VERSION 5.8 ;
BUSBITCHARS "[]" ;
DIVIDERCHAR "/" ;
UNITS
    DATABASE MICRONS 1000 ;
END UNITS

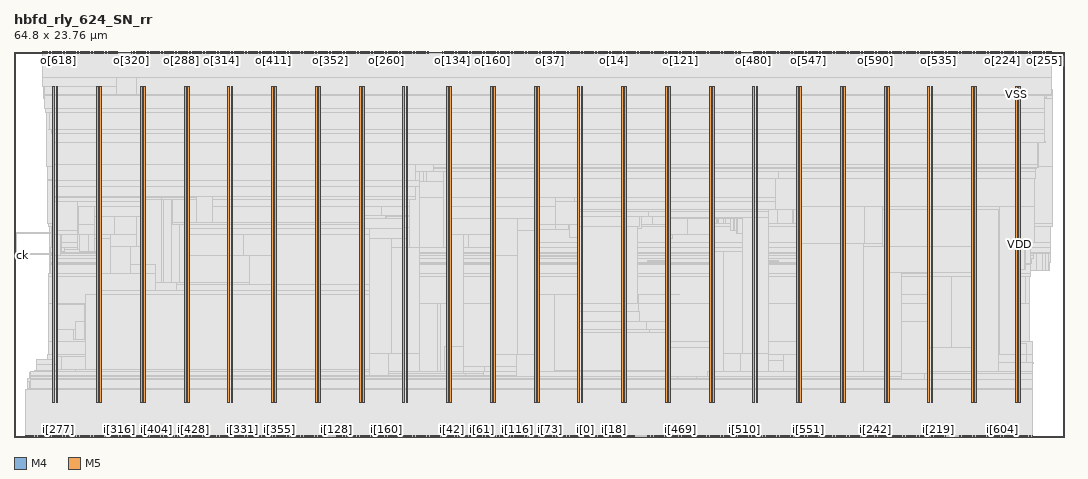
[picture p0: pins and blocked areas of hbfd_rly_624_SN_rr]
MACRO hbfd_rly_624_SN_rr
  FOREIGN hbfd_rly_624_SN_rr 0 0 ;
  CLASS BLOCK ;
  SIZE 64.8 BY 23.76 ;
  PIN ck
    DIRECTION INPUT ;
    USE SIGNAL ;
    PORT
      LAYER M4 ;
        RECT  0 11.184 0.084 11.208 ;
    END
  END ck
  PIN i[0]
    DIRECTION INPUT ;
    USE SIGNAL ;
    PORT
      LAYER M5 ;
        RECT  35.28 0 35.304 0.084 ;
    END
  END i[0]
  PIN i[100]
    DIRECTION INPUT ;
    USE SIGNAL ;
    PORT
      LAYER M5 ;
        RECT  29.52 0 29.544 0.084 ;
    END
  END i[100]
  PIN i[101]
    DIRECTION INPUT ;
    USE SIGNAL ;
    PORT
      LAYER M5 ;
        RECT  29.616 0 29.64 0.084 ;
    END
  END i[101]
  PIN i[102]
    DIRECTION INPUT ;
    USE SIGNAL ;
    PORT
      LAYER M5 ;
        RECT  29.712 0 29.736 0.084 ;
    END
  END i[102]
  PIN i[103]
    DIRECTION INPUT ;
    USE SIGNAL ;
    PORT
      LAYER M5 ;
        RECT  29.808 0 29.832 0.084 ;
    END
  END i[103]
  PIN i[104]
    DIRECTION INPUT ;
    USE SIGNAL ;
    PORT
      LAYER M5 ;
        RECT  29.904 0 29.928 0.084 ;
    END
  END i[104]
  PIN i[105]
    DIRECTION INPUT ;
    USE SIGNAL ;
    PORT
      LAYER M5 ;
        RECT  30 0 30.024 0.084 ;
    END
  END i[105]
  PIN i[106]
    DIRECTION INPUT ;
    USE SIGNAL ;
    PORT
      LAYER M5 ;
        RECT  30.096 0 30.12 0.084 ;
    END
  END i[106]
  PIN i[107]
    DIRECTION INPUT ;
    USE SIGNAL ;
    PORT
      LAYER M5 ;
        RECT  30.192 0 30.216 0.084 ;
    END
  END i[107]
  PIN i[108]
    DIRECTION INPUT ;
    USE SIGNAL ;
    PORT
      LAYER M5 ;
        RECT  30.288 0 30.312 0.084 ;
    END
  END i[108]
  PIN i[109]
    DIRECTION INPUT ;
    USE SIGNAL ;
    PORT
      LAYER M5 ;
        RECT  30.384 0 30.408 0.084 ;
    END
  END i[109]
  PIN i[10]
    DIRECTION INPUT ;
    USE SIGNAL ;
    PORT
      LAYER M5 ;
        RECT  36.24 0 36.264 0.084 ;
    END
  END i[10]
  PIN i[110]
    DIRECTION INPUT ;
    USE SIGNAL ;
    PORT
      LAYER M5 ;
        RECT  30.48 0 30.504 0.084 ;
    END
  END i[110]
  PIN i[111]
    DIRECTION INPUT ;
    USE SIGNAL ;
    PORT
      LAYER M5 ;
        RECT  30.576 0 30.6 0.084 ;
    END
  END i[111]
  PIN i[112]
    DIRECTION INPUT ;
    USE SIGNAL ;
    PORT
      LAYER M5 ;
        RECT  30.672 0 30.696 0.084 ;
    END
  END i[112]
  PIN i[113]
    DIRECTION INPUT ;
    USE SIGNAL ;
    PORT
      LAYER M5 ;
        RECT  30.768 0 30.792 0.084 ;
    END
  END i[113]
  PIN i[114]
    DIRECTION INPUT ;
    USE SIGNAL ;
    PORT
      LAYER M5 ;
        RECT  30.864 0 30.888 0.084 ;
    END
  END i[114]
  PIN i[115]
    DIRECTION INPUT ;
    USE SIGNAL ;
    PORT
      LAYER M5 ;
        RECT  30.96 0 30.984 0.084 ;
    END
  END i[115]
  PIN i[116]
    DIRECTION INPUT ;
    USE SIGNAL ;
    PORT
      LAYER M5 ;
        RECT  31.056 0 31.08 0.084 ;
    END
  END i[116]
  PIN i[117]
    DIRECTION INPUT ;
    USE SIGNAL ;
    PORT
      LAYER M5 ;
        RECT  31.152 0 31.176 0.084 ;
    END
  END i[117]
  PIN i[118]
    DIRECTION INPUT ;
    USE SIGNAL ;
    PORT
      LAYER M5 ;
        RECT  31.248 0 31.272 0.084 ;
    END
  END i[118]
  PIN i[119]
    DIRECTION INPUT ;
    USE SIGNAL ;
    PORT
      LAYER M5 ;
        RECT  31.344 0 31.368 0.084 ;
    END
  END i[119]
  PIN i[11]
    DIRECTION INPUT ;
    USE SIGNAL ;
    PORT
      LAYER M5 ;
        RECT  36.336 0 36.36 0.084 ;
    END
  END i[11]
  PIN i[120]
    DIRECTION INPUT ;
    USE SIGNAL ;
    PORT
      LAYER M5 ;
        RECT  31.44 0 31.464 0.084 ;
    END
  END i[120]
  PIN i[121]
    DIRECTION INPUT ;
    USE SIGNAL ;
    PORT
      LAYER M5 ;
        RECT  31.536 0 31.56 0.084 ;
    END
  END i[121]
  PIN i[122]
    DIRECTION INPUT ;
    USE SIGNAL ;
    PORT
      LAYER M5 ;
        RECT  31.632 0 31.656 0.084 ;
    END
  END i[122]
  PIN i[123]
    DIRECTION INPUT ;
    USE SIGNAL ;
    PORT
      LAYER M5 ;
        RECT  31.728 0 31.752 0.084 ;
    END
  END i[123]
  PIN i[124]
    DIRECTION INPUT ;
    USE SIGNAL ;
    PORT
      LAYER M5 ;
        RECT  31.824 0 31.848 0.084 ;
    END
  END i[124]
  PIN i[125]
    DIRECTION INPUT ;
    USE SIGNAL ;
    PORT
      LAYER M5 ;
        RECT  31.92 0 31.944 0.084 ;
    END
  END i[125]
  PIN i[126]
    DIRECTION INPUT ;
    USE SIGNAL ;
    PORT
      LAYER M5 ;
        RECT  32.016 0 32.04 0.084 ;
    END
  END i[126]
  PIN i[127]
    DIRECTION INPUT ;
    USE SIGNAL ;
    PORT
      LAYER M5 ;
        RECT  32.112 0 32.136 0.084 ;
    END
  END i[127]
  PIN i[128]
    DIRECTION INPUT ;
    USE SIGNAL ;
    PORT
      LAYER M5 ;
        RECT  19.92 0 19.944 0.084 ;
    END
  END i[128]
  PIN i[129]
    DIRECTION INPUT ;
    USE SIGNAL ;
    PORT
      LAYER M5 ;
        RECT  20.016 0 20.04 0.084 ;
    END
  END i[129]
  PIN i[12]
    DIRECTION INPUT ;
    USE SIGNAL ;
    PORT
      LAYER M5 ;
        RECT  36.432 0 36.456 0.084 ;
    END
  END i[12]
  PIN i[130]
    DIRECTION INPUT ;
    USE SIGNAL ;
    PORT
      LAYER M5 ;
        RECT  20.112 0 20.136 0.084 ;
    END
  END i[130]
  PIN i[131]
    DIRECTION INPUT ;
    USE SIGNAL ;
    PORT
      LAYER M5 ;
        RECT  20.208 0 20.232 0.084 ;
    END
  END i[131]
  PIN i[132]
    DIRECTION INPUT ;
    USE SIGNAL ;
    PORT
      LAYER M5 ;
        RECT  20.304 0 20.328 0.084 ;
    END
  END i[132]
  PIN i[133]
    DIRECTION INPUT ;
    USE SIGNAL ;
    PORT
      LAYER M5 ;
        RECT  20.4 0 20.424 0.084 ;
    END
  END i[133]
  PIN i[134]
    DIRECTION INPUT ;
    USE SIGNAL ;
    PORT
      LAYER M5 ;
        RECT  20.496 0 20.52 0.084 ;
    END
  END i[134]
  PIN i[135]
    DIRECTION INPUT ;
    USE SIGNAL ;
    PORT
      LAYER M5 ;
        RECT  20.592 0 20.616 0.084 ;
    END
  END i[135]
  PIN i[136]
    DIRECTION INPUT ;
    USE SIGNAL ;
    PORT
      LAYER M5 ;
        RECT  20.688 0 20.712 0.084 ;
    END
  END i[136]
  PIN i[137]
    DIRECTION INPUT ;
    USE SIGNAL ;
    PORT
      LAYER M5 ;
        RECT  20.784 0 20.808 0.084 ;
    END
  END i[137]
  PIN i[138]
    DIRECTION INPUT ;
    USE SIGNAL ;
    PORT
      LAYER M5 ;
        RECT  20.88 0 20.904 0.084 ;
    END
  END i[138]
  PIN i[139]
    DIRECTION INPUT ;
    USE SIGNAL ;
    PORT
      LAYER M5 ;
        RECT  20.976 0 21 0.084 ;
    END
  END i[139]
  PIN i[13]
    DIRECTION INPUT ;
    USE SIGNAL ;
    PORT
      LAYER M5 ;
        RECT  36.528 0 36.552 0.084 ;
    END
  END i[13]
  PIN i[140]
    DIRECTION INPUT ;
    USE SIGNAL ;
    PORT
      LAYER M5 ;
        RECT  21.072 0 21.096 0.084 ;
    END
  END i[140]
  PIN i[141]
    DIRECTION INPUT ;
    USE SIGNAL ;
    PORT
      LAYER M5 ;
        RECT  21.168 0 21.192 0.084 ;
    END
  END i[141]
  PIN i[142]
    DIRECTION INPUT ;
    USE SIGNAL ;
    PORT
      LAYER M5 ;
        RECT  21.264 0 21.288 0.084 ;
    END
  END i[142]
  PIN i[143]
    DIRECTION INPUT ;
    USE SIGNAL ;
    PORT
      LAYER M5 ;
        RECT  21.36 0 21.384 0.084 ;
    END
  END i[143]
  PIN i[144]
    DIRECTION INPUT ;
    USE SIGNAL ;
    PORT
      LAYER M5 ;
        RECT  21.456 0 21.48 0.084 ;
    END
  END i[144]
  PIN i[145]
    DIRECTION INPUT ;
    USE SIGNAL ;
    PORT
      LAYER M5 ;
        RECT  21.552 0 21.576 0.084 ;
    END
  END i[145]
  PIN i[146]
    DIRECTION INPUT ;
    USE SIGNAL ;
    PORT
      LAYER M5 ;
        RECT  21.648 0 21.672 0.084 ;
    END
  END i[146]
  PIN i[147]
    DIRECTION INPUT ;
    USE SIGNAL ;
    PORT
      LAYER M5 ;
        RECT  21.744 0 21.768 0.084 ;
    END
  END i[147]
  PIN i[148]
    DIRECTION INPUT ;
    USE SIGNAL ;
    PORT
      LAYER M5 ;
        RECT  21.84 0 21.864 0.084 ;
    END
  END i[148]
  PIN i[149]
    DIRECTION INPUT ;
    USE SIGNAL ;
    PORT
      LAYER M5 ;
        RECT  21.936 0 21.96 0.084 ;
    END
  END i[149]
  PIN i[14]
    DIRECTION INPUT ;
    USE SIGNAL ;
    PORT
      LAYER M5 ;
        RECT  36.624 0 36.648 0.084 ;
    END
  END i[14]
  PIN i[150]
    DIRECTION INPUT ;
    USE SIGNAL ;
    PORT
      LAYER M5 ;
        RECT  22.032 0 22.056 0.084 ;
    END
  END i[150]
  PIN i[151]
    DIRECTION INPUT ;
    USE SIGNAL ;
    PORT
      LAYER M5 ;
        RECT  22.128 0 22.152 0.084 ;
    END
  END i[151]
  PIN i[152]
    DIRECTION INPUT ;
    USE SIGNAL ;
    PORT
      LAYER M5 ;
        RECT  22.224 0 22.248 0.084 ;
    END
  END i[152]
  PIN i[153]
    DIRECTION INPUT ;
    USE SIGNAL ;
    PORT
      LAYER M5 ;
        RECT  22.32 0 22.344 0.084 ;
    END
  END i[153]
  PIN i[154]
    DIRECTION INPUT ;
    USE SIGNAL ;
    PORT
      LAYER M5 ;
        RECT  22.416 0 22.44 0.084 ;
    END
  END i[154]
  PIN i[155]
    DIRECTION INPUT ;
    USE SIGNAL ;
    PORT
      LAYER M5 ;
        RECT  22.512 0 22.536 0.084 ;
    END
  END i[155]
  PIN i[156]
    DIRECTION INPUT ;
    USE SIGNAL ;
    PORT
      LAYER M5 ;
        RECT  22.608 0 22.632 0.084 ;
    END
  END i[156]
  PIN i[157]
    DIRECTION INPUT ;
    USE SIGNAL ;
    PORT
      LAYER M5 ;
        RECT  22.704 0 22.728 0.084 ;
    END
  END i[157]
  PIN i[158]
    DIRECTION INPUT ;
    USE SIGNAL ;
    PORT
      LAYER M5 ;
        RECT  22.8 0 22.824 0.084 ;
    END
  END i[158]
  PIN i[159]
    DIRECTION INPUT ;
    USE SIGNAL ;
    PORT
      LAYER M5 ;
        RECT  22.896 0 22.92 0.084 ;
    END
  END i[159]
  PIN i[15]
    DIRECTION INPUT ;
    USE SIGNAL ;
    PORT
      LAYER M5 ;
        RECT  36.72 0 36.744 0.084 ;
    END
  END i[15]
  PIN i[160]
    DIRECTION INPUT ;
    USE SIGNAL ;
    PORT
      LAYER M5 ;
        RECT  22.992 0 23.016 0.084 ;
    END
  END i[160]
  PIN i[161]
    DIRECTION INPUT ;
    USE SIGNAL ;
    PORT
      LAYER M5 ;
        RECT  23.088 0 23.112 0.084 ;
    END
  END i[161]
  PIN i[162]
    DIRECTION INPUT ;
    USE SIGNAL ;
    PORT
      LAYER M5 ;
        RECT  23.184 0 23.208 0.084 ;
    END
  END i[162]
  PIN i[163]
    DIRECTION INPUT ;
    USE SIGNAL ;
    PORT
      LAYER M5 ;
        RECT  23.28 0 23.304 0.084 ;
    END
  END i[163]
  PIN i[164]
    DIRECTION INPUT ;
    USE SIGNAL ;
    PORT
      LAYER M5 ;
        RECT  23.376 0 23.4 0.084 ;
    END
  END i[164]
  PIN i[165]
    DIRECTION INPUT ;
    USE SIGNAL ;
    PORT
      LAYER M5 ;
        RECT  23.472 0 23.496 0.084 ;
    END
  END i[165]
  PIN i[166]
    DIRECTION INPUT ;
    USE SIGNAL ;
    PORT
      LAYER M5 ;
        RECT  23.568 0 23.592 0.084 ;
    END
  END i[166]
  PIN i[167]
    DIRECTION INPUT ;
    USE SIGNAL ;
    PORT
      LAYER M5 ;
        RECT  23.664 0 23.688 0.084 ;
    END
  END i[167]
  PIN i[168]
    DIRECTION INPUT ;
    USE SIGNAL ;
    PORT
      LAYER M5 ;
        RECT  23.76 0 23.784 0.084 ;
    END
  END i[168]
  PIN i[169]
    DIRECTION INPUT ;
    USE SIGNAL ;
    PORT
      LAYER M5 ;
        RECT  23.856 0 23.88 0.084 ;
    END
  END i[169]
  PIN i[16]
    DIRECTION INPUT ;
    USE SIGNAL ;
    PORT
      LAYER M5 ;
        RECT  36.816 0 36.84 0.084 ;
    END
  END i[16]
  PIN i[170]
    DIRECTION INPUT ;
    USE SIGNAL ;
    PORT
      LAYER M5 ;
        RECT  23.952 0 23.976 0.084 ;
    END
  END i[170]
  PIN i[171]
    DIRECTION INPUT ;
    USE SIGNAL ;
    PORT
      LAYER M5 ;
        RECT  24.048 0 24.072 0.084 ;
    END
  END i[171]
  PIN i[172]
    DIRECTION INPUT ;
    USE SIGNAL ;
    PORT
      LAYER M5 ;
        RECT  24.144 0 24.168 0.084 ;
    END
  END i[172]
  PIN i[173]
    DIRECTION INPUT ;
    USE SIGNAL ;
    PORT
      LAYER M5 ;
        RECT  24.24 0 24.264 0.084 ;
    END
  END i[173]
  PIN i[174]
    DIRECTION INPUT ;
    USE SIGNAL ;
    PORT
      LAYER M5 ;
        RECT  24.336 0 24.36 0.084 ;
    END
  END i[174]
  PIN i[175]
    DIRECTION INPUT ;
    USE SIGNAL ;
    PORT
      LAYER M5 ;
        RECT  24.432 0 24.456 0.084 ;
    END
  END i[175]
  PIN i[176]
    DIRECTION INPUT ;
    USE SIGNAL ;
    PORT
      LAYER M5 ;
        RECT  24.528 0 24.552 0.084 ;
    END
  END i[176]
  PIN i[177]
    DIRECTION INPUT ;
    USE SIGNAL ;
    PORT
      LAYER M5 ;
        RECT  24.624 0 24.648 0.084 ;
    END
  END i[177]
  PIN i[178]
    DIRECTION INPUT ;
    USE SIGNAL ;
    PORT
      LAYER M5 ;
        RECT  24.72 0 24.744 0.084 ;
    END
  END i[178]
  PIN i[179]
    DIRECTION INPUT ;
    USE SIGNAL ;
    PORT
      LAYER M5 ;
        RECT  24.816 0 24.84 0.084 ;
    END
  END i[179]
  PIN i[17]
    DIRECTION INPUT ;
    USE SIGNAL ;
    PORT
      LAYER M5 ;
        RECT  36.912 0 36.936 0.084 ;
    END
  END i[17]
  PIN i[180]
    DIRECTION INPUT ;
    USE SIGNAL ;
    PORT
      LAYER M5 ;
        RECT  24.912 0 24.936 0.084 ;
    END
  END i[180]
  PIN i[181]
    DIRECTION INPUT ;
    USE SIGNAL ;
    PORT
      LAYER M5 ;
        RECT  25.008 0 25.032 0.084 ;
    END
  END i[181]
  PIN i[182]
    DIRECTION INPUT ;
    USE SIGNAL ;
    PORT
      LAYER M5 ;
        RECT  25.104 0 25.128 0.084 ;
    END
  END i[182]
  PIN i[183]
    DIRECTION INPUT ;
    USE SIGNAL ;
    PORT
      LAYER M5 ;
        RECT  25.2 0 25.224 0.084 ;
    END
  END i[183]
  PIN i[184]
    DIRECTION INPUT ;
    USE SIGNAL ;
    PORT
      LAYER M5 ;
        RECT  25.296 0 25.32 0.084 ;
    END
  END i[184]
  PIN i[185]
    DIRECTION INPUT ;
    USE SIGNAL ;
    PORT
      LAYER M5 ;
        RECT  25.392 0 25.416 0.084 ;
    END
  END i[185]
  PIN i[186]
    DIRECTION INPUT ;
    USE SIGNAL ;
    PORT
      LAYER M5 ;
        RECT  25.488 0 25.512 0.084 ;
    END
  END i[186]
  PIN i[187]
    DIRECTION INPUT ;
    USE SIGNAL ;
    PORT
      LAYER M5 ;
        RECT  25.584 0 25.608 0.084 ;
    END
  END i[187]
  PIN i[188]
    DIRECTION INPUT ;
    USE SIGNAL ;
    PORT
      LAYER M5 ;
        RECT  25.68 0 25.704 0.084 ;
    END
  END i[188]
  PIN i[189]
    DIRECTION INPUT ;
    USE SIGNAL ;
    PORT
      LAYER M5 ;
        RECT  25.776 0 25.8 0.084 ;
    END
  END i[189]
  PIN i[18]
    DIRECTION INPUT ;
    USE SIGNAL ;
    PORT
      LAYER M5 ;
        RECT  37.008 0 37.032 0.084 ;
    END
  END i[18]
  PIN i[190]
    DIRECTION INPUT ;
    USE SIGNAL ;
    PORT
      LAYER M5 ;
        RECT  25.872 0 25.896 0.084 ;
    END
  END i[190]
  PIN i[191]
    DIRECTION INPUT ;
    USE SIGNAL ;
    PORT
      LAYER M5 ;
        RECT  25.968 0 25.992 0.084 ;
    END
  END i[191]
  PIN i[192]
    DIRECTION INPUT ;
    USE SIGNAL ;
    PORT
      LAYER M5 ;
        RECT  54.48 0 54.504 0.084 ;
    END
  END i[192]
  PIN i[193]
    DIRECTION INPUT ;
    USE SIGNAL ;
    PORT
      LAYER M5 ;
        RECT  54.576 0 54.6 0.084 ;
    END
  END i[193]
  PIN i[194]
    DIRECTION INPUT ;
    USE SIGNAL ;
    PORT
      LAYER M5 ;
        RECT  54.672 0 54.696 0.084 ;
    END
  END i[194]
  PIN i[195]
    DIRECTION INPUT ;
    USE SIGNAL ;
    PORT
      LAYER M5 ;
        RECT  54.768 0 54.792 0.084 ;
    END
  END i[195]
  PIN i[196]
    DIRECTION INPUT ;
    USE SIGNAL ;
    PORT
      LAYER M5 ;
        RECT  54.864 0 54.888 0.084 ;
    END
  END i[196]
  PIN i[197]
    DIRECTION INPUT ;
    USE SIGNAL ;
    PORT
      LAYER M5 ;
        RECT  54.96 0 54.984 0.084 ;
    END
  END i[197]
  PIN i[198]
    DIRECTION INPUT ;
    USE SIGNAL ;
    PORT
      LAYER M5 ;
        RECT  55.056 0 55.08 0.084 ;
    END
  END i[198]
  PIN i[199]
    DIRECTION INPUT ;
    USE SIGNAL ;
    PORT
      LAYER M5 ;
        RECT  55.152 0 55.176 0.084 ;
    END
  END i[199]
  PIN i[19]
    DIRECTION INPUT ;
    USE SIGNAL ;
    PORT
      LAYER M5 ;
        RECT  37.104 0 37.128 0.084 ;
    END
  END i[19]
  PIN i[1]
    DIRECTION INPUT ;
    USE SIGNAL ;
    PORT
      LAYER M5 ;
        RECT  35.376 0 35.4 0.084 ;
    END
  END i[1]
  PIN i[200]
    DIRECTION INPUT ;
    USE SIGNAL ;
    PORT
      LAYER M5 ;
        RECT  55.248 0 55.272 0.084 ;
    END
  END i[200]
  PIN i[201]
    DIRECTION INPUT ;
    USE SIGNAL ;
    PORT
      LAYER M5 ;
        RECT  55.344 0 55.368 0.084 ;
    END
  END i[201]
  PIN i[202]
    DIRECTION INPUT ;
    USE SIGNAL ;
    PORT
      LAYER M5 ;
        RECT  55.44 0 55.464 0.084 ;
    END
  END i[202]
  PIN i[203]
    DIRECTION INPUT ;
    USE SIGNAL ;
    PORT
      LAYER M5 ;
        RECT  55.536 0 55.56 0.084 ;
    END
  END i[203]
  PIN i[204]
    DIRECTION INPUT ;
    USE SIGNAL ;
    PORT
      LAYER M5 ;
        RECT  55.632 0 55.656 0.084 ;
    END
  END i[204]
  PIN i[205]
    DIRECTION INPUT ;
    USE SIGNAL ;
    PORT
      LAYER M5 ;
        RECT  55.728 0 55.752 0.084 ;
    END
  END i[205]
  PIN i[206]
    DIRECTION INPUT ;
    USE SIGNAL ;
    PORT
      LAYER M5 ;
        RECT  55.824 0 55.848 0.084 ;
    END
  END i[206]
  PIN i[207]
    DIRECTION INPUT ;
    USE SIGNAL ;
    PORT
      LAYER M5 ;
        RECT  55.92 0 55.944 0.084 ;
    END
  END i[207]
  PIN i[208]
    DIRECTION INPUT ;
    USE SIGNAL ;
    PORT
      LAYER M5 ;
        RECT  56.016 0 56.04 0.084 ;
    END
  END i[208]
  PIN i[209]
    DIRECTION INPUT ;
    USE SIGNAL ;
    PORT
      LAYER M5 ;
        RECT  56.112 0 56.136 0.084 ;
    END
  END i[209]
  PIN i[20]
    DIRECTION INPUT ;
    USE SIGNAL ;
    PORT
      LAYER M5 ;
        RECT  37.2 0 37.224 0.084 ;
    END
  END i[20]
  PIN i[210]
    DIRECTION INPUT ;
    USE SIGNAL ;
    PORT
      LAYER M5 ;
        RECT  56.208 0 56.232 0.084 ;
    END
  END i[210]
  PIN i[211]
    DIRECTION INPUT ;
    USE SIGNAL ;
    PORT
      LAYER M5 ;
        RECT  56.304 0 56.328 0.084 ;
    END
  END i[211]
  PIN i[212]
    DIRECTION INPUT ;
    USE SIGNAL ;
    PORT
      LAYER M5 ;
        RECT  56.4 0 56.424 0.084 ;
    END
  END i[212]
  PIN i[213]
    DIRECTION INPUT ;
    USE SIGNAL ;
    PORT
      LAYER M5 ;
        RECT  56.496 0 56.52 0.084 ;
    END
  END i[213]
  PIN i[214]
    DIRECTION INPUT ;
    USE SIGNAL ;
    PORT
      LAYER M5 ;
        RECT  56.592 0 56.616 0.084 ;
    END
  END i[214]
  PIN i[215]
    DIRECTION INPUT ;
    USE SIGNAL ;
    PORT
      LAYER M5 ;
        RECT  56.688 0 56.712 0.084 ;
    END
  END i[215]
  PIN i[216]
    DIRECTION INPUT ;
    USE SIGNAL ;
    PORT
      LAYER M5 ;
        RECT  56.784 0 56.808 0.084 ;
    END
  END i[216]
  PIN i[217]
    DIRECTION INPUT ;
    USE SIGNAL ;
    PORT
      LAYER M5 ;
        RECT  56.88 0 56.904 0.084 ;
    END
  END i[217]
  PIN i[218]
    DIRECTION INPUT ;
    USE SIGNAL ;
    PORT
      LAYER M5 ;
        RECT  56.976 0 57 0.084 ;
    END
  END i[218]
  PIN i[219]
    DIRECTION INPUT ;
    USE SIGNAL ;
    PORT
      LAYER M5 ;
        RECT  57.072 0 57.096 0.084 ;
    END
  END i[219]
  PIN i[21]
    DIRECTION INPUT ;
    USE SIGNAL ;
    PORT
      LAYER M5 ;
        RECT  37.296 0 37.32 0.084 ;
    END
  END i[21]
  PIN i[220]
    DIRECTION INPUT ;
    USE SIGNAL ;
    PORT
      LAYER M5 ;
        RECT  57.168 0 57.192 0.084 ;
    END
  END i[220]
  PIN i[221]
    DIRECTION INPUT ;
    USE SIGNAL ;
    PORT
      LAYER M5 ;
        RECT  57.264 0 57.288 0.084 ;
    END
  END i[221]
  PIN i[222]
    DIRECTION INPUT ;
    USE SIGNAL ;
    PORT
      LAYER M5 ;
        RECT  57.36 0 57.384 0.084 ;
    END
  END i[222]
  PIN i[223]
    DIRECTION INPUT ;
    USE SIGNAL ;
    PORT
      LAYER M5 ;
        RECT  57.456 0 57.48 0.084 ;
    END
  END i[223]
  PIN i[224]
    DIRECTION INPUT ;
    USE SIGNAL ;
    PORT
      LAYER M5 ;
        RECT  51.408 0 51.432 0.084 ;
    END
  END i[224]
  PIN i[225]
    DIRECTION INPUT ;
    USE SIGNAL ;
    PORT
      LAYER M5 ;
        RECT  51.504 0 51.528 0.084 ;
    END
  END i[225]
  PIN i[226]
    DIRECTION INPUT ;
    USE SIGNAL ;
    PORT
      LAYER M5 ;
        RECT  51.6 0 51.624 0.084 ;
    END
  END i[226]
  PIN i[227]
    DIRECTION INPUT ;
    USE SIGNAL ;
    PORT
      LAYER M5 ;
        RECT  51.696 0 51.72 0.084 ;
    END
  END i[227]
  PIN i[228]
    DIRECTION INPUT ;
    USE SIGNAL ;
    PORT
      LAYER M5 ;
        RECT  51.792 0 51.816 0.084 ;
    END
  END i[228]
  PIN i[229]
    DIRECTION INPUT ;
    USE SIGNAL ;
    PORT
      LAYER M5 ;
        RECT  51.888 0 51.912 0.084 ;
    END
  END i[229]
  PIN i[22]
    DIRECTION INPUT ;
    USE SIGNAL ;
    PORT
      LAYER M5 ;
        RECT  37.392 0 37.416 0.084 ;
    END
  END i[22]
  PIN i[230]
    DIRECTION INPUT ;
    USE SIGNAL ;
    PORT
      LAYER M5 ;
        RECT  51.984 0 52.008 0.084 ;
    END
  END i[230]
  PIN i[231]
    DIRECTION INPUT ;
    USE SIGNAL ;
    PORT
      LAYER M5 ;
        RECT  52.08 0 52.104 0.084 ;
    END
  END i[231]
  PIN i[232]
    DIRECTION INPUT ;
    USE SIGNAL ;
    PORT
      LAYER M5 ;
        RECT  52.176 0 52.2 0.084 ;
    END
  END i[232]
  PIN i[233]
    DIRECTION INPUT ;
    USE SIGNAL ;
    PORT
      LAYER M5 ;
        RECT  52.272 0 52.296 0.084 ;
    END
  END i[233]
  PIN i[234]
    DIRECTION INPUT ;
    USE SIGNAL ;
    PORT
      LAYER M5 ;
        RECT  52.368 0 52.392 0.084 ;
    END
  END i[234]
  PIN i[235]
    DIRECTION INPUT ;
    USE SIGNAL ;
    PORT
      LAYER M5 ;
        RECT  52.464 0 52.488 0.084 ;
    END
  END i[235]
  PIN i[236]
    DIRECTION INPUT ;
    USE SIGNAL ;
    PORT
      LAYER M5 ;
        RECT  52.56 0 52.584 0.084 ;
    END
  END i[236]
  PIN i[237]
    DIRECTION INPUT ;
    USE SIGNAL ;
    PORT
      LAYER M5 ;
        RECT  52.656 0 52.68 0.084 ;
    END
  END i[237]
  PIN i[238]
    DIRECTION INPUT ;
    USE SIGNAL ;
    PORT
      LAYER M5 ;
        RECT  52.752 0 52.776 0.084 ;
    END
  END i[238]
  PIN i[239]
    DIRECTION INPUT ;
    USE SIGNAL ;
    PORT
      LAYER M5 ;
        RECT  52.848 0 52.872 0.084 ;
    END
  END i[239]
  PIN i[23]
    DIRECTION INPUT ;
    USE SIGNAL ;
    PORT
      LAYER M5 ;
        RECT  37.488 0 37.512 0.084 ;
    END
  END i[23]
  PIN i[240]
    DIRECTION INPUT ;
    USE SIGNAL ;
    PORT
      LAYER M5 ;
        RECT  52.944 0 52.968 0.084 ;
    END
  END i[240]
  PIN i[241]
    DIRECTION INPUT ;
    USE SIGNAL ;
    PORT
      LAYER M5 ;
        RECT  53.04 0 53.064 0.084 ;
    END
  END i[241]
  PIN i[242]
    DIRECTION INPUT ;
    USE SIGNAL ;
    PORT
      LAYER M5 ;
        RECT  53.136 0 53.16 0.084 ;
    END
  END i[242]
  PIN i[243]
    DIRECTION INPUT ;
    USE SIGNAL ;
    PORT
      LAYER M5 ;
        RECT  53.232 0 53.256 0.084 ;
    END
  END i[243]
  PIN i[244]
    DIRECTION INPUT ;
    USE SIGNAL ;
    PORT
      LAYER M5 ;
        RECT  53.328 0 53.352 0.084 ;
    END
  END i[244]
  PIN i[245]
    DIRECTION INPUT ;
    USE SIGNAL ;
    PORT
      LAYER M5 ;
        RECT  53.424 0 53.448 0.084 ;
    END
  END i[245]
  PIN i[246]
    DIRECTION INPUT ;
    USE SIGNAL ;
    PORT
      LAYER M5 ;
        RECT  53.52 0 53.544 0.084 ;
    END
  END i[246]
  PIN i[247]
    DIRECTION INPUT ;
    USE SIGNAL ;
    PORT
      LAYER M5 ;
        RECT  53.616 0 53.64 0.084 ;
    END
  END i[247]
  PIN i[248]
    DIRECTION INPUT ;
    USE SIGNAL ;
    PORT
      LAYER M5 ;
        RECT  53.712 0 53.736 0.084 ;
    END
  END i[248]
  PIN i[249]
    DIRECTION INPUT ;
    USE SIGNAL ;
    PORT
      LAYER M5 ;
        RECT  53.808 0 53.832 0.084 ;
    END
  END i[249]
  PIN i[24]
    DIRECTION INPUT ;
    USE SIGNAL ;
    PORT
      LAYER M5 ;
        RECT  37.584 0 37.608 0.084 ;
    END
  END i[24]
  PIN i[250]
    DIRECTION INPUT ;
    USE SIGNAL ;
    PORT
      LAYER M5 ;
        RECT  53.904 0 53.928 0.084 ;
    END
  END i[250]
  PIN i[251]
    DIRECTION INPUT ;
    USE SIGNAL ;
    PORT
      LAYER M5 ;
        RECT  54 0 54.024 0.084 ;
    END
  END i[251]
  PIN i[252]
    DIRECTION INPUT ;
    USE SIGNAL ;
    PORT
      LAYER M5 ;
        RECT  54.096 0 54.12 0.084 ;
    END
  END i[252]
  PIN i[253]
    DIRECTION INPUT ;
    USE SIGNAL ;
    PORT
      LAYER M5 ;
        RECT  54.192 0 54.216 0.084 ;
    END
  END i[253]
  PIN i[254]
    DIRECTION INPUT ;
    USE SIGNAL ;
    PORT
      LAYER M5 ;
        RECT  54.288 0 54.312 0.084 ;
    END
  END i[254]
  PIN i[255]
    DIRECTION INPUT ;
    USE SIGNAL ;
    PORT
      LAYER M5 ;
        RECT  54.384 0 54.408 0.084 ;
    END
  END i[255]
  PIN i[256]
    DIRECTION INPUT ;
    USE SIGNAL ;
    PORT
      LAYER M5 ;
        RECT  0.72 0 0.744 0.084 ;
    END
  END i[256]
  PIN i[257]
    DIRECTION INPUT ;
    USE SIGNAL ;
    PORT
      LAYER M5 ;
        RECT  0.816 0 0.84 0.084 ;
    END
  END i[257]
  PIN i[258]
    DIRECTION INPUT ;
    USE SIGNAL ;
    PORT
      LAYER M5 ;
        RECT  0.912 0 0.936 0.084 ;
    END
  END i[258]
  PIN i[259]
    DIRECTION INPUT ;
    USE SIGNAL ;
    PORT
      LAYER M5 ;
        RECT  1.008 0 1.032 0.084 ;
    END
  END i[259]
  PIN i[25]
    DIRECTION INPUT ;
    USE SIGNAL ;
    PORT
      LAYER M5 ;
        RECT  37.68 0 37.704 0.084 ;
    END
  END i[25]
  PIN i[260]
    DIRECTION INPUT ;
    USE SIGNAL ;
    PORT
      LAYER M5 ;
        RECT  1.104 0 1.128 0.084 ;
    END
  END i[260]
  PIN i[261]
    DIRECTION INPUT ;
    USE SIGNAL ;
    PORT
      LAYER M5 ;
        RECT  1.2 0 1.224 0.084 ;
    END
  END i[261]
  PIN i[262]
    DIRECTION INPUT ;
    USE SIGNAL ;
    PORT
      LAYER M5 ;
        RECT  1.296 0 1.32 0.084 ;
    END
  END i[262]
  PIN i[263]
    DIRECTION INPUT ;
    USE SIGNAL ;
    PORT
      LAYER M5 ;
        RECT  1.392 0 1.416 0.084 ;
    END
  END i[263]
  PIN i[264]
    DIRECTION INPUT ;
    USE SIGNAL ;
    PORT
      LAYER M5 ;
        RECT  1.488 0 1.512 0.084 ;
    END
  END i[264]
  PIN i[265]
    DIRECTION INPUT ;
    USE SIGNAL ;
    PORT
      LAYER M5 ;
        RECT  1.584 0 1.608 0.084 ;
    END
  END i[265]
  PIN i[266]
    DIRECTION INPUT ;
    USE SIGNAL ;
    PORT
      LAYER M5 ;
        RECT  1.68 0 1.704 0.084 ;
    END
  END i[266]
  PIN i[267]
    DIRECTION INPUT ;
    USE SIGNAL ;
    PORT
      LAYER M5 ;
        RECT  1.776 0 1.8 0.084 ;
    END
  END i[267]
  PIN i[268]
    DIRECTION INPUT ;
    USE SIGNAL ;
    PORT
      LAYER M5 ;
        RECT  1.872 0 1.896 0.084 ;
    END
  END i[268]
  PIN i[269]
    DIRECTION INPUT ;
    USE SIGNAL ;
    PORT
      LAYER M5 ;
        RECT  1.968 0 1.992 0.084 ;
    END
  END i[269]
  PIN i[26]
    DIRECTION INPUT ;
    USE SIGNAL ;
    PORT
      LAYER M5 ;
        RECT  37.776 0 37.8 0.084 ;
    END
  END i[26]
  PIN i[270]
    DIRECTION INPUT ;
    USE SIGNAL ;
    PORT
      LAYER M5 ;
        RECT  2.064 0 2.088 0.084 ;
    END
  END i[270]
  PIN i[271]
    DIRECTION INPUT ;
    USE SIGNAL ;
    PORT
      LAYER M5 ;
        RECT  2.16 0 2.184 0.084 ;
    END
  END i[271]
  PIN i[272]
    DIRECTION INPUT ;
    USE SIGNAL ;
    PORT
      LAYER M5 ;
        RECT  2.256 0 2.28 0.084 ;
    END
  END i[272]
  PIN i[273]
    DIRECTION INPUT ;
    USE SIGNAL ;
    PORT
      LAYER M5 ;
        RECT  2.352 0 2.376 0.084 ;
    END
  END i[273]
  PIN i[274]
    DIRECTION INPUT ;
    USE SIGNAL ;
    PORT
      LAYER M5 ;
        RECT  2.448 0 2.472 0.084 ;
    END
  END i[274]
  PIN i[275]
    DIRECTION INPUT ;
    USE SIGNAL ;
    PORT
      LAYER M5 ;
        RECT  2.544 0 2.568 0.084 ;
    END
  END i[275]
  PIN i[276]
    DIRECTION INPUT ;
    USE SIGNAL ;
    PORT
      LAYER M5 ;
        RECT  2.64 0 2.664 0.084 ;
    END
  END i[276]
  PIN i[277]
    DIRECTION INPUT ;
    USE SIGNAL ;
    PORT
      LAYER M5 ;
        RECT  2.736 0 2.76 0.084 ;
    END
  END i[277]
  PIN i[278]
    DIRECTION INPUT ;
    USE SIGNAL ;
    PORT
      LAYER M5 ;
        RECT  2.832 0 2.856 0.084 ;
    END
  END i[278]
  PIN i[279]
    DIRECTION INPUT ;
    USE SIGNAL ;
    PORT
      LAYER M5 ;
        RECT  2.928 0 2.952 0.084 ;
    END
  END i[279]
  PIN i[27]
    DIRECTION INPUT ;
    USE SIGNAL ;
    PORT
      LAYER M5 ;
        RECT  37.872 0 37.896 0.084 ;
    END
  END i[27]
  PIN i[280]
    DIRECTION INPUT ;
    USE SIGNAL ;
    PORT
      LAYER M5 ;
        RECT  3.024 0 3.048 0.084 ;
    END
  END i[280]
  PIN i[281]
    DIRECTION INPUT ;
    USE SIGNAL ;
    PORT
      LAYER M5 ;
        RECT  3.12 0 3.144 0.084 ;
    END
  END i[281]
  PIN i[282]
    DIRECTION INPUT ;
    USE SIGNAL ;
    PORT
      LAYER M5 ;
        RECT  3.216 0 3.24 0.084 ;
    END
  END i[282]
  PIN i[283]
    DIRECTION INPUT ;
    USE SIGNAL ;
    PORT
      LAYER M5 ;
        RECT  3.312 0 3.336 0.084 ;
    END
  END i[283]
  PIN i[284]
    DIRECTION INPUT ;
    USE SIGNAL ;
    PORT
      LAYER M5 ;
        RECT  3.408 0 3.432 0.084 ;
    END
  END i[284]
  PIN i[285]
    DIRECTION INPUT ;
    USE SIGNAL ;
    PORT
      LAYER M5 ;
        RECT  3.504 0 3.528 0.084 ;
    END
  END i[285]
  PIN i[286]
    DIRECTION INPUT ;
    USE SIGNAL ;
    PORT
      LAYER M5 ;
        RECT  3.6 0 3.624 0.084 ;
    END
  END i[286]
  PIN i[287]
    DIRECTION INPUT ;
    USE SIGNAL ;
    PORT
      LAYER M5 ;
        RECT  3.696 0 3.72 0.084 ;
    END
  END i[287]
  PIN i[288]
    DIRECTION INPUT ;
    USE SIGNAL ;
    PORT
      LAYER M5 ;
        RECT  3.792 0 3.816 0.084 ;
    END
  END i[288]
  PIN i[289]
    DIRECTION INPUT ;
    USE SIGNAL ;
    PORT
      LAYER M5 ;
        RECT  3.888 0 3.912 0.084 ;
    END
  END i[289]
  PIN i[28]
    DIRECTION INPUT ;
    USE SIGNAL ;
    PORT
      LAYER M5 ;
        RECT  37.968 0 37.992 0.084 ;
    END
  END i[28]
  PIN i[290]
    DIRECTION INPUT ;
    USE SIGNAL ;
    PORT
      LAYER M5 ;
        RECT  3.984 0 4.008 0.084 ;
    END
  END i[290]
  PIN i[291]
    DIRECTION INPUT ;
    USE SIGNAL ;
    PORT
      LAYER M5 ;
        RECT  4.08 0 4.104 0.084 ;
    END
  END i[291]
  PIN i[292]
    DIRECTION INPUT ;
    USE SIGNAL ;
    PORT
      LAYER M5 ;
        RECT  4.176 0 4.2 0.084 ;
    END
  END i[292]
  PIN i[293]
    DIRECTION INPUT ;
    USE SIGNAL ;
    PORT
      LAYER M5 ;
        RECT  4.272 0 4.296 0.084 ;
    END
  END i[293]
  PIN i[294]
    DIRECTION INPUT ;
    USE SIGNAL ;
    PORT
      LAYER M5 ;
        RECT  4.368 0 4.392 0.084 ;
    END
  END i[294]
  PIN i[295]
    DIRECTION INPUT ;
    USE SIGNAL ;
    PORT
      LAYER M5 ;
        RECT  4.464 0 4.488 0.084 ;
    END
  END i[295]
  PIN i[296]
    DIRECTION INPUT ;
    USE SIGNAL ;
    PORT
      LAYER M5 ;
        RECT  4.56 0 4.584 0.084 ;
    END
  END i[296]
  PIN i[297]
    DIRECTION INPUT ;
    USE SIGNAL ;
    PORT
      LAYER M5 ;
        RECT  4.656 0 4.68 0.084 ;
    END
  END i[297]
  PIN i[298]
    DIRECTION INPUT ;
    USE SIGNAL ;
    PORT
      LAYER M5 ;
        RECT  4.752 0 4.776 0.084 ;
    END
  END i[298]
  PIN i[299]
    DIRECTION INPUT ;
    USE SIGNAL ;
    PORT
      LAYER M5 ;
        RECT  4.848 0 4.872 0.084 ;
    END
  END i[299]
  PIN i[29]
    DIRECTION INPUT ;
    USE SIGNAL ;
    PORT
      LAYER M5 ;
        RECT  38.064 0 38.088 0.084 ;
    END
  END i[29]
  PIN i[2]
    DIRECTION INPUT ;
    USE SIGNAL ;
    PORT
      LAYER M5 ;
        RECT  35.472 0 35.496 0.084 ;
    END
  END i[2]
  PIN i[300]
    DIRECTION INPUT ;
    USE SIGNAL ;
    PORT
      LAYER M5 ;
        RECT  4.944 0 4.968 0.084 ;
    END
  END i[300]
  PIN i[301]
    DIRECTION INPUT ;
    USE SIGNAL ;
    PORT
      LAYER M5 ;
        RECT  5.04 0 5.064 0.084 ;
    END
  END i[301]
  PIN i[302]
    DIRECTION INPUT ;
    USE SIGNAL ;
    PORT
      LAYER M5 ;
        RECT  5.136 0 5.16 0.084 ;
    END
  END i[302]
  PIN i[303]
    DIRECTION INPUT ;
    USE SIGNAL ;
    PORT
      LAYER M5 ;
        RECT  5.232 0 5.256 0.084 ;
    END
  END i[303]
  PIN i[304]
    DIRECTION INPUT ;
    USE SIGNAL ;
    PORT
      LAYER M5 ;
        RECT  5.328 0 5.352 0.084 ;
    END
  END i[304]
  PIN i[305]
    DIRECTION INPUT ;
    USE SIGNAL ;
    PORT
      LAYER M5 ;
        RECT  5.424 0 5.448 0.084 ;
    END
  END i[305]
  PIN i[306]
    DIRECTION INPUT ;
    USE SIGNAL ;
    PORT
      LAYER M5 ;
        RECT  5.52 0 5.544 0.084 ;
    END
  END i[306]
  PIN i[307]
    DIRECTION INPUT ;
    USE SIGNAL ;
    PORT
      LAYER M5 ;
        RECT  5.616 0 5.64 0.084 ;
    END
  END i[307]
  PIN i[308]
    DIRECTION INPUT ;
    USE SIGNAL ;
    PORT
      LAYER M5 ;
        RECT  5.712 0 5.736 0.084 ;
    END
  END i[308]
  PIN i[309]
    DIRECTION INPUT ;
    USE SIGNAL ;
    PORT
      LAYER M5 ;
        RECT  5.808 0 5.832 0.084 ;
    END
  END i[309]
  PIN i[30]
    DIRECTION INPUT ;
    USE SIGNAL ;
    PORT
      LAYER M5 ;
        RECT  38.16 0 38.184 0.084 ;
    END
  END i[30]
  PIN i[310]
    DIRECTION INPUT ;
    USE SIGNAL ;
    PORT
      LAYER M5 ;
        RECT  5.904 0 5.928 0.084 ;
    END
  END i[310]
  PIN i[311]
    DIRECTION INPUT ;
    USE SIGNAL ;
    PORT
      LAYER M5 ;
        RECT  6 0 6.024 0.084 ;
    END
  END i[311]
  PIN i[312]
    DIRECTION INPUT ;
    USE SIGNAL ;
    PORT
      LAYER M5 ;
        RECT  6.096 0 6.12 0.084 ;
    END
  END i[312]
  PIN i[313]
    DIRECTION INPUT ;
    USE SIGNAL ;
    PORT
      LAYER M5 ;
        RECT  6.192 0 6.216 0.084 ;
    END
  END i[313]
  PIN i[314]
    DIRECTION INPUT ;
    USE SIGNAL ;
    PORT
      LAYER M5 ;
        RECT  6.288 0 6.312 0.084 ;
    END
  END i[314]
  PIN i[315]
    DIRECTION INPUT ;
    USE SIGNAL ;
    PORT
      LAYER M5 ;
        RECT  6.384 0 6.408 0.084 ;
    END
  END i[315]
  PIN i[316]
    DIRECTION INPUT ;
    USE SIGNAL ;
    PORT
      LAYER M5 ;
        RECT  6.48 0 6.504 0.084 ;
    END
  END i[316]
  PIN i[317]
    DIRECTION INPUT ;
    USE SIGNAL ;
    PORT
      LAYER M5 ;
        RECT  6.576 0 6.6 0.084 ;
    END
  END i[317]
  PIN i[318]
    DIRECTION INPUT ;
    USE SIGNAL ;
    PORT
      LAYER M5 ;
        RECT  6.672 0 6.696 0.084 ;
    END
  END i[318]
  PIN i[319]
    DIRECTION INPUT ;
    USE SIGNAL ;
    PORT
      LAYER M5 ;
        RECT  6.768 0 6.792 0.084 ;
    END
  END i[319]
  PIN i[31]
    DIRECTION INPUT ;
    USE SIGNAL ;
    PORT
      LAYER M5 ;
        RECT  38.256 0 38.28 0.084 ;
    END
  END i[31]
  PIN i[320]
    DIRECTION INPUT ;
    USE SIGNAL ;
    PORT
      LAYER M5 ;
        RECT  13.008 0 13.032 0.084 ;
    END
  END i[320]
  PIN i[321]
    DIRECTION INPUT ;
    USE SIGNAL ;
    PORT
      LAYER M5 ;
        RECT  13.104 0 13.128 0.084 ;
    END
  END i[321]
  PIN i[322]
    DIRECTION INPUT ;
    USE SIGNAL ;
    PORT
      LAYER M5 ;
        RECT  13.2 0 13.224 0.084 ;
    END
  END i[322]
  PIN i[323]
    DIRECTION INPUT ;
    USE SIGNAL ;
    PORT
      LAYER M5 ;
        RECT  13.296 0 13.32 0.084 ;
    END
  END i[323]
  PIN i[324]
    DIRECTION INPUT ;
    USE SIGNAL ;
    PORT
      LAYER M5 ;
        RECT  13.392 0 13.416 0.084 ;
    END
  END i[324]
  PIN i[325]
    DIRECTION INPUT ;
    USE SIGNAL ;
    PORT
      LAYER M5 ;
        RECT  13.488 0 13.512 0.084 ;
    END
  END i[325]
  PIN i[326]
    DIRECTION INPUT ;
    USE SIGNAL ;
    PORT
      LAYER M5 ;
        RECT  13.584 0 13.608 0.084 ;
    END
  END i[326]
  PIN i[327]
    DIRECTION INPUT ;
    USE SIGNAL ;
    PORT
      LAYER M5 ;
        RECT  13.68 0 13.704 0.084 ;
    END
  END i[327]
  PIN i[328]
    DIRECTION INPUT ;
    USE SIGNAL ;
    PORT
      LAYER M5 ;
        RECT  13.776 0 13.8 0.084 ;
    END
  END i[328]
  PIN i[329]
    DIRECTION INPUT ;
    USE SIGNAL ;
    PORT
      LAYER M5 ;
        RECT  13.872 0 13.896 0.084 ;
    END
  END i[329]
  PIN i[32]
    DIRECTION INPUT ;
    USE SIGNAL ;
    PORT
      LAYER M5 ;
        RECT  26.064 0 26.088 0.084 ;
    END
  END i[32]
  PIN i[330]
    DIRECTION INPUT ;
    USE SIGNAL ;
    PORT
      LAYER M5 ;
        RECT  13.968 0 13.992 0.084 ;
    END
  END i[330]
  PIN i[331]
    DIRECTION INPUT ;
    USE SIGNAL ;
    PORT
      LAYER M5 ;
        RECT  14.064 0 14.088 0.084 ;
    END
  END i[331]
  PIN i[332]
    DIRECTION INPUT ;
    USE SIGNAL ;
    PORT
      LAYER M5 ;
        RECT  14.16 0 14.184 0.084 ;
    END
  END i[332]
  PIN i[333]
    DIRECTION INPUT ;
    USE SIGNAL ;
    PORT
      LAYER M5 ;
        RECT  14.256 0 14.28 0.084 ;
    END
  END i[333]
  PIN i[334]
    DIRECTION INPUT ;
    USE SIGNAL ;
    PORT
      LAYER M5 ;
        RECT  14.352 0 14.376 0.084 ;
    END
  END i[334]
  PIN i[335]
    DIRECTION INPUT ;
    USE SIGNAL ;
    PORT
      LAYER M5 ;
        RECT  14.448 0 14.472 0.084 ;
    END
  END i[335]
  PIN i[336]
    DIRECTION INPUT ;
    USE SIGNAL ;
    PORT
      LAYER M5 ;
        RECT  14.544 0 14.568 0.084 ;
    END
  END i[336]
  PIN i[337]
    DIRECTION INPUT ;
    USE SIGNAL ;
    PORT
      LAYER M5 ;
        RECT  14.64 0 14.664 0.084 ;
    END
  END i[337]
  PIN i[338]
    DIRECTION INPUT ;
    USE SIGNAL ;
    PORT
      LAYER M5 ;
        RECT  14.736 0 14.76 0.084 ;
    END
  END i[338]
  PIN i[339]
    DIRECTION INPUT ;
    USE SIGNAL ;
    PORT
      LAYER M5 ;
        RECT  14.832 0 14.856 0.084 ;
    END
  END i[339]
  PIN i[33]
    DIRECTION INPUT ;
    USE SIGNAL ;
    PORT
      LAYER M5 ;
        RECT  26.16 0 26.184 0.084 ;
    END
  END i[33]
  PIN i[340]
    DIRECTION INPUT ;
    USE SIGNAL ;
    PORT
      LAYER M5 ;
        RECT  14.928 0 14.952 0.084 ;
    END
  END i[340]
  PIN i[341]
    DIRECTION INPUT ;
    USE SIGNAL ;
    PORT
      LAYER M5 ;
        RECT  15.024 0 15.048 0.084 ;
    END
  END i[341]
  PIN i[342]
    DIRECTION INPUT ;
    USE SIGNAL ;
    PORT
      LAYER M5 ;
        RECT  15.12 0 15.144 0.084 ;
    END
  END i[342]
  PIN i[343]
    DIRECTION INPUT ;
    USE SIGNAL ;
    PORT
      LAYER M5 ;
        RECT  15.216 0 15.24 0.084 ;
    END
  END i[343]
  PIN i[344]
    DIRECTION INPUT ;
    USE SIGNAL ;
    PORT
      LAYER M5 ;
        RECT  15.312 0 15.336 0.084 ;
    END
  END i[344]
  PIN i[345]
    DIRECTION INPUT ;
    USE SIGNAL ;
    PORT
      LAYER M5 ;
        RECT  15.408 0 15.432 0.084 ;
    END
  END i[345]
  PIN i[346]
    DIRECTION INPUT ;
    USE SIGNAL ;
    PORT
      LAYER M5 ;
        RECT  15.504 0 15.528 0.084 ;
    END
  END i[346]
  PIN i[347]
    DIRECTION INPUT ;
    USE SIGNAL ;
    PORT
      LAYER M5 ;
        RECT  15.6 0 15.624 0.084 ;
    END
  END i[347]
  PIN i[348]
    DIRECTION INPUT ;
    USE SIGNAL ;
    PORT
      LAYER M5 ;
        RECT  15.696 0 15.72 0.084 ;
    END
  END i[348]
  PIN i[349]
    DIRECTION INPUT ;
    USE SIGNAL ;
    PORT
      LAYER M5 ;
        RECT  15.792 0 15.816 0.084 ;
    END
  END i[349]
  PIN i[34]
    DIRECTION INPUT ;
    USE SIGNAL ;
    PORT
      LAYER M5 ;
        RECT  26.256 0 26.28 0.084 ;
    END
  END i[34]
  PIN i[350]
    DIRECTION INPUT ;
    USE SIGNAL ;
    PORT
      LAYER M5 ;
        RECT  15.888 0 15.912 0.084 ;
    END
  END i[350]
  PIN i[351]
    DIRECTION INPUT ;
    USE SIGNAL ;
    PORT
      LAYER M5 ;
        RECT  15.984 0 16.008 0.084 ;
    END
  END i[351]
  PIN i[352]
    DIRECTION INPUT ;
    USE SIGNAL ;
    PORT
      LAYER M5 ;
        RECT  16.08 0 16.104 0.084 ;
    END
  END i[352]
  PIN i[353]
    DIRECTION INPUT ;
    USE SIGNAL ;
    PORT
      LAYER M5 ;
        RECT  16.176 0 16.2 0.084 ;
    END
  END i[353]
  PIN i[354]
    DIRECTION INPUT ;
    USE SIGNAL ;
    PORT
      LAYER M5 ;
        RECT  16.272 0 16.296 0.084 ;
    END
  END i[354]
  PIN i[355]
    DIRECTION INPUT ;
    USE SIGNAL ;
    PORT
      LAYER M5 ;
        RECT  16.368 0 16.392 0.084 ;
    END
  END i[355]
  PIN i[356]
    DIRECTION INPUT ;
    USE SIGNAL ;
    PORT
      LAYER M5 ;
        RECT  16.464 0 16.488 0.084 ;
    END
  END i[356]
  PIN i[357]
    DIRECTION INPUT ;
    USE SIGNAL ;
    PORT
      LAYER M5 ;
        RECT  16.56 0 16.584 0.084 ;
    END
  END i[357]
  PIN i[358]
    DIRECTION INPUT ;
    USE SIGNAL ;
    PORT
      LAYER M5 ;
        RECT  16.656 0 16.68 0.084 ;
    END
  END i[358]
  PIN i[359]
    DIRECTION INPUT ;
    USE SIGNAL ;
    PORT
      LAYER M5 ;
        RECT  16.752 0 16.776 0.084 ;
    END
  END i[359]
  PIN i[35]
    DIRECTION INPUT ;
    USE SIGNAL ;
    PORT
      LAYER M5 ;
        RECT  26.352 0 26.376 0.084 ;
    END
  END i[35]
  PIN i[360]
    DIRECTION INPUT ;
    USE SIGNAL ;
    PORT
      LAYER M5 ;
        RECT  16.848 0 16.872 0.084 ;
    END
  END i[360]
  PIN i[361]
    DIRECTION INPUT ;
    USE SIGNAL ;
    PORT
      LAYER M5 ;
        RECT  16.944 0 16.968 0.084 ;
    END
  END i[361]
  PIN i[362]
    DIRECTION INPUT ;
    USE SIGNAL ;
    PORT
      LAYER M5 ;
        RECT  17.04 0 17.064 0.084 ;
    END
  END i[362]
  PIN i[363]
    DIRECTION INPUT ;
    USE SIGNAL ;
    PORT
      LAYER M5 ;
        RECT  17.136 0 17.16 0.084 ;
    END
  END i[363]
  PIN i[364]
    DIRECTION INPUT ;
    USE SIGNAL ;
    PORT
      LAYER M5 ;
        RECT  17.232 0 17.256 0.084 ;
    END
  END i[364]
  PIN i[365]
    DIRECTION INPUT ;
    USE SIGNAL ;
    PORT
      LAYER M5 ;
        RECT  17.328 0 17.352 0.084 ;
    END
  END i[365]
  PIN i[366]
    DIRECTION INPUT ;
    USE SIGNAL ;
    PORT
      LAYER M5 ;
        RECT  17.424 0 17.448 0.084 ;
    END
  END i[366]
  PIN i[367]
    DIRECTION INPUT ;
    USE SIGNAL ;
    PORT
      LAYER M5 ;
        RECT  17.52 0 17.544 0.084 ;
    END
  END i[367]
  PIN i[368]
    DIRECTION INPUT ;
    USE SIGNAL ;
    PORT
      LAYER M5 ;
        RECT  17.616 0 17.64 0.084 ;
    END
  END i[368]
  PIN i[369]
    DIRECTION INPUT ;
    USE SIGNAL ;
    PORT
      LAYER M5 ;
        RECT  17.712 0 17.736 0.084 ;
    END
  END i[369]
  PIN i[36]
    DIRECTION INPUT ;
    USE SIGNAL ;
    PORT
      LAYER M5 ;
        RECT  26.448 0 26.472 0.084 ;
    END
  END i[36]
  PIN i[370]
    DIRECTION INPUT ;
    USE SIGNAL ;
    PORT
      LAYER M5 ;
        RECT  17.808 0 17.832 0.084 ;
    END
  END i[370]
  PIN i[371]
    DIRECTION INPUT ;
    USE SIGNAL ;
    PORT
      LAYER M5 ;
        RECT  17.904 0 17.928 0.084 ;
    END
  END i[371]
  PIN i[372]
    DIRECTION INPUT ;
    USE SIGNAL ;
    PORT
      LAYER M5 ;
        RECT  18 0 18.024 0.084 ;
    END
  END i[372]
  PIN i[373]
    DIRECTION INPUT ;
    USE SIGNAL ;
    PORT
      LAYER M5 ;
        RECT  18.096 0 18.12 0.084 ;
    END
  END i[373]
  PIN i[374]
    DIRECTION INPUT ;
    USE SIGNAL ;
    PORT
      LAYER M5 ;
        RECT  18.192 0 18.216 0.084 ;
    END
  END i[374]
  PIN i[375]
    DIRECTION INPUT ;
    USE SIGNAL ;
    PORT
      LAYER M5 ;
        RECT  18.288 0 18.312 0.084 ;
    END
  END i[375]
  PIN i[376]
    DIRECTION INPUT ;
    USE SIGNAL ;
    PORT
      LAYER M5 ;
        RECT  18.384 0 18.408 0.084 ;
    END
  END i[376]
  PIN i[377]
    DIRECTION INPUT ;
    USE SIGNAL ;
    PORT
      LAYER M5 ;
        RECT  18.48 0 18.504 0.084 ;
    END
  END i[377]
  PIN i[378]
    DIRECTION INPUT ;
    USE SIGNAL ;
    PORT
      LAYER M5 ;
        RECT  18.576 0 18.6 0.084 ;
    END
  END i[378]
  PIN i[379]
    DIRECTION INPUT ;
    USE SIGNAL ;
    PORT
      LAYER M5 ;
        RECT  18.672 0 18.696 0.084 ;
    END
  END i[379]
  PIN i[37]
    DIRECTION INPUT ;
    USE SIGNAL ;
    PORT
      LAYER M5 ;
        RECT  26.544 0 26.568 0.084 ;
    END
  END i[37]
  PIN i[380]
    DIRECTION INPUT ;
    USE SIGNAL ;
    PORT
      LAYER M5 ;
        RECT  18.768 0 18.792 0.084 ;
    END
  END i[380]
  PIN i[381]
    DIRECTION INPUT ;
    USE SIGNAL ;
    PORT
      LAYER M5 ;
        RECT  18.864 0 18.888 0.084 ;
    END
  END i[381]
  PIN i[382]
    DIRECTION INPUT ;
    USE SIGNAL ;
    PORT
      LAYER M5 ;
        RECT  18.96 0 18.984 0.084 ;
    END
  END i[382]
  PIN i[383]
    DIRECTION INPUT ;
    USE SIGNAL ;
    PORT
      LAYER M5 ;
        RECT  19.056 0 19.08 0.084 ;
    END
  END i[383]
  PIN i[384]
    DIRECTION INPUT ;
    USE SIGNAL ;
    PORT
      LAYER M5 ;
        RECT  6.864 0 6.888 0.084 ;
    END
  END i[384]
  PIN i[385]
    DIRECTION INPUT ;
    USE SIGNAL ;
    PORT
      LAYER M5 ;
        RECT  6.96 0 6.984 0.084 ;
    END
  END i[385]
  PIN i[386]
    DIRECTION INPUT ;
    USE SIGNAL ;
    PORT
      LAYER M5 ;
        RECT  7.056 0 7.08 0.084 ;
    END
  END i[386]
  PIN i[387]
    DIRECTION INPUT ;
    USE SIGNAL ;
    PORT
      LAYER M5 ;
        RECT  7.152 0 7.176 0.084 ;
    END
  END i[387]
  PIN i[388]
    DIRECTION INPUT ;
    USE SIGNAL ;
    PORT
      LAYER M5 ;
        RECT  7.248 0 7.272 0.084 ;
    END
  END i[388]
  PIN i[389]
    DIRECTION INPUT ;
    USE SIGNAL ;
    PORT
      LAYER M5 ;
        RECT  7.344 0 7.368 0.084 ;
    END
  END i[389]
  PIN i[38]
    DIRECTION INPUT ;
    USE SIGNAL ;
    PORT
      LAYER M5 ;
        RECT  26.64 0 26.664 0.084 ;
    END
  END i[38]
  PIN i[390]
    DIRECTION INPUT ;
    USE SIGNAL ;
    PORT
      LAYER M5 ;
        RECT  7.44 0 7.464 0.084 ;
    END
  END i[390]
  PIN i[391]
    DIRECTION INPUT ;
    USE SIGNAL ;
    PORT
      LAYER M5 ;
        RECT  7.536 0 7.56 0.084 ;
    END
  END i[391]
  PIN i[392]
    DIRECTION INPUT ;
    USE SIGNAL ;
    PORT
      LAYER M5 ;
        RECT  7.632 0 7.656 0.084 ;
    END
  END i[392]
  PIN i[393]
    DIRECTION INPUT ;
    USE SIGNAL ;
    PORT
      LAYER M5 ;
        RECT  7.728 0 7.752 0.084 ;
    END
  END i[393]
  PIN i[394]
    DIRECTION INPUT ;
    USE SIGNAL ;
    PORT
      LAYER M5 ;
        RECT  7.824 0 7.848 0.084 ;
    END
  END i[394]
  PIN i[395]
    DIRECTION INPUT ;
    USE SIGNAL ;
    PORT
      LAYER M5 ;
        RECT  7.92 0 7.944 0.084 ;
    END
  END i[395]
  PIN i[396]
    DIRECTION INPUT ;
    USE SIGNAL ;
    PORT
      LAYER M5 ;
        RECT  8.016 0 8.04 0.084 ;
    END
  END i[396]
  PIN i[397]
    DIRECTION INPUT ;
    USE SIGNAL ;
    PORT
      LAYER M5 ;
        RECT  8.112 0 8.136 0.084 ;
    END
  END i[397]
  PIN i[398]
    DIRECTION INPUT ;
    USE SIGNAL ;
    PORT
      LAYER M5 ;
        RECT  8.208 0 8.232 0.084 ;
    END
  END i[398]
  PIN i[399]
    DIRECTION INPUT ;
    USE SIGNAL ;
    PORT
      LAYER M5 ;
        RECT  8.304 0 8.328 0.084 ;
    END
  END i[399]
  PIN i[39]
    DIRECTION INPUT ;
    USE SIGNAL ;
    PORT
      LAYER M5 ;
        RECT  26.736 0 26.76 0.084 ;
    END
  END i[39]
  PIN i[3]
    DIRECTION INPUT ;
    USE SIGNAL ;
    PORT
      LAYER M5 ;
        RECT  35.568 0 35.592 0.084 ;
    END
  END i[3]
  PIN i[400]
    DIRECTION INPUT ;
    USE SIGNAL ;
    PORT
      LAYER M5 ;
        RECT  8.4 0 8.424 0.084 ;
    END
  END i[400]
  PIN i[401]
    DIRECTION INPUT ;
    USE SIGNAL ;
    PORT
      LAYER M5 ;
        RECT  8.496 0 8.52 0.084 ;
    END
  END i[401]
  PIN i[402]
    DIRECTION INPUT ;
    USE SIGNAL ;
    PORT
      LAYER M5 ;
        RECT  8.592 0 8.616 0.084 ;
    END
  END i[402]
  PIN i[403]
    DIRECTION INPUT ;
    USE SIGNAL ;
    PORT
      LAYER M5 ;
        RECT  8.688 0 8.712 0.084 ;
    END
  END i[403]
  PIN i[404]
    DIRECTION INPUT ;
    USE SIGNAL ;
    PORT
      LAYER M5 ;
        RECT  8.784 0 8.808 0.084 ;
    END
  END i[404]
  PIN i[405]
    DIRECTION INPUT ;
    USE SIGNAL ;
    PORT
      LAYER M5 ;
        RECT  8.88 0 8.904 0.084 ;
    END
  END i[405]
  PIN i[406]
    DIRECTION INPUT ;
    USE SIGNAL ;
    PORT
      LAYER M5 ;
        RECT  8.976 0 9 0.084 ;
    END
  END i[406]
  PIN i[407]
    DIRECTION INPUT ;
    USE SIGNAL ;
    PORT
      LAYER M5 ;
        RECT  9.072 0 9.096 0.084 ;
    END
  END i[407]
  PIN i[408]
    DIRECTION INPUT ;
    USE SIGNAL ;
    PORT
      LAYER M5 ;
        RECT  9.168 0 9.192 0.084 ;
    END
  END i[408]
  PIN i[409]
    DIRECTION INPUT ;
    USE SIGNAL ;
    PORT
      LAYER M5 ;
        RECT  9.264 0 9.288 0.084 ;
    END
  END i[409]
  PIN i[40]
    DIRECTION INPUT ;
    USE SIGNAL ;
    PORT
      LAYER M5 ;
        RECT  26.832 0 26.856 0.084 ;
    END
  END i[40]
  PIN i[410]
    DIRECTION INPUT ;
    USE SIGNAL ;
    PORT
      LAYER M5 ;
        RECT  9.36 0 9.384 0.084 ;
    END
  END i[410]
  PIN i[411]
    DIRECTION INPUT ;
    USE SIGNAL ;
    PORT
      LAYER M5 ;
        RECT  9.456 0 9.48 0.084 ;
    END
  END i[411]
  PIN i[412]
    DIRECTION INPUT ;
    USE SIGNAL ;
    PORT
      LAYER M5 ;
        RECT  9.552 0 9.576 0.084 ;
    END
  END i[412]
  PIN i[413]
    DIRECTION INPUT ;
    USE SIGNAL ;
    PORT
      LAYER M5 ;
        RECT  9.648 0 9.672 0.084 ;
    END
  END i[413]
  PIN i[414]
    DIRECTION INPUT ;
    USE SIGNAL ;
    PORT
      LAYER M5 ;
        RECT  9.744 0 9.768 0.084 ;
    END
  END i[414]
  PIN i[415]
    DIRECTION INPUT ;
    USE SIGNAL ;
    PORT
      LAYER M5 ;
        RECT  9.84 0 9.864 0.084 ;
    END
  END i[415]
  PIN i[416]
    DIRECTION INPUT ;
    USE SIGNAL ;
    PORT
      LAYER M5 ;
        RECT  9.936 0 9.96 0.084 ;
    END
  END i[416]
  PIN i[417]
    DIRECTION INPUT ;
    USE SIGNAL ;
    PORT
      LAYER M5 ;
        RECT  10.032 0 10.056 0.084 ;
    END
  END i[417]
  PIN i[418]
    DIRECTION INPUT ;
    USE SIGNAL ;
    PORT
      LAYER M5 ;
        RECT  10.128 0 10.152 0.084 ;
    END
  END i[418]
  PIN i[419]
    DIRECTION INPUT ;
    USE SIGNAL ;
    PORT
      LAYER M5 ;
        RECT  10.224 0 10.248 0.084 ;
    END
  END i[419]
  PIN i[41]
    DIRECTION INPUT ;
    USE SIGNAL ;
    PORT
      LAYER M5 ;
        RECT  26.928 0 26.952 0.084 ;
    END
  END i[41]
  PIN i[420]
    DIRECTION INPUT ;
    USE SIGNAL ;
    PORT
      LAYER M5 ;
        RECT  10.32 0 10.344 0.084 ;
    END
  END i[420]
  PIN i[421]
    DIRECTION INPUT ;
    USE SIGNAL ;
    PORT
      LAYER M5 ;
        RECT  10.416 0 10.44 0.084 ;
    END
  END i[421]
  PIN i[422]
    DIRECTION INPUT ;
    USE SIGNAL ;
    PORT
      LAYER M5 ;
        RECT  10.512 0 10.536 0.084 ;
    END
  END i[422]
  PIN i[423]
    DIRECTION INPUT ;
    USE SIGNAL ;
    PORT
      LAYER M5 ;
        RECT  10.608 0 10.632 0.084 ;
    END
  END i[423]
  PIN i[424]
    DIRECTION INPUT ;
    USE SIGNAL ;
    PORT
      LAYER M5 ;
        RECT  10.704 0 10.728 0.084 ;
    END
  END i[424]
  PIN i[425]
    DIRECTION INPUT ;
    USE SIGNAL ;
    PORT
      LAYER M5 ;
        RECT  10.8 0 10.824 0.084 ;
    END
  END i[425]
  PIN i[426]
    DIRECTION INPUT ;
    USE SIGNAL ;
    PORT
      LAYER M5 ;
        RECT  10.896 0 10.92 0.084 ;
    END
  END i[426]
  PIN i[427]
    DIRECTION INPUT ;
    USE SIGNAL ;
    PORT
      LAYER M5 ;
        RECT  10.992 0 11.016 0.084 ;
    END
  END i[427]
  PIN i[428]
    DIRECTION INPUT ;
    USE SIGNAL ;
    PORT
      LAYER M5 ;
        RECT  11.088 0 11.112 0.084 ;
    END
  END i[428]
  PIN i[429]
    DIRECTION INPUT ;
    USE SIGNAL ;
    PORT
      LAYER M5 ;
        RECT  11.184 0 11.208 0.084 ;
    END
  END i[429]
  PIN i[42]
    DIRECTION INPUT ;
    USE SIGNAL ;
    PORT
      LAYER M5 ;
        RECT  27.024 0 27.048 0.084 ;
    END
  END i[42]
  PIN i[430]
    DIRECTION INPUT ;
    USE SIGNAL ;
    PORT
      LAYER M5 ;
        RECT  11.28 0 11.304 0.084 ;
    END
  END i[430]
  PIN i[431]
    DIRECTION INPUT ;
    USE SIGNAL ;
    PORT
      LAYER M5 ;
        RECT  11.376 0 11.4 0.084 ;
    END
  END i[431]
  PIN i[432]
    DIRECTION INPUT ;
    USE SIGNAL ;
    PORT
      LAYER M5 ;
        RECT  11.472 0 11.496 0.084 ;
    END
  END i[432]
  PIN i[433]
    DIRECTION INPUT ;
    USE SIGNAL ;
    PORT
      LAYER M5 ;
        RECT  11.568 0 11.592 0.084 ;
    END
  END i[433]
  PIN i[434]
    DIRECTION INPUT ;
    USE SIGNAL ;
    PORT
      LAYER M5 ;
        RECT  11.664 0 11.688 0.084 ;
    END
  END i[434]
  PIN i[435]
    DIRECTION INPUT ;
    USE SIGNAL ;
    PORT
      LAYER M5 ;
        RECT  11.76 0 11.784 0.084 ;
    END
  END i[435]
  PIN i[436]
    DIRECTION INPUT ;
    USE SIGNAL ;
    PORT
      LAYER M5 ;
        RECT  11.856 0 11.88 0.084 ;
    END
  END i[436]
  PIN i[437]
    DIRECTION INPUT ;
    USE SIGNAL ;
    PORT
      LAYER M5 ;
        RECT  11.952 0 11.976 0.084 ;
    END
  END i[437]
  PIN i[438]
    DIRECTION INPUT ;
    USE SIGNAL ;
    PORT
      LAYER M5 ;
        RECT  12.048 0 12.072 0.084 ;
    END
  END i[438]
  PIN i[439]
    DIRECTION INPUT ;
    USE SIGNAL ;
    PORT
      LAYER M5 ;
        RECT  12.144 0 12.168 0.084 ;
    END
  END i[439]
  PIN i[43]
    DIRECTION INPUT ;
    USE SIGNAL ;
    PORT
      LAYER M5 ;
        RECT  27.12 0 27.144 0.084 ;
    END
  END i[43]
  PIN i[440]
    DIRECTION INPUT ;
    USE SIGNAL ;
    PORT
      LAYER M5 ;
        RECT  12.24 0 12.264 0.084 ;
    END
  END i[440]
  PIN i[441]
    DIRECTION INPUT ;
    USE SIGNAL ;
    PORT
      LAYER M5 ;
        RECT  12.336 0 12.36 0.084 ;
    END
  END i[441]
  PIN i[442]
    DIRECTION INPUT ;
    USE SIGNAL ;
    PORT
      LAYER M5 ;
        RECT  12.432 0 12.456 0.084 ;
    END
  END i[442]
  PIN i[443]
    DIRECTION INPUT ;
    USE SIGNAL ;
    PORT
      LAYER M5 ;
        RECT  12.528 0 12.552 0.084 ;
    END
  END i[443]
  PIN i[444]
    DIRECTION INPUT ;
    USE SIGNAL ;
    PORT
      LAYER M5 ;
        RECT  12.624 0 12.648 0.084 ;
    END
  END i[444]
  PIN i[445]
    DIRECTION INPUT ;
    USE SIGNAL ;
    PORT
      LAYER M5 ;
        RECT  12.72 0 12.744 0.084 ;
    END
  END i[445]
  PIN i[446]
    DIRECTION INPUT ;
    USE SIGNAL ;
    PORT
      LAYER M5 ;
        RECT  12.816 0 12.84 0.084 ;
    END
  END i[446]
  PIN i[447]
    DIRECTION INPUT ;
    USE SIGNAL ;
    PORT
      LAYER M5 ;
        RECT  12.912 0 12.936 0.084 ;
    END
  END i[447]
  PIN i[448]
    DIRECTION INPUT ;
    USE SIGNAL ;
    PORT
      LAYER M5 ;
        RECT  39.12 0 39.144 0.084 ;
    END
  END i[448]
  PIN i[449]
    DIRECTION INPUT ;
    USE SIGNAL ;
    PORT
      LAYER M5 ;
        RECT  39.216 0 39.24 0.084 ;
    END
  END i[449]
  PIN i[44]
    DIRECTION INPUT ;
    USE SIGNAL ;
    PORT
      LAYER M5 ;
        RECT  27.216 0 27.24 0.084 ;
    END
  END i[44]
  PIN i[450]
    DIRECTION INPUT ;
    USE SIGNAL ;
    PORT
      LAYER M5 ;
        RECT  39.312 0 39.336 0.084 ;
    END
  END i[450]
  PIN i[451]
    DIRECTION INPUT ;
    USE SIGNAL ;
    PORT
      LAYER M5 ;
        RECT  39.408 0 39.432 0.084 ;
    END
  END i[451]
  PIN i[452]
    DIRECTION INPUT ;
    USE SIGNAL ;
    PORT
      LAYER M5 ;
        RECT  39.504 0 39.528 0.084 ;
    END
  END i[452]
  PIN i[453]
    DIRECTION INPUT ;
    USE SIGNAL ;
    PORT
      LAYER M5 ;
        RECT  39.6 0 39.624 0.084 ;
    END
  END i[453]
  PIN i[454]
    DIRECTION INPUT ;
    USE SIGNAL ;
    PORT
      LAYER M5 ;
        RECT  39.696 0 39.72 0.084 ;
    END
  END i[454]
  PIN i[455]
    DIRECTION INPUT ;
    USE SIGNAL ;
    PORT
      LAYER M5 ;
        RECT  39.792 0 39.816 0.084 ;
    END
  END i[455]
  PIN i[456]
    DIRECTION INPUT ;
    USE SIGNAL ;
    PORT
      LAYER M5 ;
        RECT  39.888 0 39.912 0.084 ;
    END
  END i[456]
  PIN i[457]
    DIRECTION INPUT ;
    USE SIGNAL ;
    PORT
      LAYER M5 ;
        RECT  39.984 0 40.008 0.084 ;
    END
  END i[457]
  PIN i[458]
    DIRECTION INPUT ;
    USE SIGNAL ;
    PORT
      LAYER M5 ;
        RECT  40.08 0 40.104 0.084 ;
    END
  END i[458]
  PIN i[459]
    DIRECTION INPUT ;
    USE SIGNAL ;
    PORT
      LAYER M5 ;
        RECT  40.176 0 40.2 0.084 ;
    END
  END i[459]
  PIN i[45]
    DIRECTION INPUT ;
    USE SIGNAL ;
    PORT
      LAYER M5 ;
        RECT  27.312 0 27.336 0.084 ;
    END
  END i[45]
  PIN i[460]
    DIRECTION INPUT ;
    USE SIGNAL ;
    PORT
      LAYER M5 ;
        RECT  40.272 0 40.296 0.084 ;
    END
  END i[460]
  PIN i[461]
    DIRECTION INPUT ;
    USE SIGNAL ;
    PORT
      LAYER M5 ;
        RECT  40.368 0 40.392 0.084 ;
    END
  END i[461]
  PIN i[462]
    DIRECTION INPUT ;
    USE SIGNAL ;
    PORT
      LAYER M5 ;
        RECT  40.464 0 40.488 0.084 ;
    END
  END i[462]
  PIN i[463]
    DIRECTION INPUT ;
    USE SIGNAL ;
    PORT
      LAYER M5 ;
        RECT  40.56 0 40.584 0.084 ;
    END
  END i[463]
  PIN i[464]
    DIRECTION INPUT ;
    USE SIGNAL ;
    PORT
      LAYER M5 ;
        RECT  40.656 0 40.68 0.084 ;
    END
  END i[464]
  PIN i[465]
    DIRECTION INPUT ;
    USE SIGNAL ;
    PORT
      LAYER M5 ;
        RECT  40.752 0 40.776 0.084 ;
    END
  END i[465]
  PIN i[466]
    DIRECTION INPUT ;
    USE SIGNAL ;
    PORT
      LAYER M5 ;
        RECT  40.848 0 40.872 0.084 ;
    END
  END i[466]
  PIN i[467]
    DIRECTION INPUT ;
    USE SIGNAL ;
    PORT
      LAYER M5 ;
        RECT  40.944 0 40.968 0.084 ;
    END
  END i[467]
  PIN i[468]
    DIRECTION INPUT ;
    USE SIGNAL ;
    PORT
      LAYER M5 ;
        RECT  41.04 0 41.064 0.084 ;
    END
  END i[468]
  PIN i[469]
    DIRECTION INPUT ;
    USE SIGNAL ;
    PORT
      LAYER M5 ;
        RECT  41.136 0 41.16 0.084 ;
    END
  END i[469]
  PIN i[46]
    DIRECTION INPUT ;
    USE SIGNAL ;
    PORT
      LAYER M5 ;
        RECT  27.408 0 27.432 0.084 ;
    END
  END i[46]
  PIN i[470]
    DIRECTION INPUT ;
    USE SIGNAL ;
    PORT
      LAYER M5 ;
        RECT  41.232 0 41.256 0.084 ;
    END
  END i[470]
  PIN i[471]
    DIRECTION INPUT ;
    USE SIGNAL ;
    PORT
      LAYER M5 ;
        RECT  41.328 0 41.352 0.084 ;
    END
  END i[471]
  PIN i[472]
    DIRECTION INPUT ;
    USE SIGNAL ;
    PORT
      LAYER M5 ;
        RECT  41.424 0 41.448 0.084 ;
    END
  END i[472]
  PIN i[473]
    DIRECTION INPUT ;
    USE SIGNAL ;
    PORT
      LAYER M5 ;
        RECT  41.52 0 41.544 0.084 ;
    END
  END i[473]
  PIN i[474]
    DIRECTION INPUT ;
    USE SIGNAL ;
    PORT
      LAYER M5 ;
        RECT  41.616 0 41.64 0.084 ;
    END
  END i[474]
  PIN i[475]
    DIRECTION INPUT ;
    USE SIGNAL ;
    PORT
      LAYER M5 ;
        RECT  41.712 0 41.736 0.084 ;
    END
  END i[475]
  PIN i[476]
    DIRECTION INPUT ;
    USE SIGNAL ;
    PORT
      LAYER M5 ;
        RECT  41.808 0 41.832 0.084 ;
    END
  END i[476]
  PIN i[477]
    DIRECTION INPUT ;
    USE SIGNAL ;
    PORT
      LAYER M5 ;
        RECT  41.904 0 41.928 0.084 ;
    END
  END i[477]
  PIN i[478]
    DIRECTION INPUT ;
    USE SIGNAL ;
    PORT
      LAYER M5 ;
        RECT  42 0 42.024 0.084 ;
    END
  END i[478]
  PIN i[479]
    DIRECTION INPUT ;
    USE SIGNAL ;
    PORT
      LAYER M5 ;
        RECT  42.096 0 42.12 0.084 ;
    END
  END i[479]
  PIN i[47]
    DIRECTION INPUT ;
    USE SIGNAL ;
    PORT
      LAYER M5 ;
        RECT  27.504 0 27.528 0.084 ;
    END
  END i[47]
  PIN i[480]
    DIRECTION INPUT ;
    USE SIGNAL ;
    PORT
      LAYER M5 ;
        RECT  42.192 0 42.216 0.084 ;
    END
  END i[480]
  PIN i[481]
    DIRECTION INPUT ;
    USE SIGNAL ;
    PORT
      LAYER M5 ;
        RECT  42.288 0 42.312 0.084 ;
    END
  END i[481]
  PIN i[482]
    DIRECTION INPUT ;
    USE SIGNAL ;
    PORT
      LAYER M5 ;
        RECT  42.384 0 42.408 0.084 ;
    END
  END i[482]
  PIN i[483]
    DIRECTION INPUT ;
    USE SIGNAL ;
    PORT
      LAYER M5 ;
        RECT  42.48 0 42.504 0.084 ;
    END
  END i[483]
  PIN i[484]
    DIRECTION INPUT ;
    USE SIGNAL ;
    PORT
      LAYER M5 ;
        RECT  42.576 0 42.6 0.084 ;
    END
  END i[484]
  PIN i[485]
    DIRECTION INPUT ;
    USE SIGNAL ;
    PORT
      LAYER M5 ;
        RECT  42.672 0 42.696 0.084 ;
    END
  END i[485]
  PIN i[486]
    DIRECTION INPUT ;
    USE SIGNAL ;
    PORT
      LAYER M5 ;
        RECT  42.768 0 42.792 0.084 ;
    END
  END i[486]
  PIN i[487]
    DIRECTION INPUT ;
    USE SIGNAL ;
    PORT
      LAYER M5 ;
        RECT  42.864 0 42.888 0.084 ;
    END
  END i[487]
  PIN i[488]
    DIRECTION INPUT ;
    USE SIGNAL ;
    PORT
      LAYER M5 ;
        RECT  42.96 0 42.984 0.084 ;
    END
  END i[488]
  PIN i[489]
    DIRECTION INPUT ;
    USE SIGNAL ;
    PORT
      LAYER M5 ;
        RECT  43.056 0 43.08 0.084 ;
    END
  END i[489]
  PIN i[48]
    DIRECTION INPUT ;
    USE SIGNAL ;
    PORT
      LAYER M5 ;
        RECT  27.6 0 27.624 0.084 ;
    END
  END i[48]
  PIN i[490]
    DIRECTION INPUT ;
    USE SIGNAL ;
    PORT
      LAYER M5 ;
        RECT  43.152 0 43.176 0.084 ;
    END
  END i[490]
  PIN i[491]
    DIRECTION INPUT ;
    USE SIGNAL ;
    PORT
      LAYER M5 ;
        RECT  43.248 0 43.272 0.084 ;
    END
  END i[491]
  PIN i[492]
    DIRECTION INPUT ;
    USE SIGNAL ;
    PORT
      LAYER M5 ;
        RECT  43.344 0 43.368 0.084 ;
    END
  END i[492]
  PIN i[493]
    DIRECTION INPUT ;
    USE SIGNAL ;
    PORT
      LAYER M5 ;
        RECT  43.44 0 43.464 0.084 ;
    END
  END i[493]
  PIN i[494]
    DIRECTION INPUT ;
    USE SIGNAL ;
    PORT
      LAYER M5 ;
        RECT  43.536 0 43.56 0.084 ;
    END
  END i[494]
  PIN i[495]
    DIRECTION INPUT ;
    USE SIGNAL ;
    PORT
      LAYER M5 ;
        RECT  43.632 0 43.656 0.084 ;
    END
  END i[495]
  PIN i[496]
    DIRECTION INPUT ;
    USE SIGNAL ;
    PORT
      LAYER M5 ;
        RECT  43.728 0 43.752 0.084 ;
    END
  END i[496]
  PIN i[497]
    DIRECTION INPUT ;
    USE SIGNAL ;
    PORT
      LAYER M5 ;
        RECT  43.824 0 43.848 0.084 ;
    END
  END i[497]
  PIN i[498]
    DIRECTION INPUT ;
    USE SIGNAL ;
    PORT
      LAYER M5 ;
        RECT  43.92 0 43.944 0.084 ;
    END
  END i[498]
  PIN i[499]
    DIRECTION INPUT ;
    USE SIGNAL ;
    PORT
      LAYER M5 ;
        RECT  44.016 0 44.04 0.084 ;
    END
  END i[499]
  PIN i[49]
    DIRECTION INPUT ;
    USE SIGNAL ;
    PORT
      LAYER M5 ;
        RECT  27.696 0 27.72 0.084 ;
    END
  END i[49]
  PIN i[4]
    DIRECTION INPUT ;
    USE SIGNAL ;
    PORT
      LAYER M5 ;
        RECT  35.664 0 35.688 0.084 ;
    END
  END i[4]
  PIN i[500]
    DIRECTION INPUT ;
    USE SIGNAL ;
    PORT
      LAYER M5 ;
        RECT  44.112 0 44.136 0.084 ;
    END
  END i[500]
  PIN i[501]
    DIRECTION INPUT ;
    USE SIGNAL ;
    PORT
      LAYER M5 ;
        RECT  44.208 0 44.232 0.084 ;
    END
  END i[501]
  PIN i[502]
    DIRECTION INPUT ;
    USE SIGNAL ;
    PORT
      LAYER M5 ;
        RECT  44.304 0 44.328 0.084 ;
    END
  END i[502]
  PIN i[503]
    DIRECTION INPUT ;
    USE SIGNAL ;
    PORT
      LAYER M5 ;
        RECT  44.4 0 44.424 0.084 ;
    END
  END i[503]
  PIN i[504]
    DIRECTION INPUT ;
    USE SIGNAL ;
    PORT
      LAYER M5 ;
        RECT  44.496 0 44.52 0.084 ;
    END
  END i[504]
  PIN i[505]
    DIRECTION INPUT ;
    USE SIGNAL ;
    PORT
      LAYER M5 ;
        RECT  44.592 0 44.616 0.084 ;
    END
  END i[505]
  PIN i[506]
    DIRECTION INPUT ;
    USE SIGNAL ;
    PORT
      LAYER M5 ;
        RECT  44.688 0 44.712 0.084 ;
    END
  END i[506]
  PIN i[507]
    DIRECTION INPUT ;
    USE SIGNAL ;
    PORT
      LAYER M5 ;
        RECT  44.784 0 44.808 0.084 ;
    END
  END i[507]
  PIN i[508]
    DIRECTION INPUT ;
    USE SIGNAL ;
    PORT
      LAYER M5 ;
        RECT  44.88 0 44.904 0.084 ;
    END
  END i[508]
  PIN i[509]
    DIRECTION INPUT ;
    USE SIGNAL ;
    PORT
      LAYER M5 ;
        RECT  44.976 0 45 0.084 ;
    END
  END i[509]
  PIN i[50]
    DIRECTION INPUT ;
    USE SIGNAL ;
    PORT
      LAYER M5 ;
        RECT  27.792 0 27.816 0.084 ;
    END
  END i[50]
  PIN i[510]
    DIRECTION INPUT ;
    USE SIGNAL ;
    PORT
      LAYER M5 ;
        RECT  45.072 0 45.096 0.084 ;
    END
  END i[510]
  PIN i[511]
    DIRECTION INPUT ;
    USE SIGNAL ;
    PORT
      LAYER M5 ;
        RECT  45.168 0 45.192 0.084 ;
    END
  END i[511]
  PIN i[512]
    DIRECTION INPUT ;
    USE SIGNAL ;
    PORT
      LAYER M5 ;
        RECT  45.264 0 45.288 0.084 ;
    END
  END i[512]
  PIN i[513]
    DIRECTION INPUT ;
    USE SIGNAL ;
    PORT
      LAYER M5 ;
        RECT  45.36 0 45.384 0.084 ;
    END
  END i[513]
  PIN i[514]
    DIRECTION INPUT ;
    USE SIGNAL ;
    PORT
      LAYER M5 ;
        RECT  45.456 0 45.48 0.084 ;
    END
  END i[514]
  PIN i[515]
    DIRECTION INPUT ;
    USE SIGNAL ;
    PORT
      LAYER M5 ;
        RECT  45.552 0 45.576 0.084 ;
    END
  END i[515]
  PIN i[516]
    DIRECTION INPUT ;
    USE SIGNAL ;
    PORT
      LAYER M5 ;
        RECT  45.648 0 45.672 0.084 ;
    END
  END i[516]
  PIN i[517]
    DIRECTION INPUT ;
    USE SIGNAL ;
    PORT
      LAYER M5 ;
        RECT  45.744 0 45.768 0.084 ;
    END
  END i[517]
  PIN i[518]
    DIRECTION INPUT ;
    USE SIGNAL ;
    PORT
      LAYER M5 ;
        RECT  45.84 0 45.864 0.084 ;
    END
  END i[518]
  PIN i[519]
    DIRECTION INPUT ;
    USE SIGNAL ;
    PORT
      LAYER M5 ;
        RECT  45.936 0 45.96 0.084 ;
    END
  END i[519]
  PIN i[51]
    DIRECTION INPUT ;
    USE SIGNAL ;
    PORT
      LAYER M5 ;
        RECT  27.888 0 27.912 0.084 ;
    END
  END i[51]
  PIN i[520]
    DIRECTION INPUT ;
    USE SIGNAL ;
    PORT
      LAYER M5 ;
        RECT  46.032 0 46.056 0.084 ;
    END
  END i[520]
  PIN i[521]
    DIRECTION INPUT ;
    USE SIGNAL ;
    PORT
      LAYER M5 ;
        RECT  46.128 0 46.152 0.084 ;
    END
  END i[521]
  PIN i[522]
    DIRECTION INPUT ;
    USE SIGNAL ;
    PORT
      LAYER M5 ;
        RECT  46.224 0 46.248 0.084 ;
    END
  END i[522]
  PIN i[523]
    DIRECTION INPUT ;
    USE SIGNAL ;
    PORT
      LAYER M5 ;
        RECT  46.32 0 46.344 0.084 ;
    END
  END i[523]
  PIN i[524]
    DIRECTION INPUT ;
    USE SIGNAL ;
    PORT
      LAYER M5 ;
        RECT  46.416 0 46.44 0.084 ;
    END
  END i[524]
  PIN i[525]
    DIRECTION INPUT ;
    USE SIGNAL ;
    PORT
      LAYER M5 ;
        RECT  46.512 0 46.536 0.084 ;
    END
  END i[525]
  PIN i[526]
    DIRECTION INPUT ;
    USE SIGNAL ;
    PORT
      LAYER M5 ;
        RECT  46.608 0 46.632 0.084 ;
    END
  END i[526]
  PIN i[527]
    DIRECTION INPUT ;
    USE SIGNAL ;
    PORT
      LAYER M5 ;
        RECT  46.704 0 46.728 0.084 ;
    END
  END i[527]
  PIN i[528]
    DIRECTION INPUT ;
    USE SIGNAL ;
    PORT
      LAYER M5 ;
        RECT  46.8 0 46.824 0.084 ;
    END
  END i[528]
  PIN i[529]
    DIRECTION INPUT ;
    USE SIGNAL ;
    PORT
      LAYER M5 ;
        RECT  46.896 0 46.92 0.084 ;
    END
  END i[529]
  PIN i[52]
    DIRECTION INPUT ;
    USE SIGNAL ;
    PORT
      LAYER M5 ;
        RECT  27.984 0 28.008 0.084 ;
    END
  END i[52]
  PIN i[530]
    DIRECTION INPUT ;
    USE SIGNAL ;
    PORT
      LAYER M5 ;
        RECT  46.992 0 47.016 0.084 ;
    END
  END i[530]
  PIN i[531]
    DIRECTION INPUT ;
    USE SIGNAL ;
    PORT
      LAYER M5 ;
        RECT  47.088 0 47.112 0.084 ;
    END
  END i[531]
  PIN i[532]
    DIRECTION INPUT ;
    USE SIGNAL ;
    PORT
      LAYER M5 ;
        RECT  47.184 0 47.208 0.084 ;
    END
  END i[532]
  PIN i[533]
    DIRECTION INPUT ;
    USE SIGNAL ;
    PORT
      LAYER M5 ;
        RECT  47.28 0 47.304 0.084 ;
    END
  END i[533]
  PIN i[534]
    DIRECTION INPUT ;
    USE SIGNAL ;
    PORT
      LAYER M5 ;
        RECT  47.376 0 47.4 0.084 ;
    END
  END i[534]
  PIN i[535]
    DIRECTION INPUT ;
    USE SIGNAL ;
    PORT
      LAYER M5 ;
        RECT  47.472 0 47.496 0.084 ;
    END
  END i[535]
  PIN i[536]
    DIRECTION INPUT ;
    USE SIGNAL ;
    PORT
      LAYER M5 ;
        RECT  47.568 0 47.592 0.084 ;
    END
  END i[536]
  PIN i[537]
    DIRECTION INPUT ;
    USE SIGNAL ;
    PORT
      LAYER M5 ;
        RECT  47.664 0 47.688 0.084 ;
    END
  END i[537]
  PIN i[538]
    DIRECTION INPUT ;
    USE SIGNAL ;
    PORT
      LAYER M5 ;
        RECT  47.76 0 47.784 0.084 ;
    END
  END i[538]
  PIN i[539]
    DIRECTION INPUT ;
    USE SIGNAL ;
    PORT
      LAYER M5 ;
        RECT  47.856 0 47.88 0.084 ;
    END
  END i[539]
  PIN i[53]
    DIRECTION INPUT ;
    USE SIGNAL ;
    PORT
      LAYER M5 ;
        RECT  28.08 0 28.104 0.084 ;
    END
  END i[53]
  PIN i[540]
    DIRECTION INPUT ;
    USE SIGNAL ;
    PORT
      LAYER M5 ;
        RECT  47.952 0 47.976 0.084 ;
    END
  END i[540]
  PIN i[541]
    DIRECTION INPUT ;
    USE SIGNAL ;
    PORT
      LAYER M5 ;
        RECT  48.048 0 48.072 0.084 ;
    END
  END i[541]
  PIN i[542]
    DIRECTION INPUT ;
    USE SIGNAL ;
    PORT
      LAYER M5 ;
        RECT  48.144 0 48.168 0.084 ;
    END
  END i[542]
  PIN i[543]
    DIRECTION INPUT ;
    USE SIGNAL ;
    PORT
      LAYER M5 ;
        RECT  48.24 0 48.264 0.084 ;
    END
  END i[543]
  PIN i[544]
    DIRECTION INPUT ;
    USE SIGNAL ;
    PORT
      LAYER M5 ;
        RECT  48.336 0 48.36 0.084 ;
    END
  END i[544]
  PIN i[545]
    DIRECTION INPUT ;
    USE SIGNAL ;
    PORT
      LAYER M5 ;
        RECT  48.432 0 48.456 0.084 ;
    END
  END i[545]
  PIN i[546]
    DIRECTION INPUT ;
    USE SIGNAL ;
    PORT
      LAYER M5 ;
        RECT  48.528 0 48.552 0.084 ;
    END
  END i[546]
  PIN i[547]
    DIRECTION INPUT ;
    USE SIGNAL ;
    PORT
      LAYER M5 ;
        RECT  48.624 0 48.648 0.084 ;
    END
  END i[547]
  PIN i[548]
    DIRECTION INPUT ;
    USE SIGNAL ;
    PORT
      LAYER M5 ;
        RECT  48.72 0 48.744 0.084 ;
    END
  END i[548]
  PIN i[549]
    DIRECTION INPUT ;
    USE SIGNAL ;
    PORT
      LAYER M5 ;
        RECT  48.816 0 48.84 0.084 ;
    END
  END i[549]
  PIN i[54]
    DIRECTION INPUT ;
    USE SIGNAL ;
    PORT
      LAYER M5 ;
        RECT  28.176 0 28.2 0.084 ;
    END
  END i[54]
  PIN i[550]
    DIRECTION INPUT ;
    USE SIGNAL ;
    PORT
      LAYER M5 ;
        RECT  48.912 0 48.936 0.084 ;
    END
  END i[550]
  PIN i[551]
    DIRECTION INPUT ;
    USE SIGNAL ;
    PORT
      LAYER M5 ;
        RECT  49.008 0 49.032 0.084 ;
    END
  END i[551]
  PIN i[552]
    DIRECTION INPUT ;
    USE SIGNAL ;
    PORT
      LAYER M5 ;
        RECT  49.104 0 49.128 0.084 ;
    END
  END i[552]
  PIN i[553]
    DIRECTION INPUT ;
    USE SIGNAL ;
    PORT
      LAYER M5 ;
        RECT  49.2 0 49.224 0.084 ;
    END
  END i[553]
  PIN i[554]
    DIRECTION INPUT ;
    USE SIGNAL ;
    PORT
      LAYER M5 ;
        RECT  49.296 0 49.32 0.084 ;
    END
  END i[554]
  PIN i[555]
    DIRECTION INPUT ;
    USE SIGNAL ;
    PORT
      LAYER M5 ;
        RECT  49.392 0 49.416 0.084 ;
    END
  END i[555]
  PIN i[556]
    DIRECTION INPUT ;
    USE SIGNAL ;
    PORT
      LAYER M5 ;
        RECT  49.488 0 49.512 0.084 ;
    END
  END i[556]
  PIN i[557]
    DIRECTION INPUT ;
    USE SIGNAL ;
    PORT
      LAYER M5 ;
        RECT  49.584 0 49.608 0.084 ;
    END
  END i[557]
  PIN i[558]
    DIRECTION INPUT ;
    USE SIGNAL ;
    PORT
      LAYER M5 ;
        RECT  49.68 0 49.704 0.084 ;
    END
  END i[558]
  PIN i[559]
    DIRECTION INPUT ;
    USE SIGNAL ;
    PORT
      LAYER M5 ;
        RECT  49.776 0 49.8 0.084 ;
    END
  END i[559]
  PIN i[55]
    DIRECTION INPUT ;
    USE SIGNAL ;
    PORT
      LAYER M5 ;
        RECT  28.272 0 28.296 0.084 ;
    END
  END i[55]
  PIN i[560]
    DIRECTION INPUT ;
    USE SIGNAL ;
    PORT
      LAYER M5 ;
        RECT  49.872 0 49.896 0.084 ;
    END
  END i[560]
  PIN i[561]
    DIRECTION INPUT ;
    USE SIGNAL ;
    PORT
      LAYER M5 ;
        RECT  49.968 0 49.992 0.084 ;
    END
  END i[561]
  PIN i[562]
    DIRECTION INPUT ;
    USE SIGNAL ;
    PORT
      LAYER M5 ;
        RECT  50.064 0 50.088 0.084 ;
    END
  END i[562]
  PIN i[563]
    DIRECTION INPUT ;
    USE SIGNAL ;
    PORT
      LAYER M5 ;
        RECT  50.16 0 50.184 0.084 ;
    END
  END i[563]
  PIN i[564]
    DIRECTION INPUT ;
    USE SIGNAL ;
    PORT
      LAYER M5 ;
        RECT  50.256 0 50.28 0.084 ;
    END
  END i[564]
  PIN i[565]
    DIRECTION INPUT ;
    USE SIGNAL ;
    PORT
      LAYER M5 ;
        RECT  50.352 0 50.376 0.084 ;
    END
  END i[565]
  PIN i[566]
    DIRECTION INPUT ;
    USE SIGNAL ;
    PORT
      LAYER M5 ;
        RECT  50.448 0 50.472 0.084 ;
    END
  END i[566]
  PIN i[567]
    DIRECTION INPUT ;
    USE SIGNAL ;
    PORT
      LAYER M5 ;
        RECT  50.544 0 50.568 0.084 ;
    END
  END i[567]
  PIN i[568]
    DIRECTION INPUT ;
    USE SIGNAL ;
    PORT
      LAYER M5 ;
        RECT  50.64 0 50.664 0.084 ;
    END
  END i[568]
  PIN i[569]
    DIRECTION INPUT ;
    USE SIGNAL ;
    PORT
      LAYER M5 ;
        RECT  50.736 0 50.76 0.084 ;
    END
  END i[569]
  PIN i[56]
    DIRECTION INPUT ;
    USE SIGNAL ;
    PORT
      LAYER M5 ;
        RECT  28.368 0 28.392 0.084 ;
    END
  END i[56]
  PIN i[570]
    DIRECTION INPUT ;
    USE SIGNAL ;
    PORT
      LAYER M5 ;
        RECT  50.832 0 50.856 0.084 ;
    END
  END i[570]
  PIN i[571]
    DIRECTION INPUT ;
    USE SIGNAL ;
    PORT
      LAYER M5 ;
        RECT  50.928 0 50.952 0.084 ;
    END
  END i[571]
  PIN i[572]
    DIRECTION INPUT ;
    USE SIGNAL ;
    PORT
      LAYER M5 ;
        RECT  51.024 0 51.048 0.084 ;
    END
  END i[572]
  PIN i[573]
    DIRECTION INPUT ;
    USE SIGNAL ;
    PORT
      LAYER M5 ;
        RECT  51.12 0 51.144 0.084 ;
    END
  END i[573]
  PIN i[574]
    DIRECTION INPUT ;
    USE SIGNAL ;
    PORT
      LAYER M5 ;
        RECT  51.216 0 51.24 0.084 ;
    END
  END i[574]
  PIN i[575]
    DIRECTION INPUT ;
    USE SIGNAL ;
    PORT
      LAYER M5 ;
        RECT  51.312 0 51.336 0.084 ;
    END
  END i[575]
  PIN i[576]
    DIRECTION INPUT ;
    USE SIGNAL ;
    PORT
      LAYER M5 ;
        RECT  58.32 0 58.344 0.084 ;
    END
  END i[576]
  PIN i[577]
    DIRECTION INPUT ;
    USE SIGNAL ;
    PORT
      LAYER M5 ;
        RECT  58.416 0 58.44 0.084 ;
    END
  END i[577]
  PIN i[578]
    DIRECTION INPUT ;
    USE SIGNAL ;
    PORT
      LAYER M5 ;
        RECT  58.512 0 58.536 0.084 ;
    END
  END i[578]
  PIN i[579]
    DIRECTION INPUT ;
    USE SIGNAL ;
    PORT
      LAYER M5 ;
        RECT  58.608 0 58.632 0.084 ;
    END
  END i[579]
  PIN i[57]
    DIRECTION INPUT ;
    USE SIGNAL ;
    PORT
      LAYER M5 ;
        RECT  28.464 0 28.488 0.084 ;
    END
  END i[57]
  PIN i[580]
    DIRECTION INPUT ;
    USE SIGNAL ;
    PORT
      LAYER M5 ;
        RECT  58.704 0 58.728 0.084 ;
    END
  END i[580]
  PIN i[581]
    DIRECTION INPUT ;
    USE SIGNAL ;
    PORT
      LAYER M5 ;
        RECT  58.8 0 58.824 0.084 ;
    END
  END i[581]
  PIN i[582]
    DIRECTION INPUT ;
    USE SIGNAL ;
    PORT
      LAYER M5 ;
        RECT  58.896 0 58.92 0.084 ;
    END
  END i[582]
  PIN i[583]
    DIRECTION INPUT ;
    USE SIGNAL ;
    PORT
      LAYER M5 ;
        RECT  58.992 0 59.016 0.084 ;
    END
  END i[583]
  PIN i[584]
    DIRECTION INPUT ;
    USE SIGNAL ;
    PORT
      LAYER M5 ;
        RECT  59.088 0 59.112 0.084 ;
    END
  END i[584]
  PIN i[585]
    DIRECTION INPUT ;
    USE SIGNAL ;
    PORT
      LAYER M5 ;
        RECT  59.184 0 59.208 0.084 ;
    END
  END i[585]
  PIN i[586]
    DIRECTION INPUT ;
    USE SIGNAL ;
    PORT
      LAYER M5 ;
        RECT  59.28 0 59.304 0.084 ;
    END
  END i[586]
  PIN i[587]
    DIRECTION INPUT ;
    USE SIGNAL ;
    PORT
      LAYER M5 ;
        RECT  59.376 0 59.4 0.084 ;
    END
  END i[587]
  PIN i[588]
    DIRECTION INPUT ;
    USE SIGNAL ;
    PORT
      LAYER M5 ;
        RECT  59.472 0 59.496 0.084 ;
    END
  END i[588]
  PIN i[589]
    DIRECTION INPUT ;
    USE SIGNAL ;
    PORT
      LAYER M5 ;
        RECT  59.568 0 59.592 0.084 ;
    END
  END i[589]
  PIN i[58]
    DIRECTION INPUT ;
    USE SIGNAL ;
    PORT
      LAYER M5 ;
        RECT  28.56 0 28.584 0.084 ;
    END
  END i[58]
  PIN i[590]
    DIRECTION INPUT ;
    USE SIGNAL ;
    PORT
      LAYER M5 ;
        RECT  59.664 0 59.688 0.084 ;
    END
  END i[590]
  PIN i[591]
    DIRECTION INPUT ;
    USE SIGNAL ;
    PORT
      LAYER M5 ;
        RECT  59.76 0 59.784 0.084 ;
    END
  END i[591]
  PIN i[592]
    DIRECTION INPUT ;
    USE SIGNAL ;
    PORT
      LAYER M5 ;
        RECT  59.856 0 59.88 0.084 ;
    END
  END i[592]
  PIN i[593]
    DIRECTION INPUT ;
    USE SIGNAL ;
    PORT
      LAYER M5 ;
        RECT  59.952 0 59.976 0.084 ;
    END
  END i[593]
  PIN i[594]
    DIRECTION INPUT ;
    USE SIGNAL ;
    PORT
      LAYER M5 ;
        RECT  60.048 0 60.072 0.084 ;
    END
  END i[594]
  PIN i[595]
    DIRECTION INPUT ;
    USE SIGNAL ;
    PORT
      LAYER M5 ;
        RECT  60.144 0 60.168 0.084 ;
    END
  END i[595]
  PIN i[596]
    DIRECTION INPUT ;
    USE SIGNAL ;
    PORT
      LAYER M5 ;
        RECT  60.24 0 60.264 0.084 ;
    END
  END i[596]
  PIN i[597]
    DIRECTION INPUT ;
    USE SIGNAL ;
    PORT
      LAYER M5 ;
        RECT  60.336 0 60.36 0.084 ;
    END
  END i[597]
  PIN i[598]
    DIRECTION INPUT ;
    USE SIGNAL ;
    PORT
      LAYER M5 ;
        RECT  60.432 0 60.456 0.084 ;
    END
  END i[598]
  PIN i[599]
    DIRECTION INPUT ;
    USE SIGNAL ;
    PORT
      LAYER M5 ;
        RECT  60.528 0 60.552 0.084 ;
    END
  END i[599]
  PIN i[59]
    DIRECTION INPUT ;
    USE SIGNAL ;
    PORT
      LAYER M5 ;
        RECT  28.656 0 28.68 0.084 ;
    END
  END i[59]
  PIN i[5]
    DIRECTION INPUT ;
    USE SIGNAL ;
    PORT
      LAYER M5 ;
        RECT  35.76 0 35.784 0.084 ;
    END
  END i[5]
  PIN i[600]
    DIRECTION INPUT ;
    USE SIGNAL ;
    PORT
      LAYER M5 ;
        RECT  60.624 0 60.648 0.084 ;
    END
  END i[600]
  PIN i[601]
    DIRECTION INPUT ;
    USE SIGNAL ;
    PORT
      LAYER M5 ;
        RECT  60.72 0 60.744 0.084 ;
    END
  END i[601]
  PIN i[602]
    DIRECTION INPUT ;
    USE SIGNAL ;
    PORT
      LAYER M5 ;
        RECT  60.816 0 60.84 0.084 ;
    END
  END i[602]
  PIN i[603]
    DIRECTION INPUT ;
    USE SIGNAL ;
    PORT
      LAYER M5 ;
        RECT  60.912 0 60.936 0.084 ;
    END
  END i[603]
  PIN i[604]
    DIRECTION INPUT ;
    USE SIGNAL ;
    PORT
      LAYER M5 ;
        RECT  61.008 0 61.032 0.084 ;
    END
  END i[604]
  PIN i[605]
    DIRECTION INPUT ;
    USE SIGNAL ;
    PORT
      LAYER M5 ;
        RECT  61.104 0 61.128 0.084 ;
    END
  END i[605]
  PIN i[606]
    DIRECTION INPUT ;
    USE SIGNAL ;
    PORT
      LAYER M5 ;
        RECT  61.2 0 61.224 0.084 ;
    END
  END i[606]
  PIN i[607]
    DIRECTION INPUT ;
    USE SIGNAL ;
    PORT
      LAYER M5 ;
        RECT  61.296 0 61.32 0.084 ;
    END
  END i[607]
  PIN i[608]
    DIRECTION INPUT ;
    USE SIGNAL ;
    PORT
      LAYER M5 ;
        RECT  61.392 0 61.416 0.084 ;
    END
  END i[608]
  PIN i[609]
    DIRECTION INPUT ;
    USE SIGNAL ;
    PORT
      LAYER M5 ;
        RECT  61.488 0 61.512 0.084 ;
    END
  END i[609]
  PIN i[60]
    DIRECTION INPUT ;
    USE SIGNAL ;
    PORT
      LAYER M5 ;
        RECT  28.752 0 28.776 0.084 ;
    END
  END i[60]
  PIN i[610]
    DIRECTION INPUT ;
    USE SIGNAL ;
    PORT
      LAYER M5 ;
        RECT  61.584 0 61.608 0.084 ;
    END
  END i[610]
  PIN i[611]
    DIRECTION INPUT ;
    USE SIGNAL ;
    PORT
      LAYER M5 ;
        RECT  61.68 0 61.704 0.084 ;
    END
  END i[611]
  PIN i[612]
    DIRECTION INPUT ;
    USE SIGNAL ;
    PORT
      LAYER M5 ;
        RECT  61.776 0 61.8 0.084 ;
    END
  END i[612]
  PIN i[613]
    DIRECTION INPUT ;
    USE SIGNAL ;
    PORT
      LAYER M5 ;
        RECT  61.872 0 61.896 0.084 ;
    END
  END i[613]
  PIN i[614]
    DIRECTION INPUT ;
    USE SIGNAL ;
    PORT
      LAYER M5 ;
        RECT  61.968 0 61.992 0.084 ;
    END
  END i[614]
  PIN i[615]
    DIRECTION INPUT ;
    USE SIGNAL ;
    PORT
      LAYER M5 ;
        RECT  62.064 0 62.088 0.084 ;
    END
  END i[615]
  PIN i[616]
    DIRECTION INPUT ;
    USE SIGNAL ;
    PORT
      LAYER M5 ;
        RECT  62.16 0 62.184 0.084 ;
    END
  END i[616]
  PIN i[617]
    DIRECTION INPUT ;
    USE SIGNAL ;
    PORT
      LAYER M5 ;
        RECT  62.256 0 62.28 0.084 ;
    END
  END i[617]
  PIN i[618]
    DIRECTION INPUT ;
    USE SIGNAL ;
    PORT
      LAYER M5 ;
        RECT  62.352 0 62.376 0.084 ;
    END
  END i[618]
  PIN i[619]
    DIRECTION INPUT ;
    USE SIGNAL ;
    PORT
      LAYER M5 ;
        RECT  62.448 0 62.472 0.084 ;
    END
  END i[619]
  PIN i[61]
    DIRECTION INPUT ;
    USE SIGNAL ;
    PORT
      LAYER M5 ;
        RECT  28.848 0 28.872 0.084 ;
    END
  END i[61]
  PIN i[620]
    DIRECTION INPUT ;
    USE SIGNAL ;
    PORT
      LAYER M5 ;
        RECT  62.544 0 62.568 0.084 ;
    END
  END i[620]
  PIN i[621]
    DIRECTION INPUT ;
    USE SIGNAL ;
    PORT
      LAYER M5 ;
        RECT  62.64 0 62.664 0.084 ;
    END
  END i[621]
  PIN i[622]
    DIRECTION INPUT ;
    USE SIGNAL ;
    PORT
      LAYER M5 ;
        RECT  62.736 0 62.76 0.084 ;
    END
  END i[622]
  PIN i[623]
    DIRECTION INPUT ;
    USE SIGNAL ;
    PORT
      LAYER M5 ;
        RECT  62.832 0 62.856 0.084 ;
    END
  END i[623]
  PIN i[62]
    DIRECTION INPUT ;
    USE SIGNAL ;
    PORT
      LAYER M5 ;
        RECT  28.944 0 28.968 0.084 ;
    END
  END i[62]
  PIN i[63]
    DIRECTION INPUT ;
    USE SIGNAL ;
    PORT
      LAYER M5 ;
        RECT  29.04 0 29.064 0.084 ;
    END
  END i[63]
  PIN i[64]
    DIRECTION INPUT ;
    USE SIGNAL ;
    PORT
      LAYER M5 ;
        RECT  32.208 0 32.232 0.084 ;
    END
  END i[64]
  PIN i[65]
    DIRECTION INPUT ;
    USE SIGNAL ;
    PORT
      LAYER M5 ;
        RECT  32.304 0 32.328 0.084 ;
    END
  END i[65]
  PIN i[66]
    DIRECTION INPUT ;
    USE SIGNAL ;
    PORT
      LAYER M5 ;
        RECT  32.4 0 32.424 0.084 ;
    END
  END i[66]
  PIN i[67]
    DIRECTION INPUT ;
    USE SIGNAL ;
    PORT
      LAYER M5 ;
        RECT  32.496 0 32.52 0.084 ;
    END
  END i[67]
  PIN i[68]
    DIRECTION INPUT ;
    USE SIGNAL ;
    PORT
      LAYER M5 ;
        RECT  32.592 0 32.616 0.084 ;
    END
  END i[68]
  PIN i[69]
    DIRECTION INPUT ;
    USE SIGNAL ;
    PORT
      LAYER M5 ;
        RECT  32.688 0 32.712 0.084 ;
    END
  END i[69]
  PIN i[6]
    DIRECTION INPUT ;
    USE SIGNAL ;
    PORT
      LAYER M5 ;
        RECT  35.856 0 35.88 0.084 ;
    END
  END i[6]
  PIN i[70]
    DIRECTION INPUT ;
    USE SIGNAL ;
    PORT
      LAYER M5 ;
        RECT  32.784 0 32.808 0.084 ;
    END
  END i[70]
  PIN i[71]
    DIRECTION INPUT ;
    USE SIGNAL ;
    PORT
      LAYER M5 ;
        RECT  32.88 0 32.904 0.084 ;
    END
  END i[71]
  PIN i[72]
    DIRECTION INPUT ;
    USE SIGNAL ;
    PORT
      LAYER M5 ;
        RECT  32.976 0 33 0.084 ;
    END
  END i[72]
  PIN i[73]
    DIRECTION INPUT ;
    USE SIGNAL ;
    PORT
      LAYER M5 ;
        RECT  33.072 0 33.096 0.084 ;
    END
  END i[73]
  PIN i[74]
    DIRECTION INPUT ;
    USE SIGNAL ;
    PORT
      LAYER M5 ;
        RECT  33.168 0 33.192 0.084 ;
    END
  END i[74]
  PIN i[75]
    DIRECTION INPUT ;
    USE SIGNAL ;
    PORT
      LAYER M5 ;
        RECT  33.264 0 33.288 0.084 ;
    END
  END i[75]
  PIN i[76]
    DIRECTION INPUT ;
    USE SIGNAL ;
    PORT
      LAYER M5 ;
        RECT  33.36 0 33.384 0.084 ;
    END
  END i[76]
  PIN i[77]
    DIRECTION INPUT ;
    USE SIGNAL ;
    PORT
      LAYER M5 ;
        RECT  33.456 0 33.48 0.084 ;
    END
  END i[77]
  PIN i[78]
    DIRECTION INPUT ;
    USE SIGNAL ;
    PORT
      LAYER M5 ;
        RECT  33.552 0 33.576 0.084 ;
    END
  END i[78]
  PIN i[79]
    DIRECTION INPUT ;
    USE SIGNAL ;
    PORT
      LAYER M5 ;
        RECT  33.648 0 33.672 0.084 ;
    END
  END i[79]
  PIN i[7]
    DIRECTION INPUT ;
    USE SIGNAL ;
    PORT
      LAYER M5 ;
        RECT  35.952 0 35.976 0.084 ;
    END
  END i[7]
  PIN i[80]
    DIRECTION INPUT ;
    USE SIGNAL ;
    PORT
      LAYER M5 ;
        RECT  33.744 0 33.768 0.084 ;
    END
  END i[80]
  PIN i[81]
    DIRECTION INPUT ;
    USE SIGNAL ;
    PORT
      LAYER M5 ;
        RECT  33.84 0 33.864 0.084 ;
    END
  END i[81]
  PIN i[82]
    DIRECTION INPUT ;
    USE SIGNAL ;
    PORT
      LAYER M5 ;
        RECT  33.936 0 33.96 0.084 ;
    END
  END i[82]
  PIN i[83]
    DIRECTION INPUT ;
    USE SIGNAL ;
    PORT
      LAYER M5 ;
        RECT  34.032 0 34.056 0.084 ;
    END
  END i[83]
  PIN i[84]
    DIRECTION INPUT ;
    USE SIGNAL ;
    PORT
      LAYER M5 ;
        RECT  34.128 0 34.152 0.084 ;
    END
  END i[84]
  PIN i[85]
    DIRECTION INPUT ;
    USE SIGNAL ;
    PORT
      LAYER M5 ;
        RECT  34.224 0 34.248 0.084 ;
    END
  END i[85]
  PIN i[86]
    DIRECTION INPUT ;
    USE SIGNAL ;
    PORT
      LAYER M5 ;
        RECT  34.32 0 34.344 0.084 ;
    END
  END i[86]
  PIN i[87]
    DIRECTION INPUT ;
    USE SIGNAL ;
    PORT
      LAYER M5 ;
        RECT  34.416 0 34.44 0.084 ;
    END
  END i[87]
  PIN i[88]
    DIRECTION INPUT ;
    USE SIGNAL ;
    PORT
      LAYER M5 ;
        RECT  34.512 0 34.536 0.084 ;
    END
  END i[88]
  PIN i[89]
    DIRECTION INPUT ;
    USE SIGNAL ;
    PORT
      LAYER M5 ;
        RECT  34.608 0 34.632 0.084 ;
    END
  END i[89]
  PIN i[8]
    DIRECTION INPUT ;
    USE SIGNAL ;
    PORT
      LAYER M5 ;
        RECT  36.048 0 36.072 0.084 ;
    END
  END i[8]
  PIN i[90]
    DIRECTION INPUT ;
    USE SIGNAL ;
    PORT
      LAYER M5 ;
        RECT  34.704 0 34.728 0.084 ;
    END
  END i[90]
  PIN i[91]
    DIRECTION INPUT ;
    USE SIGNAL ;
    PORT
      LAYER M5 ;
        RECT  34.8 0 34.824 0.084 ;
    END
  END i[91]
  PIN i[92]
    DIRECTION INPUT ;
    USE SIGNAL ;
    PORT
      LAYER M5 ;
        RECT  34.896 0 34.92 0.084 ;
    END
  END i[92]
  PIN i[93]
    DIRECTION INPUT ;
    USE SIGNAL ;
    PORT
      LAYER M5 ;
        RECT  34.992 0 35.016 0.084 ;
    END
  END i[93]
  PIN i[94]
    DIRECTION INPUT ;
    USE SIGNAL ;
    PORT
      LAYER M5 ;
        RECT  35.088 0 35.112 0.084 ;
    END
  END i[94]
  PIN i[95]
    DIRECTION INPUT ;
    USE SIGNAL ;
    PORT
      LAYER M5 ;
        RECT  35.184 0 35.208 0.084 ;
    END
  END i[95]
  PIN i[96]
    DIRECTION INPUT ;
    USE SIGNAL ;
    PORT
      LAYER M5 ;
        RECT  29.136 0 29.16 0.084 ;
    END
  END i[96]
  PIN i[97]
    DIRECTION INPUT ;
    USE SIGNAL ;
    PORT
      LAYER M5 ;
        RECT  29.232 0 29.256 0.084 ;
    END
  END i[97]
  PIN i[98]
    DIRECTION INPUT ;
    USE SIGNAL ;
    PORT
      LAYER M5 ;
        RECT  29.328 0 29.352 0.084 ;
    END
  END i[98]
  PIN i[99]
    DIRECTION INPUT ;
    USE SIGNAL ;
    PORT
      LAYER M5 ;
        RECT  29.424 0 29.448 0.084 ;
    END
  END i[99]
  PIN i[9]
    DIRECTION INPUT ;
    USE SIGNAL ;
    PORT
      LAYER M5 ;
        RECT  36.144 0 36.168 0.084 ;
    END
  END i[9]
  PIN o[0]
    DIRECTION OUTPUT ;
    USE SIGNAL ;
    PORT
      LAYER M5 ;
        RECT  35.664 23.676 35.688 23.76 ;
    END
  END o[0]
  PIN o[100]
    DIRECTION OUTPUT ;
    USE SIGNAL ;
    PORT
      LAYER M5 ;
        RECT  39.12 23.676 39.144 23.76 ;
    END
  END o[100]
  PIN o[101]
    DIRECTION OUTPUT ;
    USE SIGNAL ;
    PORT
      LAYER M5 ;
        RECT  39.216 23.676 39.24 23.76 ;
    END
  END o[101]
  PIN o[102]
    DIRECTION OUTPUT ;
    USE SIGNAL ;
    PORT
      LAYER M5 ;
        RECT  39.312 23.676 39.336 23.76 ;
    END
  END o[102]
  PIN o[103]
    DIRECTION OUTPUT ;
    USE SIGNAL ;
    PORT
      LAYER M5 ;
        RECT  39.408 23.676 39.432 23.76 ;
    END
  END o[103]
  PIN o[104]
    DIRECTION OUTPUT ;
    USE SIGNAL ;
    PORT
      LAYER M5 ;
        RECT  39.504 23.676 39.528 23.76 ;
    END
  END o[104]
  PIN o[105]
    DIRECTION OUTPUT ;
    USE SIGNAL ;
    PORT
      LAYER M5 ;
        RECT  39.6 23.676 39.624 23.76 ;
    END
  END o[105]
  PIN o[106]
    DIRECTION OUTPUT ;
    USE SIGNAL ;
    PORT
      LAYER M5 ;
        RECT  39.696 23.676 39.72 23.76 ;
    END
  END o[106]
  PIN o[107]
    DIRECTION OUTPUT ;
    USE SIGNAL ;
    PORT
      LAYER M5 ;
        RECT  39.792 23.676 39.816 23.76 ;
    END
  END o[107]
  PIN o[108]
    DIRECTION OUTPUT ;
    USE SIGNAL ;
    PORT
      LAYER M5 ;
        RECT  39.888 23.676 39.912 23.76 ;
    END
  END o[108]
  PIN o[109]
    DIRECTION OUTPUT ;
    USE SIGNAL ;
    PORT
      LAYER M5 ;
        RECT  39.984 23.676 40.008 23.76 ;
    END
  END o[109]
  PIN o[10]
    DIRECTION OUTPUT ;
    USE SIGNAL ;
    PORT
      LAYER M5 ;
        RECT  36.624 23.676 36.648 23.76 ;
    END
  END o[10]
  PIN o[110]
    DIRECTION OUTPUT ;
    USE SIGNAL ;
    PORT
      LAYER M5 ;
        RECT  40.08 23.676 40.104 23.76 ;
    END
  END o[110]
  PIN o[111]
    DIRECTION OUTPUT ;
    USE SIGNAL ;
    PORT
      LAYER M5 ;
        RECT  40.176 23.676 40.2 23.76 ;
    END
  END o[111]
  PIN o[112]
    DIRECTION OUTPUT ;
    USE SIGNAL ;
    PORT
      LAYER M5 ;
        RECT  40.272 23.676 40.296 23.76 ;
    END
  END o[112]
  PIN o[113]
    DIRECTION OUTPUT ;
    USE SIGNAL ;
    PORT
      LAYER M5 ;
        RECT  40.368 23.676 40.392 23.76 ;
    END
  END o[113]
  PIN o[114]
    DIRECTION OUTPUT ;
    USE SIGNAL ;
    PORT
      LAYER M5 ;
        RECT  40.464 23.676 40.488 23.76 ;
    END
  END o[114]
  PIN o[115]
    DIRECTION OUTPUT ;
    USE SIGNAL ;
    PORT
      LAYER M5 ;
        RECT  40.56 23.676 40.584 23.76 ;
    END
  END o[115]
  PIN o[116]
    DIRECTION OUTPUT ;
    USE SIGNAL ;
    PORT
      LAYER M5 ;
        RECT  40.656 23.676 40.68 23.76 ;
    END
  END o[116]
  PIN o[117]
    DIRECTION OUTPUT ;
    USE SIGNAL ;
    PORT
      LAYER M5 ;
        RECT  40.752 23.676 40.776 23.76 ;
    END
  END o[117]
  PIN o[118]
    DIRECTION OUTPUT ;
    USE SIGNAL ;
    PORT
      LAYER M5 ;
        RECT  40.848 23.676 40.872 23.76 ;
    END
  END o[118]
  PIN o[119]
    DIRECTION OUTPUT ;
    USE SIGNAL ;
    PORT
      LAYER M5 ;
        RECT  40.944 23.676 40.968 23.76 ;
    END
  END o[119]
  PIN o[11]
    DIRECTION OUTPUT ;
    USE SIGNAL ;
    PORT
      LAYER M5 ;
        RECT  36.72 23.676 36.744 23.76 ;
    END
  END o[11]
  PIN o[120]
    DIRECTION OUTPUT ;
    USE SIGNAL ;
    PORT
      LAYER M5 ;
        RECT  41.04 23.676 41.064 23.76 ;
    END
  END o[120]
  PIN o[121]
    DIRECTION OUTPUT ;
    USE SIGNAL ;
    PORT
      LAYER M5 ;
        RECT  41.136 23.676 41.16 23.76 ;
    END
  END o[121]
  PIN o[122]
    DIRECTION OUTPUT ;
    USE SIGNAL ;
    PORT
      LAYER M5 ;
        RECT  41.232 23.676 41.256 23.76 ;
    END
  END o[122]
  PIN o[123]
    DIRECTION OUTPUT ;
    USE SIGNAL ;
    PORT
      LAYER M5 ;
        RECT  41.328 23.676 41.352 23.76 ;
    END
  END o[123]
  PIN o[124]
    DIRECTION OUTPUT ;
    USE SIGNAL ;
    PORT
      LAYER M5 ;
        RECT  41.424 23.676 41.448 23.76 ;
    END
  END o[124]
  PIN o[125]
    DIRECTION OUTPUT ;
    USE SIGNAL ;
    PORT
      LAYER M5 ;
        RECT  41.52 23.676 41.544 23.76 ;
    END
  END o[125]
  PIN o[126]
    DIRECTION OUTPUT ;
    USE SIGNAL ;
    PORT
      LAYER M5 ;
        RECT  41.616 23.676 41.64 23.76 ;
    END
  END o[126]
  PIN o[127]
    DIRECTION OUTPUT ;
    USE SIGNAL ;
    PORT
      LAYER M5 ;
        RECT  41.712 23.676 41.736 23.76 ;
    END
  END o[127]
  PIN o[128]
    DIRECTION OUTPUT ;
    USE SIGNAL ;
    PORT
      LAYER M5 ;
        RECT  26.448 23.676 26.472 23.76 ;
    END
  END o[128]
  PIN o[129]
    DIRECTION OUTPUT ;
    USE SIGNAL ;
    PORT
      LAYER M5 ;
        RECT  26.544 23.676 26.568 23.76 ;
    END
  END o[129]
  PIN o[12]
    DIRECTION OUTPUT ;
    USE SIGNAL ;
    PORT
      LAYER M5 ;
        RECT  36.816 23.676 36.84 23.76 ;
    END
  END o[12]
  PIN o[130]
    DIRECTION OUTPUT ;
    USE SIGNAL ;
    PORT
      LAYER M5 ;
        RECT  26.64 23.676 26.664 23.76 ;
    END
  END o[130]
  PIN o[131]
    DIRECTION OUTPUT ;
    USE SIGNAL ;
    PORT
      LAYER M5 ;
        RECT  26.736 23.676 26.76 23.76 ;
    END
  END o[131]
  PIN o[132]
    DIRECTION OUTPUT ;
    USE SIGNAL ;
    PORT
      LAYER M5 ;
        RECT  26.832 23.676 26.856 23.76 ;
    END
  END o[132]
  PIN o[133]
    DIRECTION OUTPUT ;
    USE SIGNAL ;
    PORT
      LAYER M5 ;
        RECT  26.928 23.676 26.952 23.76 ;
    END
  END o[133]
  PIN o[134]
    DIRECTION OUTPUT ;
    USE SIGNAL ;
    PORT
      LAYER M5 ;
        RECT  27.024 23.676 27.048 23.76 ;
    END
  END o[134]
  PIN o[135]
    DIRECTION OUTPUT ;
    USE SIGNAL ;
    PORT
      LAYER M5 ;
        RECT  27.12 23.676 27.144 23.76 ;
    END
  END o[135]
  PIN o[136]
    DIRECTION OUTPUT ;
    USE SIGNAL ;
    PORT
      LAYER M5 ;
        RECT  27.216 23.676 27.24 23.76 ;
    END
  END o[136]
  PIN o[137]
    DIRECTION OUTPUT ;
    USE SIGNAL ;
    PORT
      LAYER M5 ;
        RECT  27.312 23.676 27.336 23.76 ;
    END
  END o[137]
  PIN o[138]
    DIRECTION OUTPUT ;
    USE SIGNAL ;
    PORT
      LAYER M5 ;
        RECT  27.408 23.676 27.432 23.76 ;
    END
  END o[138]
  PIN o[139]
    DIRECTION OUTPUT ;
    USE SIGNAL ;
    PORT
      LAYER M5 ;
        RECT  27.504 23.676 27.528 23.76 ;
    END
  END o[139]
  PIN o[13]
    DIRECTION OUTPUT ;
    USE SIGNAL ;
    PORT
      LAYER M5 ;
        RECT  36.912 23.676 36.936 23.76 ;
    END
  END o[13]
  PIN o[140]
    DIRECTION OUTPUT ;
    USE SIGNAL ;
    PORT
      LAYER M5 ;
        RECT  27.6 23.676 27.624 23.76 ;
    END
  END o[140]
  PIN o[141]
    DIRECTION OUTPUT ;
    USE SIGNAL ;
    PORT
      LAYER M5 ;
        RECT  27.696 23.676 27.72 23.76 ;
    END
  END o[141]
  PIN o[142]
    DIRECTION OUTPUT ;
    USE SIGNAL ;
    PORT
      LAYER M5 ;
        RECT  27.792 23.676 27.816 23.76 ;
    END
  END o[142]
  PIN o[143]
    DIRECTION OUTPUT ;
    USE SIGNAL ;
    PORT
      LAYER M5 ;
        RECT  27.888 23.676 27.912 23.76 ;
    END
  END o[143]
  PIN o[144]
    DIRECTION OUTPUT ;
    USE SIGNAL ;
    PORT
      LAYER M5 ;
        RECT  27.984 23.676 28.008 23.76 ;
    END
  END o[144]
  PIN o[145]
    DIRECTION OUTPUT ;
    USE SIGNAL ;
    PORT
      LAYER M5 ;
        RECT  28.08 23.676 28.104 23.76 ;
    END
  END o[145]
  PIN o[146]
    DIRECTION OUTPUT ;
    USE SIGNAL ;
    PORT
      LAYER M5 ;
        RECT  28.176 23.676 28.2 23.76 ;
    END
  END o[146]
  PIN o[147]
    DIRECTION OUTPUT ;
    USE SIGNAL ;
    PORT
      LAYER M5 ;
        RECT  28.272 23.676 28.296 23.76 ;
    END
  END o[147]
  PIN o[148]
    DIRECTION OUTPUT ;
    USE SIGNAL ;
    PORT
      LAYER M5 ;
        RECT  28.368 23.676 28.392 23.76 ;
    END
  END o[148]
  PIN o[149]
    DIRECTION OUTPUT ;
    USE SIGNAL ;
    PORT
      LAYER M5 ;
        RECT  28.464 23.676 28.488 23.76 ;
    END
  END o[149]
  PIN o[14]
    DIRECTION OUTPUT ;
    USE SIGNAL ;
    PORT
      LAYER M5 ;
        RECT  37.008 23.676 37.032 23.76 ;
    END
  END o[14]
  PIN o[150]
    DIRECTION OUTPUT ;
    USE SIGNAL ;
    PORT
      LAYER M5 ;
        RECT  28.56 23.676 28.584 23.76 ;
    END
  END o[150]
  PIN o[151]
    DIRECTION OUTPUT ;
    USE SIGNAL ;
    PORT
      LAYER M5 ;
        RECT  28.656 23.676 28.68 23.76 ;
    END
  END o[151]
  PIN o[152]
    DIRECTION OUTPUT ;
    USE SIGNAL ;
    PORT
      LAYER M5 ;
        RECT  28.752 23.676 28.776 23.76 ;
    END
  END o[152]
  PIN o[153]
    DIRECTION OUTPUT ;
    USE SIGNAL ;
    PORT
      LAYER M5 ;
        RECT  28.848 23.676 28.872 23.76 ;
    END
  END o[153]
  PIN o[154]
    DIRECTION OUTPUT ;
    USE SIGNAL ;
    PORT
      LAYER M5 ;
        RECT  28.944 23.676 28.968 23.76 ;
    END
  END o[154]
  PIN o[155]
    DIRECTION OUTPUT ;
    USE SIGNAL ;
    PORT
      LAYER M5 ;
        RECT  29.04 23.676 29.064 23.76 ;
    END
  END o[155]
  PIN o[156]
    DIRECTION OUTPUT ;
    USE SIGNAL ;
    PORT
      LAYER M5 ;
        RECT  29.136 23.676 29.16 23.76 ;
    END
  END o[156]
  PIN o[157]
    DIRECTION OUTPUT ;
    USE SIGNAL ;
    PORT
      LAYER M5 ;
        RECT  29.232 23.676 29.256 23.76 ;
    END
  END o[157]
  PIN o[158]
    DIRECTION OUTPUT ;
    USE SIGNAL ;
    PORT
      LAYER M5 ;
        RECT  29.328 23.676 29.352 23.76 ;
    END
  END o[158]
  PIN o[159]
    DIRECTION OUTPUT ;
    USE SIGNAL ;
    PORT
      LAYER M5 ;
        RECT  29.424 23.676 29.448 23.76 ;
    END
  END o[159]
  PIN o[15]
    DIRECTION OUTPUT ;
    USE SIGNAL ;
    PORT
      LAYER M5 ;
        RECT  37.104 23.676 37.128 23.76 ;
    END
  END o[15]
  PIN o[160]
    DIRECTION OUTPUT ;
    USE SIGNAL ;
    PORT
      LAYER M5 ;
        RECT  29.52 23.676 29.544 23.76 ;
    END
  END o[160]
  PIN o[161]
    DIRECTION OUTPUT ;
    USE SIGNAL ;
    PORT
      LAYER M5 ;
        RECT  29.616 23.676 29.64 23.76 ;
    END
  END o[161]
  PIN o[162]
    DIRECTION OUTPUT ;
    USE SIGNAL ;
    PORT
      LAYER M5 ;
        RECT  29.712 23.676 29.736 23.76 ;
    END
  END o[162]
  PIN o[163]
    DIRECTION OUTPUT ;
    USE SIGNAL ;
    PORT
      LAYER M5 ;
        RECT  29.808 23.676 29.832 23.76 ;
    END
  END o[163]
  PIN o[164]
    DIRECTION OUTPUT ;
    USE SIGNAL ;
    PORT
      LAYER M5 ;
        RECT  29.904 23.676 29.928 23.76 ;
    END
  END o[164]
  PIN o[165]
    DIRECTION OUTPUT ;
    USE SIGNAL ;
    PORT
      LAYER M5 ;
        RECT  30 23.676 30.024 23.76 ;
    END
  END o[165]
  PIN o[166]
    DIRECTION OUTPUT ;
    USE SIGNAL ;
    PORT
      LAYER M5 ;
        RECT  30.096 23.676 30.12 23.76 ;
    END
  END o[166]
  PIN o[167]
    DIRECTION OUTPUT ;
    USE SIGNAL ;
    PORT
      LAYER M5 ;
        RECT  30.192 23.676 30.216 23.76 ;
    END
  END o[167]
  PIN o[168]
    DIRECTION OUTPUT ;
    USE SIGNAL ;
    PORT
      LAYER M5 ;
        RECT  30.288 23.676 30.312 23.76 ;
    END
  END o[168]
  PIN o[169]
    DIRECTION OUTPUT ;
    USE SIGNAL ;
    PORT
      LAYER M5 ;
        RECT  30.384 23.676 30.408 23.76 ;
    END
  END o[169]
  PIN o[16]
    DIRECTION OUTPUT ;
    USE SIGNAL ;
    PORT
      LAYER M5 ;
        RECT  37.2 23.676 37.224 23.76 ;
    END
  END o[16]
  PIN o[170]
    DIRECTION OUTPUT ;
    USE SIGNAL ;
    PORT
      LAYER M5 ;
        RECT  30.48 23.676 30.504 23.76 ;
    END
  END o[170]
  PIN o[171]
    DIRECTION OUTPUT ;
    USE SIGNAL ;
    PORT
      LAYER M5 ;
        RECT  30.576 23.676 30.6 23.76 ;
    END
  END o[171]
  PIN o[172]
    DIRECTION OUTPUT ;
    USE SIGNAL ;
    PORT
      LAYER M5 ;
        RECT  30.672 23.676 30.696 23.76 ;
    END
  END o[172]
  PIN o[173]
    DIRECTION OUTPUT ;
    USE SIGNAL ;
    PORT
      LAYER M5 ;
        RECT  30.768 23.676 30.792 23.76 ;
    END
  END o[173]
  PIN o[174]
    DIRECTION OUTPUT ;
    USE SIGNAL ;
    PORT
      LAYER M5 ;
        RECT  30.864 23.676 30.888 23.76 ;
    END
  END o[174]
  PIN o[175]
    DIRECTION OUTPUT ;
    USE SIGNAL ;
    PORT
      LAYER M5 ;
        RECT  30.96 23.676 30.984 23.76 ;
    END
  END o[175]
  PIN o[176]
    DIRECTION OUTPUT ;
    USE SIGNAL ;
    PORT
      LAYER M5 ;
        RECT  31.056 23.676 31.08 23.76 ;
    END
  END o[176]
  PIN o[177]
    DIRECTION OUTPUT ;
    USE SIGNAL ;
    PORT
      LAYER M5 ;
        RECT  31.152 23.676 31.176 23.76 ;
    END
  END o[177]
  PIN o[178]
    DIRECTION OUTPUT ;
    USE SIGNAL ;
    PORT
      LAYER M5 ;
        RECT  31.248 23.676 31.272 23.76 ;
    END
  END o[178]
  PIN o[179]
    DIRECTION OUTPUT ;
    USE SIGNAL ;
    PORT
      LAYER M5 ;
        RECT  31.344 23.676 31.368 23.76 ;
    END
  END o[179]
  PIN o[17]
    DIRECTION OUTPUT ;
    USE SIGNAL ;
    PORT
      LAYER M5 ;
        RECT  37.296 23.676 37.32 23.76 ;
    END
  END o[17]
  PIN o[180]
    DIRECTION OUTPUT ;
    USE SIGNAL ;
    PORT
      LAYER M5 ;
        RECT  31.44 23.676 31.464 23.76 ;
    END
  END o[180]
  PIN o[181]
    DIRECTION OUTPUT ;
    USE SIGNAL ;
    PORT
      LAYER M5 ;
        RECT  31.536 23.676 31.56 23.76 ;
    END
  END o[181]
  PIN o[182]
    DIRECTION OUTPUT ;
    USE SIGNAL ;
    PORT
      LAYER M5 ;
        RECT  31.632 23.676 31.656 23.76 ;
    END
  END o[182]
  PIN o[183]
    DIRECTION OUTPUT ;
    USE SIGNAL ;
    PORT
      LAYER M5 ;
        RECT  31.728 23.676 31.752 23.76 ;
    END
  END o[183]
  PIN o[184]
    DIRECTION OUTPUT ;
    USE SIGNAL ;
    PORT
      LAYER M5 ;
        RECT  31.824 23.676 31.848 23.76 ;
    END
  END o[184]
  PIN o[185]
    DIRECTION OUTPUT ;
    USE SIGNAL ;
    PORT
      LAYER M5 ;
        RECT  31.92 23.676 31.944 23.76 ;
    END
  END o[185]
  PIN o[186]
    DIRECTION OUTPUT ;
    USE SIGNAL ;
    PORT
      LAYER M5 ;
        RECT  32.016 23.676 32.04 23.76 ;
    END
  END o[186]
  PIN o[187]
    DIRECTION OUTPUT ;
    USE SIGNAL ;
    PORT
      LAYER M5 ;
        RECT  32.112 23.676 32.136 23.76 ;
    END
  END o[187]
  PIN o[188]
    DIRECTION OUTPUT ;
    USE SIGNAL ;
    PORT
      LAYER M5 ;
        RECT  32.208 23.676 32.232 23.76 ;
    END
  END o[188]
  PIN o[189]
    DIRECTION OUTPUT ;
    USE SIGNAL ;
    PORT
      LAYER M5 ;
        RECT  32.304 23.676 32.328 23.76 ;
    END
  END o[189]
  PIN o[18]
    DIRECTION OUTPUT ;
    USE SIGNAL ;
    PORT
      LAYER M5 ;
        RECT  37.392 23.676 37.416 23.76 ;
    END
  END o[18]
  PIN o[190]
    DIRECTION OUTPUT ;
    USE SIGNAL ;
    PORT
      LAYER M5 ;
        RECT  32.4 23.676 32.424 23.76 ;
    END
  END o[190]
  PIN o[191]
    DIRECTION OUTPUT ;
    USE SIGNAL ;
    PORT
      LAYER M5 ;
        RECT  32.496 23.676 32.52 23.76 ;
    END
  END o[191]
  PIN o[192]
    DIRECTION OUTPUT ;
    USE SIGNAL ;
    PORT
      LAYER M5 ;
        RECT  57.936 23.676 57.96 23.76 ;
    END
  END o[192]
  PIN o[193]
    DIRECTION OUTPUT ;
    USE SIGNAL ;
    PORT
      LAYER M5 ;
        RECT  58.032 23.676 58.056 23.76 ;
    END
  END o[193]
  PIN o[194]
    DIRECTION OUTPUT ;
    USE SIGNAL ;
    PORT
      LAYER M5 ;
        RECT  58.128 23.676 58.152 23.76 ;
    END
  END o[194]
  PIN o[195]
    DIRECTION OUTPUT ;
    USE SIGNAL ;
    PORT
      LAYER M5 ;
        RECT  58.224 23.676 58.248 23.76 ;
    END
  END o[195]
  PIN o[196]
    DIRECTION OUTPUT ;
    USE SIGNAL ;
    PORT
      LAYER M5 ;
        RECT  58.32 23.676 58.344 23.76 ;
    END
  END o[196]
  PIN o[197]
    DIRECTION OUTPUT ;
    USE SIGNAL ;
    PORT
      LAYER M5 ;
        RECT  58.416 23.676 58.44 23.76 ;
    END
  END o[197]
  PIN o[198]
    DIRECTION OUTPUT ;
    USE SIGNAL ;
    PORT
      LAYER M5 ;
        RECT  58.512 23.676 58.536 23.76 ;
    END
  END o[198]
  PIN o[199]
    DIRECTION OUTPUT ;
    USE SIGNAL ;
    PORT
      LAYER M5 ;
        RECT  58.608 23.676 58.632 23.76 ;
    END
  END o[199]
  PIN o[19]
    DIRECTION OUTPUT ;
    USE SIGNAL ;
    PORT
      LAYER M5 ;
        RECT  37.488 23.676 37.512 23.76 ;
    END
  END o[19]
  PIN o[1]
    DIRECTION OUTPUT ;
    USE SIGNAL ;
    PORT
      LAYER M5 ;
        RECT  35.76 23.676 35.784 23.76 ;
    END
  END o[1]
  PIN o[200]
    DIRECTION OUTPUT ;
    USE SIGNAL ;
    PORT
      LAYER M5 ;
        RECT  58.704 23.676 58.728 23.76 ;
    END
  END o[200]
  PIN o[201]
    DIRECTION OUTPUT ;
    USE SIGNAL ;
    PORT
      LAYER M5 ;
        RECT  58.8 23.676 58.824 23.76 ;
    END
  END o[201]
  PIN o[202]
    DIRECTION OUTPUT ;
    USE SIGNAL ;
    PORT
      LAYER M5 ;
        RECT  58.896 23.676 58.92 23.76 ;
    END
  END o[202]
  PIN o[203]
    DIRECTION OUTPUT ;
    USE SIGNAL ;
    PORT
      LAYER M5 ;
        RECT  58.992 23.676 59.016 23.76 ;
    END
  END o[203]
  PIN o[204]
    DIRECTION OUTPUT ;
    USE SIGNAL ;
    PORT
      LAYER M5 ;
        RECT  59.088 23.676 59.112 23.76 ;
    END
  END o[204]
  PIN o[205]
    DIRECTION OUTPUT ;
    USE SIGNAL ;
    PORT
      LAYER M5 ;
        RECT  59.184 23.676 59.208 23.76 ;
    END
  END o[205]
  PIN o[206]
    DIRECTION OUTPUT ;
    USE SIGNAL ;
    PORT
      LAYER M5 ;
        RECT  59.28 23.676 59.304 23.76 ;
    END
  END o[206]
  PIN o[207]
    DIRECTION OUTPUT ;
    USE SIGNAL ;
    PORT
      LAYER M5 ;
        RECT  59.376 23.676 59.4 23.76 ;
    END
  END o[207]
  PIN o[208]
    DIRECTION OUTPUT ;
    USE SIGNAL ;
    PORT
      LAYER M5 ;
        RECT  59.472 23.676 59.496 23.76 ;
    END
  END o[208]
  PIN o[209]
    DIRECTION OUTPUT ;
    USE SIGNAL ;
    PORT
      LAYER M5 ;
        RECT  59.568 23.676 59.592 23.76 ;
    END
  END o[209]
  PIN o[20]
    DIRECTION OUTPUT ;
    USE SIGNAL ;
    PORT
      LAYER M5 ;
        RECT  37.584 23.676 37.608 23.76 ;
    END
  END o[20]
  PIN o[210]
    DIRECTION OUTPUT ;
    USE SIGNAL ;
    PORT
      LAYER M5 ;
        RECT  59.664 23.676 59.688 23.76 ;
    END
  END o[210]
  PIN o[211]
    DIRECTION OUTPUT ;
    USE SIGNAL ;
    PORT
      LAYER M5 ;
        RECT  59.76 23.676 59.784 23.76 ;
    END
  END o[211]
  PIN o[212]
    DIRECTION OUTPUT ;
    USE SIGNAL ;
    PORT
      LAYER M5 ;
        RECT  59.856 23.676 59.88 23.76 ;
    END
  END o[212]
  PIN o[213]
    DIRECTION OUTPUT ;
    USE SIGNAL ;
    PORT
      LAYER M5 ;
        RECT  59.952 23.676 59.976 23.76 ;
    END
  END o[213]
  PIN o[214]
    DIRECTION OUTPUT ;
    USE SIGNAL ;
    PORT
      LAYER M5 ;
        RECT  60.048 23.676 60.072 23.76 ;
    END
  END o[214]
  PIN o[215]
    DIRECTION OUTPUT ;
    USE SIGNAL ;
    PORT
      LAYER M5 ;
        RECT  60.144 23.676 60.168 23.76 ;
    END
  END o[215]
  PIN o[216]
    DIRECTION OUTPUT ;
    USE SIGNAL ;
    PORT
      LAYER M5 ;
        RECT  60.24 23.676 60.264 23.76 ;
    END
  END o[216]
  PIN o[217]
    DIRECTION OUTPUT ;
    USE SIGNAL ;
    PORT
      LAYER M5 ;
        RECT  60.336 23.676 60.36 23.76 ;
    END
  END o[217]
  PIN o[218]
    DIRECTION OUTPUT ;
    USE SIGNAL ;
    PORT
      LAYER M5 ;
        RECT  60.432 23.676 60.456 23.76 ;
    END
  END o[218]
  PIN o[219]
    DIRECTION OUTPUT ;
    USE SIGNAL ;
    PORT
      LAYER M5 ;
        RECT  60.528 23.676 60.552 23.76 ;
    END
  END o[219]
  PIN o[21]
    DIRECTION OUTPUT ;
    USE SIGNAL ;
    PORT
      LAYER M5 ;
        RECT  37.68 23.676 37.704 23.76 ;
    END
  END o[21]
  PIN o[220]
    DIRECTION OUTPUT ;
    USE SIGNAL ;
    PORT
      LAYER M5 ;
        RECT  60.624 23.676 60.648 23.76 ;
    END
  END o[220]
  PIN o[221]
    DIRECTION OUTPUT ;
    USE SIGNAL ;
    PORT
      LAYER M5 ;
        RECT  60.72 23.676 60.744 23.76 ;
    END
  END o[221]
  PIN o[222]
    DIRECTION OUTPUT ;
    USE SIGNAL ;
    PORT
      LAYER M5 ;
        RECT  60.816 23.676 60.84 23.76 ;
    END
  END o[222]
  PIN o[223]
    DIRECTION OUTPUT ;
    USE SIGNAL ;
    PORT
      LAYER M5 ;
        RECT  60.912 23.676 60.936 23.76 ;
    END
  END o[223]
  PIN o[224]
    DIRECTION OUTPUT ;
    USE SIGNAL ;
    PORT
      LAYER M5 ;
        RECT  61.008 23.676 61.032 23.76 ;
    END
  END o[224]
  PIN o[225]
    DIRECTION OUTPUT ;
    USE SIGNAL ;
    PORT
      LAYER M5 ;
        RECT  61.104 23.676 61.128 23.76 ;
    END
  END o[225]
  PIN o[226]
    DIRECTION OUTPUT ;
    USE SIGNAL ;
    PORT
      LAYER M5 ;
        RECT  61.2 23.676 61.224 23.76 ;
    END
  END o[226]
  PIN o[227]
    DIRECTION OUTPUT ;
    USE SIGNAL ;
    PORT
      LAYER M5 ;
        RECT  61.296 23.676 61.32 23.76 ;
    END
  END o[227]
  PIN o[228]
    DIRECTION OUTPUT ;
    USE SIGNAL ;
    PORT
      LAYER M5 ;
        RECT  61.392 23.676 61.416 23.76 ;
    END
  END o[228]
  PIN o[229]
    DIRECTION OUTPUT ;
    USE SIGNAL ;
    PORT
      LAYER M5 ;
        RECT  61.488 23.676 61.512 23.76 ;
    END
  END o[229]
  PIN o[22]
    DIRECTION OUTPUT ;
    USE SIGNAL ;
    PORT
      LAYER M5 ;
        RECT  37.776 23.676 37.8 23.76 ;
    END
  END o[22]
  PIN o[230]
    DIRECTION OUTPUT ;
    USE SIGNAL ;
    PORT
      LAYER M5 ;
        RECT  61.584 23.676 61.608 23.76 ;
    END
  END o[230]
  PIN o[231]
    DIRECTION OUTPUT ;
    USE SIGNAL ;
    PORT
      LAYER M5 ;
        RECT  61.68 23.676 61.704 23.76 ;
    END
  END o[231]
  PIN o[232]
    DIRECTION OUTPUT ;
    USE SIGNAL ;
    PORT
      LAYER M5 ;
        RECT  61.776 23.676 61.8 23.76 ;
    END
  END o[232]
  PIN o[233]
    DIRECTION OUTPUT ;
    USE SIGNAL ;
    PORT
      LAYER M5 ;
        RECT  61.872 23.676 61.896 23.76 ;
    END
  END o[233]
  PIN o[234]
    DIRECTION OUTPUT ;
    USE SIGNAL ;
    PORT
      LAYER M5 ;
        RECT  61.968 23.676 61.992 23.76 ;
    END
  END o[234]
  PIN o[235]
    DIRECTION OUTPUT ;
    USE SIGNAL ;
    PORT
      LAYER M5 ;
        RECT  62.064 23.676 62.088 23.76 ;
    END
  END o[235]
  PIN o[236]
    DIRECTION OUTPUT ;
    USE SIGNAL ;
    PORT
      LAYER M5 ;
        RECT  62.16 23.676 62.184 23.76 ;
    END
  END o[236]
  PIN o[237]
    DIRECTION OUTPUT ;
    USE SIGNAL ;
    PORT
      LAYER M5 ;
        RECT  62.256 23.676 62.28 23.76 ;
    END
  END o[237]
  PIN o[238]
    DIRECTION OUTPUT ;
    USE SIGNAL ;
    PORT
      LAYER M5 ;
        RECT  62.352 23.676 62.376 23.76 ;
    END
  END o[238]
  PIN o[239]
    DIRECTION OUTPUT ;
    USE SIGNAL ;
    PORT
      LAYER M5 ;
        RECT  62.448 23.676 62.472 23.76 ;
    END
  END o[239]
  PIN o[23]
    DIRECTION OUTPUT ;
    USE SIGNAL ;
    PORT
      LAYER M5 ;
        RECT  37.872 23.676 37.896 23.76 ;
    END
  END o[23]
  PIN o[240]
    DIRECTION OUTPUT ;
    USE SIGNAL ;
    PORT
      LAYER M5 ;
        RECT  62.544 23.676 62.568 23.76 ;
    END
  END o[240]
  PIN o[241]
    DIRECTION OUTPUT ;
    USE SIGNAL ;
    PORT
      LAYER M5 ;
        RECT  62.64 23.676 62.664 23.76 ;
    END
  END o[241]
  PIN o[242]
    DIRECTION OUTPUT ;
    USE SIGNAL ;
    PORT
      LAYER M5 ;
        RECT  62.736 23.676 62.76 23.76 ;
    END
  END o[242]
  PIN o[243]
    DIRECTION OUTPUT ;
    USE SIGNAL ;
    PORT
      LAYER M5 ;
        RECT  62.832 23.676 62.856 23.76 ;
    END
  END o[243]
  PIN o[244]
    DIRECTION OUTPUT ;
    USE SIGNAL ;
    PORT
      LAYER M5 ;
        RECT  62.928 23.676 62.952 23.76 ;
    END
  END o[244]
  PIN o[245]
    DIRECTION OUTPUT ;
    USE SIGNAL ;
    PORT
      LAYER M5 ;
        RECT  63.024 23.676 63.048 23.76 ;
    END
  END o[245]
  PIN o[246]
    DIRECTION OUTPUT ;
    USE SIGNAL ;
    PORT
      LAYER M5 ;
        RECT  63.12 23.676 63.144 23.76 ;
    END
  END o[246]
  PIN o[247]
    DIRECTION OUTPUT ;
    USE SIGNAL ;
    PORT
      LAYER M5 ;
        RECT  63.216 23.676 63.24 23.76 ;
    END
  END o[247]
  PIN o[248]
    DIRECTION OUTPUT ;
    USE SIGNAL ;
    PORT
      LAYER M5 ;
        RECT  63.312 23.676 63.336 23.76 ;
    END
  END o[248]
  PIN o[249]
    DIRECTION OUTPUT ;
    USE SIGNAL ;
    PORT
      LAYER M5 ;
        RECT  63.408 23.676 63.432 23.76 ;
    END
  END o[249]
  PIN o[24]
    DIRECTION OUTPUT ;
    USE SIGNAL ;
    PORT
      LAYER M5 ;
        RECT  37.968 23.676 37.992 23.76 ;
    END
  END o[24]
  PIN o[250]
    DIRECTION OUTPUT ;
    USE SIGNAL ;
    PORT
      LAYER M5 ;
        RECT  63.504 23.676 63.528 23.76 ;
    END
  END o[250]
  PIN o[251]
    DIRECTION OUTPUT ;
    USE SIGNAL ;
    PORT
      LAYER M5 ;
        RECT  63.6 23.676 63.624 23.76 ;
    END
  END o[251]
  PIN o[252]
    DIRECTION OUTPUT ;
    USE SIGNAL ;
    PORT
      LAYER M5 ;
        RECT  63.696 23.676 63.72 23.76 ;
    END
  END o[252]
  PIN o[253]
    DIRECTION OUTPUT ;
    USE SIGNAL ;
    PORT
      LAYER M5 ;
        RECT  63.792 23.676 63.816 23.76 ;
    END
  END o[253]
  PIN o[254]
    DIRECTION OUTPUT ;
    USE SIGNAL ;
    PORT
      LAYER M5 ;
        RECT  63.888 23.676 63.912 23.76 ;
    END
  END o[254]
  PIN o[255]
    DIRECTION OUTPUT ;
    USE SIGNAL ;
    PORT
      LAYER M5 ;
        RECT  63.984 23.676 64.008 23.76 ;
    END
  END o[255]
  PIN o[256]
    DIRECTION OUTPUT ;
    USE SIGNAL ;
    PORT
      LAYER M5 ;
        RECT  22.608 23.676 22.632 23.76 ;
    END
  END o[256]
  PIN o[257]
    DIRECTION OUTPUT ;
    USE SIGNAL ;
    PORT
      LAYER M5 ;
        RECT  22.704 23.676 22.728 23.76 ;
    END
  END o[257]
  PIN o[258]
    DIRECTION OUTPUT ;
    USE SIGNAL ;
    PORT
      LAYER M5 ;
        RECT  22.8 23.676 22.824 23.76 ;
    END
  END o[258]
  PIN o[259]
    DIRECTION OUTPUT ;
    USE SIGNAL ;
    PORT
      LAYER M5 ;
        RECT  22.896 23.676 22.92 23.76 ;
    END
  END o[259]
  PIN o[25]
    DIRECTION OUTPUT ;
    USE SIGNAL ;
    PORT
      LAYER M5 ;
        RECT  38.064 23.676 38.088 23.76 ;
    END
  END o[25]
  PIN o[260]
    DIRECTION OUTPUT ;
    USE SIGNAL ;
    PORT
      LAYER M5 ;
        RECT  22.992 23.676 23.016 23.76 ;
    END
  END o[260]
  PIN o[261]
    DIRECTION OUTPUT ;
    USE SIGNAL ;
    PORT
      LAYER M5 ;
        RECT  23.088 23.676 23.112 23.76 ;
    END
  END o[261]
  PIN o[262]
    DIRECTION OUTPUT ;
    USE SIGNAL ;
    PORT
      LAYER M5 ;
        RECT  23.184 23.676 23.208 23.76 ;
    END
  END o[262]
  PIN o[263]
    DIRECTION OUTPUT ;
    USE SIGNAL ;
    PORT
      LAYER M5 ;
        RECT  23.28 23.676 23.304 23.76 ;
    END
  END o[263]
  PIN o[264]
    DIRECTION OUTPUT ;
    USE SIGNAL ;
    PORT
      LAYER M5 ;
        RECT  23.376 23.676 23.4 23.76 ;
    END
  END o[264]
  PIN o[265]
    DIRECTION OUTPUT ;
    USE SIGNAL ;
    PORT
      LAYER M5 ;
        RECT  23.472 23.676 23.496 23.76 ;
    END
  END o[265]
  PIN o[266]
    DIRECTION OUTPUT ;
    USE SIGNAL ;
    PORT
      LAYER M5 ;
        RECT  23.568 23.676 23.592 23.76 ;
    END
  END o[266]
  PIN o[267]
    DIRECTION OUTPUT ;
    USE SIGNAL ;
    PORT
      LAYER M5 ;
        RECT  23.664 23.676 23.688 23.76 ;
    END
  END o[267]
  PIN o[268]
    DIRECTION OUTPUT ;
    USE SIGNAL ;
    PORT
      LAYER M5 ;
        RECT  23.76 23.676 23.784 23.76 ;
    END
  END o[268]
  PIN o[269]
    DIRECTION OUTPUT ;
    USE SIGNAL ;
    PORT
      LAYER M5 ;
        RECT  23.856 23.676 23.88 23.76 ;
    END
  END o[269]
  PIN o[26]
    DIRECTION OUTPUT ;
    USE SIGNAL ;
    PORT
      LAYER M5 ;
        RECT  38.16 23.676 38.184 23.76 ;
    END
  END o[26]
  PIN o[270]
    DIRECTION OUTPUT ;
    USE SIGNAL ;
    PORT
      LAYER M5 ;
        RECT  23.952 23.676 23.976 23.76 ;
    END
  END o[270]
  PIN o[271]
    DIRECTION OUTPUT ;
    USE SIGNAL ;
    PORT
      LAYER M5 ;
        RECT  24.048 23.676 24.072 23.76 ;
    END
  END o[271]
  PIN o[272]
    DIRECTION OUTPUT ;
    USE SIGNAL ;
    PORT
      LAYER M5 ;
        RECT  24.144 23.676 24.168 23.76 ;
    END
  END o[272]
  PIN o[273]
    DIRECTION OUTPUT ;
    USE SIGNAL ;
    PORT
      LAYER M5 ;
        RECT  24.24 23.676 24.264 23.76 ;
    END
  END o[273]
  PIN o[274]
    DIRECTION OUTPUT ;
    USE SIGNAL ;
    PORT
      LAYER M5 ;
        RECT  24.336 23.676 24.36 23.76 ;
    END
  END o[274]
  PIN o[275]
    DIRECTION OUTPUT ;
    USE SIGNAL ;
    PORT
      LAYER M5 ;
        RECT  24.432 23.676 24.456 23.76 ;
    END
  END o[275]
  PIN o[276]
    DIRECTION OUTPUT ;
    USE SIGNAL ;
    PORT
      LAYER M5 ;
        RECT  24.528 23.676 24.552 23.76 ;
    END
  END o[276]
  PIN o[277]
    DIRECTION OUTPUT ;
    USE SIGNAL ;
    PORT
      LAYER M5 ;
        RECT  24.624 23.676 24.648 23.76 ;
    END
  END o[277]
  PIN o[278]
    DIRECTION OUTPUT ;
    USE SIGNAL ;
    PORT
      LAYER M5 ;
        RECT  24.72 23.676 24.744 23.76 ;
    END
  END o[278]
  PIN o[279]
    DIRECTION OUTPUT ;
    USE SIGNAL ;
    PORT
      LAYER M5 ;
        RECT  24.816 23.676 24.84 23.76 ;
    END
  END o[279]
  PIN o[27]
    DIRECTION OUTPUT ;
    USE SIGNAL ;
    PORT
      LAYER M5 ;
        RECT  38.256 23.676 38.28 23.76 ;
    END
  END o[27]
  PIN o[280]
    DIRECTION OUTPUT ;
    USE SIGNAL ;
    PORT
      LAYER M5 ;
        RECT  24.912 23.676 24.936 23.76 ;
    END
  END o[280]
  PIN o[281]
    DIRECTION OUTPUT ;
    USE SIGNAL ;
    PORT
      LAYER M5 ;
        RECT  25.008 23.676 25.032 23.76 ;
    END
  END o[281]
  PIN o[282]
    DIRECTION OUTPUT ;
    USE SIGNAL ;
    PORT
      LAYER M5 ;
        RECT  25.104 23.676 25.128 23.76 ;
    END
  END o[282]
  PIN o[283]
    DIRECTION OUTPUT ;
    USE SIGNAL ;
    PORT
      LAYER M5 ;
        RECT  25.2 23.676 25.224 23.76 ;
    END
  END o[283]
  PIN o[284]
    DIRECTION OUTPUT ;
    USE SIGNAL ;
    PORT
      LAYER M5 ;
        RECT  25.296 23.676 25.32 23.76 ;
    END
  END o[284]
  PIN o[285]
    DIRECTION OUTPUT ;
    USE SIGNAL ;
    PORT
      LAYER M5 ;
        RECT  25.392 23.676 25.416 23.76 ;
    END
  END o[285]
  PIN o[286]
    DIRECTION OUTPUT ;
    USE SIGNAL ;
    PORT
      LAYER M5 ;
        RECT  25.488 23.676 25.512 23.76 ;
    END
  END o[286]
  PIN o[287]
    DIRECTION OUTPUT ;
    USE SIGNAL ;
    PORT
      LAYER M5 ;
        RECT  25.584 23.676 25.608 23.76 ;
    END
  END o[287]
  PIN o[288]
    DIRECTION OUTPUT ;
    USE SIGNAL ;
    PORT
      LAYER M5 ;
        RECT  10.32 23.676 10.344 23.76 ;
    END
  END o[288]
  PIN o[289]
    DIRECTION OUTPUT ;
    USE SIGNAL ;
    PORT
      LAYER M5 ;
        RECT  10.416 23.676 10.44 23.76 ;
    END
  END o[289]
  PIN o[28]
    DIRECTION OUTPUT ;
    USE SIGNAL ;
    PORT
      LAYER M5 ;
        RECT  38.352 23.676 38.376 23.76 ;
    END
  END o[28]
  PIN o[290]
    DIRECTION OUTPUT ;
    USE SIGNAL ;
    PORT
      LAYER M5 ;
        RECT  10.512 23.676 10.536 23.76 ;
    END
  END o[290]
  PIN o[291]
    DIRECTION OUTPUT ;
    USE SIGNAL ;
    PORT
      LAYER M5 ;
        RECT  10.608 23.676 10.632 23.76 ;
    END
  END o[291]
  PIN o[292]
    DIRECTION OUTPUT ;
    USE SIGNAL ;
    PORT
      LAYER M5 ;
        RECT  10.704 23.676 10.728 23.76 ;
    END
  END o[292]
  PIN o[293]
    DIRECTION OUTPUT ;
    USE SIGNAL ;
    PORT
      LAYER M5 ;
        RECT  10.8 23.676 10.824 23.76 ;
    END
  END o[293]
  PIN o[294]
    DIRECTION OUTPUT ;
    USE SIGNAL ;
    PORT
      LAYER M5 ;
        RECT  10.896 23.676 10.92 23.76 ;
    END
  END o[294]
  PIN o[295]
    DIRECTION OUTPUT ;
    USE SIGNAL ;
    PORT
      LAYER M5 ;
        RECT  10.992 23.676 11.016 23.76 ;
    END
  END o[295]
  PIN o[296]
    DIRECTION OUTPUT ;
    USE SIGNAL ;
    PORT
      LAYER M5 ;
        RECT  11.088 23.676 11.112 23.76 ;
    END
  END o[296]
  PIN o[297]
    DIRECTION OUTPUT ;
    USE SIGNAL ;
    PORT
      LAYER M5 ;
        RECT  11.184 23.676 11.208 23.76 ;
    END
  END o[297]
  PIN o[298]
    DIRECTION OUTPUT ;
    USE SIGNAL ;
    PORT
      LAYER M5 ;
        RECT  11.28 23.676 11.304 23.76 ;
    END
  END o[298]
  PIN o[299]
    DIRECTION OUTPUT ;
    USE SIGNAL ;
    PORT
      LAYER M5 ;
        RECT  11.376 23.676 11.4 23.76 ;
    END
  END o[299]
  PIN o[29]
    DIRECTION OUTPUT ;
    USE SIGNAL ;
    PORT
      LAYER M5 ;
        RECT  38.448 23.676 38.472 23.76 ;
    END
  END o[29]
  PIN o[2]
    DIRECTION OUTPUT ;
    USE SIGNAL ;
    PORT
      LAYER M5 ;
        RECT  35.856 23.676 35.88 23.76 ;
    END
  END o[2]
  PIN o[300]
    DIRECTION OUTPUT ;
    USE SIGNAL ;
    PORT
      LAYER M5 ;
        RECT  11.472 23.676 11.496 23.76 ;
    END
  END o[300]
  PIN o[301]
    DIRECTION OUTPUT ;
    USE SIGNAL ;
    PORT
      LAYER M5 ;
        RECT  11.568 23.676 11.592 23.76 ;
    END
  END o[301]
  PIN o[302]
    DIRECTION OUTPUT ;
    USE SIGNAL ;
    PORT
      LAYER M5 ;
        RECT  11.664 23.676 11.688 23.76 ;
    END
  END o[302]
  PIN o[303]
    DIRECTION OUTPUT ;
    USE SIGNAL ;
    PORT
      LAYER M5 ;
        RECT  11.76 23.676 11.784 23.76 ;
    END
  END o[303]
  PIN o[304]
    DIRECTION OUTPUT ;
    USE SIGNAL ;
    PORT
      LAYER M5 ;
        RECT  11.856 23.676 11.88 23.76 ;
    END
  END o[304]
  PIN o[305]
    DIRECTION OUTPUT ;
    USE SIGNAL ;
    PORT
      LAYER M5 ;
        RECT  11.952 23.676 11.976 23.76 ;
    END
  END o[305]
  PIN o[306]
    DIRECTION OUTPUT ;
    USE SIGNAL ;
    PORT
      LAYER M5 ;
        RECT  12.048 23.676 12.072 23.76 ;
    END
  END o[306]
  PIN o[307]
    DIRECTION OUTPUT ;
    USE SIGNAL ;
    PORT
      LAYER M5 ;
        RECT  12.144 23.676 12.168 23.76 ;
    END
  END o[307]
  PIN o[308]
    DIRECTION OUTPUT ;
    USE SIGNAL ;
    PORT
      LAYER M5 ;
        RECT  12.24 23.676 12.264 23.76 ;
    END
  END o[308]
  PIN o[309]
    DIRECTION OUTPUT ;
    USE SIGNAL ;
    PORT
      LAYER M5 ;
        RECT  12.336 23.676 12.36 23.76 ;
    END
  END o[309]
  PIN o[30]
    DIRECTION OUTPUT ;
    USE SIGNAL ;
    PORT
      LAYER M5 ;
        RECT  38.544 23.676 38.568 23.76 ;
    END
  END o[30]
  PIN o[310]
    DIRECTION OUTPUT ;
    USE SIGNAL ;
    PORT
      LAYER M5 ;
        RECT  12.432 23.676 12.456 23.76 ;
    END
  END o[310]
  PIN o[311]
    DIRECTION OUTPUT ;
    USE SIGNAL ;
    PORT
      LAYER M5 ;
        RECT  12.528 23.676 12.552 23.76 ;
    END
  END o[311]
  PIN o[312]
    DIRECTION OUTPUT ;
    USE SIGNAL ;
    PORT
      LAYER M5 ;
        RECT  12.624 23.676 12.648 23.76 ;
    END
  END o[312]
  PIN o[313]
    DIRECTION OUTPUT ;
    USE SIGNAL ;
    PORT
      LAYER M5 ;
        RECT  12.72 23.676 12.744 23.76 ;
    END
  END o[313]
  PIN o[314]
    DIRECTION OUTPUT ;
    USE SIGNAL ;
    PORT
      LAYER M5 ;
        RECT  12.816 23.676 12.84 23.76 ;
    END
  END o[314]
  PIN o[315]
    DIRECTION OUTPUT ;
    USE SIGNAL ;
    PORT
      LAYER M5 ;
        RECT  12.912 23.676 12.936 23.76 ;
    END
  END o[315]
  PIN o[316]
    DIRECTION OUTPUT ;
    USE SIGNAL ;
    PORT
      LAYER M5 ;
        RECT  13.008 23.676 13.032 23.76 ;
    END
  END o[316]
  PIN o[317]
    DIRECTION OUTPUT ;
    USE SIGNAL ;
    PORT
      LAYER M5 ;
        RECT  13.104 23.676 13.128 23.76 ;
    END
  END o[317]
  PIN o[318]
    DIRECTION OUTPUT ;
    USE SIGNAL ;
    PORT
      LAYER M5 ;
        RECT  13.2 23.676 13.224 23.76 ;
    END
  END o[318]
  PIN o[319]
    DIRECTION OUTPUT ;
    USE SIGNAL ;
    PORT
      LAYER M5 ;
        RECT  13.296 23.676 13.32 23.76 ;
    END
  END o[319]
  PIN o[31]
    DIRECTION OUTPUT ;
    USE SIGNAL ;
    PORT
      LAYER M5 ;
        RECT  38.64 23.676 38.664 23.76 ;
    END
  END o[31]
  PIN o[320]
    DIRECTION OUTPUT ;
    USE SIGNAL ;
    PORT
      LAYER M5 ;
        RECT  7.248 23.676 7.272 23.76 ;
    END
  END o[320]
  PIN o[321]
    DIRECTION OUTPUT ;
    USE SIGNAL ;
    PORT
      LAYER M5 ;
        RECT  7.344 23.676 7.368 23.76 ;
    END
  END o[321]
  PIN o[322]
    DIRECTION OUTPUT ;
    USE SIGNAL ;
    PORT
      LAYER M5 ;
        RECT  7.44 23.676 7.464 23.76 ;
    END
  END o[322]
  PIN o[323]
    DIRECTION OUTPUT ;
    USE SIGNAL ;
    PORT
      LAYER M5 ;
        RECT  7.536 23.676 7.56 23.76 ;
    END
  END o[323]
  PIN o[324]
    DIRECTION OUTPUT ;
    USE SIGNAL ;
    PORT
      LAYER M5 ;
        RECT  7.632 23.676 7.656 23.76 ;
    END
  END o[324]
  PIN o[325]
    DIRECTION OUTPUT ;
    USE SIGNAL ;
    PORT
      LAYER M5 ;
        RECT  7.728 23.676 7.752 23.76 ;
    END
  END o[325]
  PIN o[326]
    DIRECTION OUTPUT ;
    USE SIGNAL ;
    PORT
      LAYER M5 ;
        RECT  7.824 23.676 7.848 23.76 ;
    END
  END o[326]
  PIN o[327]
    DIRECTION OUTPUT ;
    USE SIGNAL ;
    PORT
      LAYER M5 ;
        RECT  7.92 23.676 7.944 23.76 ;
    END
  END o[327]
  PIN o[328]
    DIRECTION OUTPUT ;
    USE SIGNAL ;
    PORT
      LAYER M5 ;
        RECT  8.016 23.676 8.04 23.76 ;
    END
  END o[328]
  PIN o[329]
    DIRECTION OUTPUT ;
    USE SIGNAL ;
    PORT
      LAYER M5 ;
        RECT  8.112 23.676 8.136 23.76 ;
    END
  END o[329]
  PIN o[32]
    DIRECTION OUTPUT ;
    USE SIGNAL ;
    PORT
      LAYER M5 ;
        RECT  32.592 23.676 32.616 23.76 ;
    END
  END o[32]
  PIN o[330]
    DIRECTION OUTPUT ;
    USE SIGNAL ;
    PORT
      LAYER M5 ;
        RECT  8.208 23.676 8.232 23.76 ;
    END
  END o[330]
  PIN o[331]
    DIRECTION OUTPUT ;
    USE SIGNAL ;
    PORT
      LAYER M5 ;
        RECT  8.304 23.676 8.328 23.76 ;
    END
  END o[331]
  PIN o[332]
    DIRECTION OUTPUT ;
    USE SIGNAL ;
    PORT
      LAYER M5 ;
        RECT  8.4 23.676 8.424 23.76 ;
    END
  END o[332]
  PIN o[333]
    DIRECTION OUTPUT ;
    USE SIGNAL ;
    PORT
      LAYER M5 ;
        RECT  8.496 23.676 8.52 23.76 ;
    END
  END o[333]
  PIN o[334]
    DIRECTION OUTPUT ;
    USE SIGNAL ;
    PORT
      LAYER M5 ;
        RECT  8.592 23.676 8.616 23.76 ;
    END
  END o[334]
  PIN o[335]
    DIRECTION OUTPUT ;
    USE SIGNAL ;
    PORT
      LAYER M5 ;
        RECT  8.688 23.676 8.712 23.76 ;
    END
  END o[335]
  PIN o[336]
    DIRECTION OUTPUT ;
    USE SIGNAL ;
    PORT
      LAYER M5 ;
        RECT  8.784 23.676 8.808 23.76 ;
    END
  END o[336]
  PIN o[337]
    DIRECTION OUTPUT ;
    USE SIGNAL ;
    PORT
      LAYER M5 ;
        RECT  8.88 23.676 8.904 23.76 ;
    END
  END o[337]
  PIN o[338]
    DIRECTION OUTPUT ;
    USE SIGNAL ;
    PORT
      LAYER M5 ;
        RECT  8.976 23.676 9 23.76 ;
    END
  END o[338]
  PIN o[339]
    DIRECTION OUTPUT ;
    USE SIGNAL ;
    PORT
      LAYER M5 ;
        RECT  9.072 23.676 9.096 23.76 ;
    END
  END o[339]
  PIN o[33]
    DIRECTION OUTPUT ;
    USE SIGNAL ;
    PORT
      LAYER M5 ;
        RECT  32.688 23.676 32.712 23.76 ;
    END
  END o[33]
  PIN o[340]
    DIRECTION OUTPUT ;
    USE SIGNAL ;
    PORT
      LAYER M5 ;
        RECT  9.168 23.676 9.192 23.76 ;
    END
  END o[340]
  PIN o[341]
    DIRECTION OUTPUT ;
    USE SIGNAL ;
    PORT
      LAYER M5 ;
        RECT  9.264 23.676 9.288 23.76 ;
    END
  END o[341]
  PIN o[342]
    DIRECTION OUTPUT ;
    USE SIGNAL ;
    PORT
      LAYER M5 ;
        RECT  9.36 23.676 9.384 23.76 ;
    END
  END o[342]
  PIN o[343]
    DIRECTION OUTPUT ;
    USE SIGNAL ;
    PORT
      LAYER M5 ;
        RECT  9.456 23.676 9.48 23.76 ;
    END
  END o[343]
  PIN o[344]
    DIRECTION OUTPUT ;
    USE SIGNAL ;
    PORT
      LAYER M5 ;
        RECT  9.552 23.676 9.576 23.76 ;
    END
  END o[344]
  PIN o[345]
    DIRECTION OUTPUT ;
    USE SIGNAL ;
    PORT
      LAYER M5 ;
        RECT  9.648 23.676 9.672 23.76 ;
    END
  END o[345]
  PIN o[346]
    DIRECTION OUTPUT ;
    USE SIGNAL ;
    PORT
      LAYER M5 ;
        RECT  9.744 23.676 9.768 23.76 ;
    END
  END o[346]
  PIN o[347]
    DIRECTION OUTPUT ;
    USE SIGNAL ;
    PORT
      LAYER M5 ;
        RECT  9.84 23.676 9.864 23.76 ;
    END
  END o[347]
  PIN o[348]
    DIRECTION OUTPUT ;
    USE SIGNAL ;
    PORT
      LAYER M5 ;
        RECT  9.936 23.676 9.96 23.76 ;
    END
  END o[348]
  PIN o[349]
    DIRECTION OUTPUT ;
    USE SIGNAL ;
    PORT
      LAYER M5 ;
        RECT  10.032 23.676 10.056 23.76 ;
    END
  END o[349]
  PIN o[34]
    DIRECTION OUTPUT ;
    USE SIGNAL ;
    PORT
      LAYER M5 ;
        RECT  32.784 23.676 32.808 23.76 ;
    END
  END o[34]
  PIN o[350]
    DIRECTION OUTPUT ;
    USE SIGNAL ;
    PORT
      LAYER M5 ;
        RECT  10.128 23.676 10.152 23.76 ;
    END
  END o[350]
  PIN o[351]
    DIRECTION OUTPUT ;
    USE SIGNAL ;
    PORT
      LAYER M5 ;
        RECT  10.224 23.676 10.248 23.76 ;
    END
  END o[351]
  PIN o[352]
    DIRECTION OUTPUT ;
    USE SIGNAL ;
    PORT
      LAYER M5 ;
        RECT  19.536 23.676 19.56 23.76 ;
    END
  END o[352]
  PIN o[353]
    DIRECTION OUTPUT ;
    USE SIGNAL ;
    PORT
      LAYER M5 ;
        RECT  19.632 23.676 19.656 23.76 ;
    END
  END o[353]
  PIN o[354]
    DIRECTION OUTPUT ;
    USE SIGNAL ;
    PORT
      LAYER M5 ;
        RECT  19.728 23.676 19.752 23.76 ;
    END
  END o[354]
  PIN o[355]
    DIRECTION OUTPUT ;
    USE SIGNAL ;
    PORT
      LAYER M5 ;
        RECT  19.824 23.676 19.848 23.76 ;
    END
  END o[355]
  PIN o[356]
    DIRECTION OUTPUT ;
    USE SIGNAL ;
    PORT
      LAYER M5 ;
        RECT  19.92 23.676 19.944 23.76 ;
    END
  END o[356]
  PIN o[357]
    DIRECTION OUTPUT ;
    USE SIGNAL ;
    PORT
      LAYER M5 ;
        RECT  20.016 23.676 20.04 23.76 ;
    END
  END o[357]
  PIN o[358]
    DIRECTION OUTPUT ;
    USE SIGNAL ;
    PORT
      LAYER M5 ;
        RECT  20.112 23.676 20.136 23.76 ;
    END
  END o[358]
  PIN o[359]
    DIRECTION OUTPUT ;
    USE SIGNAL ;
    PORT
      LAYER M5 ;
        RECT  20.208 23.676 20.232 23.76 ;
    END
  END o[359]
  PIN o[35]
    DIRECTION OUTPUT ;
    USE SIGNAL ;
    PORT
      LAYER M5 ;
        RECT  32.88 23.676 32.904 23.76 ;
    END
  END o[35]
  PIN o[360]
    DIRECTION OUTPUT ;
    USE SIGNAL ;
    PORT
      LAYER M5 ;
        RECT  20.304 23.676 20.328 23.76 ;
    END
  END o[360]
  PIN o[361]
    DIRECTION OUTPUT ;
    USE SIGNAL ;
    PORT
      LAYER M5 ;
        RECT  20.4 23.676 20.424 23.76 ;
    END
  END o[361]
  PIN o[362]
    DIRECTION OUTPUT ;
    USE SIGNAL ;
    PORT
      LAYER M5 ;
        RECT  20.496 23.676 20.52 23.76 ;
    END
  END o[362]
  PIN o[363]
    DIRECTION OUTPUT ;
    USE SIGNAL ;
    PORT
      LAYER M5 ;
        RECT  20.592 23.676 20.616 23.76 ;
    END
  END o[363]
  PIN o[364]
    DIRECTION OUTPUT ;
    USE SIGNAL ;
    PORT
      LAYER M5 ;
        RECT  20.688 23.676 20.712 23.76 ;
    END
  END o[364]
  PIN o[365]
    DIRECTION OUTPUT ;
    USE SIGNAL ;
    PORT
      LAYER M5 ;
        RECT  20.784 23.676 20.808 23.76 ;
    END
  END o[365]
  PIN o[366]
    DIRECTION OUTPUT ;
    USE SIGNAL ;
    PORT
      LAYER M5 ;
        RECT  20.88 23.676 20.904 23.76 ;
    END
  END o[366]
  PIN o[367]
    DIRECTION OUTPUT ;
    USE SIGNAL ;
    PORT
      LAYER M5 ;
        RECT  20.976 23.676 21 23.76 ;
    END
  END o[367]
  PIN o[368]
    DIRECTION OUTPUT ;
    USE SIGNAL ;
    PORT
      LAYER M5 ;
        RECT  21.072 23.676 21.096 23.76 ;
    END
  END o[368]
  PIN o[369]
    DIRECTION OUTPUT ;
    USE SIGNAL ;
    PORT
      LAYER M5 ;
        RECT  21.168 23.676 21.192 23.76 ;
    END
  END o[369]
  PIN o[36]
    DIRECTION OUTPUT ;
    USE SIGNAL ;
    PORT
      LAYER M5 ;
        RECT  32.976 23.676 33 23.76 ;
    END
  END o[36]
  PIN o[370]
    DIRECTION OUTPUT ;
    USE SIGNAL ;
    PORT
      LAYER M5 ;
        RECT  21.264 23.676 21.288 23.76 ;
    END
  END o[370]
  PIN o[371]
    DIRECTION OUTPUT ;
    USE SIGNAL ;
    PORT
      LAYER M5 ;
        RECT  21.36 23.676 21.384 23.76 ;
    END
  END o[371]
  PIN o[372]
    DIRECTION OUTPUT ;
    USE SIGNAL ;
    PORT
      LAYER M5 ;
        RECT  21.456 23.676 21.48 23.76 ;
    END
  END o[372]
  PIN o[373]
    DIRECTION OUTPUT ;
    USE SIGNAL ;
    PORT
      LAYER M5 ;
        RECT  21.552 23.676 21.576 23.76 ;
    END
  END o[373]
  PIN o[374]
    DIRECTION OUTPUT ;
    USE SIGNAL ;
    PORT
      LAYER M5 ;
        RECT  21.648 23.676 21.672 23.76 ;
    END
  END o[374]
  PIN o[375]
    DIRECTION OUTPUT ;
    USE SIGNAL ;
    PORT
      LAYER M5 ;
        RECT  21.744 23.676 21.768 23.76 ;
    END
  END o[375]
  PIN o[376]
    DIRECTION OUTPUT ;
    USE SIGNAL ;
    PORT
      LAYER M5 ;
        RECT  21.84 23.676 21.864 23.76 ;
    END
  END o[376]
  PIN o[377]
    DIRECTION OUTPUT ;
    USE SIGNAL ;
    PORT
      LAYER M5 ;
        RECT  21.936 23.676 21.96 23.76 ;
    END
  END o[377]
  PIN o[378]
    DIRECTION OUTPUT ;
    USE SIGNAL ;
    PORT
      LAYER M5 ;
        RECT  22.032 23.676 22.056 23.76 ;
    END
  END o[378]
  PIN o[379]
    DIRECTION OUTPUT ;
    USE SIGNAL ;
    PORT
      LAYER M5 ;
        RECT  22.128 23.676 22.152 23.76 ;
    END
  END o[379]
  PIN o[37]
    DIRECTION OUTPUT ;
    USE SIGNAL ;
    PORT
      LAYER M5 ;
        RECT  33.072 23.676 33.096 23.76 ;
    END
  END o[37]
  PIN o[380]
    DIRECTION OUTPUT ;
    USE SIGNAL ;
    PORT
      LAYER M5 ;
        RECT  22.224 23.676 22.248 23.76 ;
    END
  END o[380]
  PIN o[381]
    DIRECTION OUTPUT ;
    USE SIGNAL ;
    PORT
      LAYER M5 ;
        RECT  22.32 23.676 22.344 23.76 ;
    END
  END o[381]
  PIN o[382]
    DIRECTION OUTPUT ;
    USE SIGNAL ;
    PORT
      LAYER M5 ;
        RECT  22.416 23.676 22.44 23.76 ;
    END
  END o[382]
  PIN o[383]
    DIRECTION OUTPUT ;
    USE SIGNAL ;
    PORT
      LAYER M5 ;
        RECT  22.512 23.676 22.536 23.76 ;
    END
  END o[383]
  PIN o[384]
    DIRECTION OUTPUT ;
    USE SIGNAL ;
    PORT
      LAYER M5 ;
        RECT  13.392 23.676 13.416 23.76 ;
    END
  END o[384]
  PIN o[385]
    DIRECTION OUTPUT ;
    USE SIGNAL ;
    PORT
      LAYER M5 ;
        RECT  13.488 23.676 13.512 23.76 ;
    END
  END o[385]
  PIN o[386]
    DIRECTION OUTPUT ;
    USE SIGNAL ;
    PORT
      LAYER M5 ;
        RECT  13.584 23.676 13.608 23.76 ;
    END
  END o[386]
  PIN o[387]
    DIRECTION OUTPUT ;
    USE SIGNAL ;
    PORT
      LAYER M5 ;
        RECT  13.68 23.676 13.704 23.76 ;
    END
  END o[387]
  PIN o[388]
    DIRECTION OUTPUT ;
    USE SIGNAL ;
    PORT
      LAYER M5 ;
        RECT  13.776 23.676 13.8 23.76 ;
    END
  END o[388]
  PIN o[389]
    DIRECTION OUTPUT ;
    USE SIGNAL ;
    PORT
      LAYER M5 ;
        RECT  13.872 23.676 13.896 23.76 ;
    END
  END o[389]
  PIN o[38]
    DIRECTION OUTPUT ;
    USE SIGNAL ;
    PORT
      LAYER M5 ;
        RECT  33.168 23.676 33.192 23.76 ;
    END
  END o[38]
  PIN o[390]
    DIRECTION OUTPUT ;
    USE SIGNAL ;
    PORT
      LAYER M5 ;
        RECT  13.968 23.676 13.992 23.76 ;
    END
  END o[390]
  PIN o[391]
    DIRECTION OUTPUT ;
    USE SIGNAL ;
    PORT
      LAYER M5 ;
        RECT  14.064 23.676 14.088 23.76 ;
    END
  END o[391]
  PIN o[392]
    DIRECTION OUTPUT ;
    USE SIGNAL ;
    PORT
      LAYER M5 ;
        RECT  14.16 23.676 14.184 23.76 ;
    END
  END o[392]
  PIN o[393]
    DIRECTION OUTPUT ;
    USE SIGNAL ;
    PORT
      LAYER M5 ;
        RECT  14.256 23.676 14.28 23.76 ;
    END
  END o[393]
  PIN o[394]
    DIRECTION OUTPUT ;
    USE SIGNAL ;
    PORT
      LAYER M5 ;
        RECT  14.352 23.676 14.376 23.76 ;
    END
  END o[394]
  PIN o[395]
    DIRECTION OUTPUT ;
    USE SIGNAL ;
    PORT
      LAYER M5 ;
        RECT  14.448 23.676 14.472 23.76 ;
    END
  END o[395]
  PIN o[396]
    DIRECTION OUTPUT ;
    USE SIGNAL ;
    PORT
      LAYER M5 ;
        RECT  14.544 23.676 14.568 23.76 ;
    END
  END o[396]
  PIN o[397]
    DIRECTION OUTPUT ;
    USE SIGNAL ;
    PORT
      LAYER M5 ;
        RECT  14.64 23.676 14.664 23.76 ;
    END
  END o[397]
  PIN o[398]
    DIRECTION OUTPUT ;
    USE SIGNAL ;
    PORT
      LAYER M5 ;
        RECT  14.736 23.676 14.76 23.76 ;
    END
  END o[398]
  PIN o[399]
    DIRECTION OUTPUT ;
    USE SIGNAL ;
    PORT
      LAYER M5 ;
        RECT  14.832 23.676 14.856 23.76 ;
    END
  END o[399]
  PIN o[39]
    DIRECTION OUTPUT ;
    USE SIGNAL ;
    PORT
      LAYER M5 ;
        RECT  33.264 23.676 33.288 23.76 ;
    END
  END o[39]
  PIN o[3]
    DIRECTION OUTPUT ;
    USE SIGNAL ;
    PORT
      LAYER M5 ;
        RECT  35.952 23.676 35.976 23.76 ;
    END
  END o[3]
  PIN o[400]
    DIRECTION OUTPUT ;
    USE SIGNAL ;
    PORT
      LAYER M5 ;
        RECT  14.928 23.676 14.952 23.76 ;
    END
  END o[400]
  PIN o[401]
    DIRECTION OUTPUT ;
    USE SIGNAL ;
    PORT
      LAYER M5 ;
        RECT  15.024 23.676 15.048 23.76 ;
    END
  END o[401]
  PIN o[402]
    DIRECTION OUTPUT ;
    USE SIGNAL ;
    PORT
      LAYER M5 ;
        RECT  15.12 23.676 15.144 23.76 ;
    END
  END o[402]
  PIN o[403]
    DIRECTION OUTPUT ;
    USE SIGNAL ;
    PORT
      LAYER M5 ;
        RECT  15.216 23.676 15.24 23.76 ;
    END
  END o[403]
  PIN o[404]
    DIRECTION OUTPUT ;
    USE SIGNAL ;
    PORT
      LAYER M5 ;
        RECT  15.312 23.676 15.336 23.76 ;
    END
  END o[404]
  PIN o[405]
    DIRECTION OUTPUT ;
    USE SIGNAL ;
    PORT
      LAYER M5 ;
        RECT  15.408 23.676 15.432 23.76 ;
    END
  END o[405]
  PIN o[406]
    DIRECTION OUTPUT ;
    USE SIGNAL ;
    PORT
      LAYER M5 ;
        RECT  15.504 23.676 15.528 23.76 ;
    END
  END o[406]
  PIN o[407]
    DIRECTION OUTPUT ;
    USE SIGNAL ;
    PORT
      LAYER M5 ;
        RECT  15.6 23.676 15.624 23.76 ;
    END
  END o[407]
  PIN o[408]
    DIRECTION OUTPUT ;
    USE SIGNAL ;
    PORT
      LAYER M5 ;
        RECT  15.696 23.676 15.72 23.76 ;
    END
  END o[408]
  PIN o[409]
    DIRECTION OUTPUT ;
    USE SIGNAL ;
    PORT
      LAYER M5 ;
        RECT  15.792 23.676 15.816 23.76 ;
    END
  END o[409]
  PIN o[40]
    DIRECTION OUTPUT ;
    USE SIGNAL ;
    PORT
      LAYER M5 ;
        RECT  33.36 23.676 33.384 23.76 ;
    END
  END o[40]
  PIN o[410]
    DIRECTION OUTPUT ;
    USE SIGNAL ;
    PORT
      LAYER M5 ;
        RECT  15.888 23.676 15.912 23.76 ;
    END
  END o[410]
  PIN o[411]
    DIRECTION OUTPUT ;
    USE SIGNAL ;
    PORT
      LAYER M5 ;
        RECT  15.984 23.676 16.008 23.76 ;
    END
  END o[411]
  PIN o[412]
    DIRECTION OUTPUT ;
    USE SIGNAL ;
    PORT
      LAYER M5 ;
        RECT  16.08 23.676 16.104 23.76 ;
    END
  END o[412]
  PIN o[413]
    DIRECTION OUTPUT ;
    USE SIGNAL ;
    PORT
      LAYER M5 ;
        RECT  16.176 23.676 16.2 23.76 ;
    END
  END o[413]
  PIN o[414]
    DIRECTION OUTPUT ;
    USE SIGNAL ;
    PORT
      LAYER M5 ;
        RECT  16.272 23.676 16.296 23.76 ;
    END
  END o[414]
  PIN o[415]
    DIRECTION OUTPUT ;
    USE SIGNAL ;
    PORT
      LAYER M5 ;
        RECT  16.368 23.676 16.392 23.76 ;
    END
  END o[415]
  PIN o[416]
    DIRECTION OUTPUT ;
    USE SIGNAL ;
    PORT
      LAYER M5 ;
        RECT  16.464 23.676 16.488 23.76 ;
    END
  END o[416]
  PIN o[417]
    DIRECTION OUTPUT ;
    USE SIGNAL ;
    PORT
      LAYER M5 ;
        RECT  16.56 23.676 16.584 23.76 ;
    END
  END o[417]
  PIN o[418]
    DIRECTION OUTPUT ;
    USE SIGNAL ;
    PORT
      LAYER M5 ;
        RECT  16.656 23.676 16.68 23.76 ;
    END
  END o[418]
  PIN o[419]
    DIRECTION OUTPUT ;
    USE SIGNAL ;
    PORT
      LAYER M5 ;
        RECT  16.752 23.676 16.776 23.76 ;
    END
  END o[419]
  PIN o[41]
    DIRECTION OUTPUT ;
    USE SIGNAL ;
    PORT
      LAYER M5 ;
        RECT  33.456 23.676 33.48 23.76 ;
    END
  END o[41]
  PIN o[420]
    DIRECTION OUTPUT ;
    USE SIGNAL ;
    PORT
      LAYER M5 ;
        RECT  16.848 23.676 16.872 23.76 ;
    END
  END o[420]
  PIN o[421]
    DIRECTION OUTPUT ;
    USE SIGNAL ;
    PORT
      LAYER M5 ;
        RECT  16.944 23.676 16.968 23.76 ;
    END
  END o[421]
  PIN o[422]
    DIRECTION OUTPUT ;
    USE SIGNAL ;
    PORT
      LAYER M5 ;
        RECT  17.04 23.676 17.064 23.76 ;
    END
  END o[422]
  PIN o[423]
    DIRECTION OUTPUT ;
    USE SIGNAL ;
    PORT
      LAYER M5 ;
        RECT  17.136 23.676 17.16 23.76 ;
    END
  END o[423]
  PIN o[424]
    DIRECTION OUTPUT ;
    USE SIGNAL ;
    PORT
      LAYER M5 ;
        RECT  17.232 23.676 17.256 23.76 ;
    END
  END o[424]
  PIN o[425]
    DIRECTION OUTPUT ;
    USE SIGNAL ;
    PORT
      LAYER M5 ;
        RECT  17.328 23.676 17.352 23.76 ;
    END
  END o[425]
  PIN o[426]
    DIRECTION OUTPUT ;
    USE SIGNAL ;
    PORT
      LAYER M5 ;
        RECT  17.424 23.676 17.448 23.76 ;
    END
  END o[426]
  PIN o[427]
    DIRECTION OUTPUT ;
    USE SIGNAL ;
    PORT
      LAYER M5 ;
        RECT  17.52 23.676 17.544 23.76 ;
    END
  END o[427]
  PIN o[428]
    DIRECTION OUTPUT ;
    USE SIGNAL ;
    PORT
      LAYER M5 ;
        RECT  17.616 23.676 17.64 23.76 ;
    END
  END o[428]
  PIN o[429]
    DIRECTION OUTPUT ;
    USE SIGNAL ;
    PORT
      LAYER M5 ;
        RECT  17.712 23.676 17.736 23.76 ;
    END
  END o[429]
  PIN o[42]
    DIRECTION OUTPUT ;
    USE SIGNAL ;
    PORT
      LAYER M5 ;
        RECT  33.552 23.676 33.576 23.76 ;
    END
  END o[42]
  PIN o[430]
    DIRECTION OUTPUT ;
    USE SIGNAL ;
    PORT
      LAYER M5 ;
        RECT  17.808 23.676 17.832 23.76 ;
    END
  END o[430]
  PIN o[431]
    DIRECTION OUTPUT ;
    USE SIGNAL ;
    PORT
      LAYER M5 ;
        RECT  17.904 23.676 17.928 23.76 ;
    END
  END o[431]
  PIN o[432]
    DIRECTION OUTPUT ;
    USE SIGNAL ;
    PORT
      LAYER M5 ;
        RECT  18 23.676 18.024 23.76 ;
    END
  END o[432]
  PIN o[433]
    DIRECTION OUTPUT ;
    USE SIGNAL ;
    PORT
      LAYER M5 ;
        RECT  18.096 23.676 18.12 23.76 ;
    END
  END o[433]
  PIN o[434]
    DIRECTION OUTPUT ;
    USE SIGNAL ;
    PORT
      LAYER M5 ;
        RECT  18.192 23.676 18.216 23.76 ;
    END
  END o[434]
  PIN o[435]
    DIRECTION OUTPUT ;
    USE SIGNAL ;
    PORT
      LAYER M5 ;
        RECT  18.288 23.676 18.312 23.76 ;
    END
  END o[435]
  PIN o[436]
    DIRECTION OUTPUT ;
    USE SIGNAL ;
    PORT
      LAYER M5 ;
        RECT  18.384 23.676 18.408 23.76 ;
    END
  END o[436]
  PIN o[437]
    DIRECTION OUTPUT ;
    USE SIGNAL ;
    PORT
      LAYER M5 ;
        RECT  18.48 23.676 18.504 23.76 ;
    END
  END o[437]
  PIN o[438]
    DIRECTION OUTPUT ;
    USE SIGNAL ;
    PORT
      LAYER M5 ;
        RECT  18.576 23.676 18.6 23.76 ;
    END
  END o[438]
  PIN o[439]
    DIRECTION OUTPUT ;
    USE SIGNAL ;
    PORT
      LAYER M5 ;
        RECT  18.672 23.676 18.696 23.76 ;
    END
  END o[439]
  PIN o[43]
    DIRECTION OUTPUT ;
    USE SIGNAL ;
    PORT
      LAYER M5 ;
        RECT  33.648 23.676 33.672 23.76 ;
    END
  END o[43]
  PIN o[440]
    DIRECTION OUTPUT ;
    USE SIGNAL ;
    PORT
      LAYER M5 ;
        RECT  18.768 23.676 18.792 23.76 ;
    END
  END o[440]
  PIN o[441]
    DIRECTION OUTPUT ;
    USE SIGNAL ;
    PORT
      LAYER M5 ;
        RECT  18.864 23.676 18.888 23.76 ;
    END
  END o[441]
  PIN o[442]
    DIRECTION OUTPUT ;
    USE SIGNAL ;
    PORT
      LAYER M5 ;
        RECT  18.96 23.676 18.984 23.76 ;
    END
  END o[442]
  PIN o[443]
    DIRECTION OUTPUT ;
    USE SIGNAL ;
    PORT
      LAYER M5 ;
        RECT  19.056 23.676 19.08 23.76 ;
    END
  END o[443]
  PIN o[444]
    DIRECTION OUTPUT ;
    USE SIGNAL ;
    PORT
      LAYER M5 ;
        RECT  19.152 23.676 19.176 23.76 ;
    END
  END o[444]
  PIN o[445]
    DIRECTION OUTPUT ;
    USE SIGNAL ;
    PORT
      LAYER M5 ;
        RECT  19.248 23.676 19.272 23.76 ;
    END
  END o[445]
  PIN o[446]
    DIRECTION OUTPUT ;
    USE SIGNAL ;
    PORT
      LAYER M5 ;
        RECT  19.344 23.676 19.368 23.76 ;
    END
  END o[446]
  PIN o[447]
    DIRECTION OUTPUT ;
    USE SIGNAL ;
    PORT
      LAYER M5 ;
        RECT  19.44 23.676 19.464 23.76 ;
    END
  END o[447]
  PIN o[448]
    DIRECTION OUTPUT ;
    USE SIGNAL ;
    PORT
      LAYER M5 ;
        RECT  3.408 23.676 3.432 23.76 ;
    END
  END o[448]
  PIN o[449]
    DIRECTION OUTPUT ;
    USE SIGNAL ;
    PORT
      LAYER M5 ;
        RECT  3.504 23.676 3.528 23.76 ;
    END
  END o[449]
  PIN o[44]
    DIRECTION OUTPUT ;
    USE SIGNAL ;
    PORT
      LAYER M5 ;
        RECT  33.744 23.676 33.768 23.76 ;
    END
  END o[44]
  PIN o[450]
    DIRECTION OUTPUT ;
    USE SIGNAL ;
    PORT
      LAYER M5 ;
        RECT  3.6 23.676 3.624 23.76 ;
    END
  END o[450]
  PIN o[451]
    DIRECTION OUTPUT ;
    USE SIGNAL ;
    PORT
      LAYER M5 ;
        RECT  3.696 23.676 3.72 23.76 ;
    END
  END o[451]
  PIN o[452]
    DIRECTION OUTPUT ;
    USE SIGNAL ;
    PORT
      LAYER M5 ;
        RECT  3.792 23.676 3.816 23.76 ;
    END
  END o[452]
  PIN o[453]
    DIRECTION OUTPUT ;
    USE SIGNAL ;
    PORT
      LAYER M5 ;
        RECT  3.888 23.676 3.912 23.76 ;
    END
  END o[453]
  PIN o[454]
    DIRECTION OUTPUT ;
    USE SIGNAL ;
    PORT
      LAYER M5 ;
        RECT  3.984 23.676 4.008 23.76 ;
    END
  END o[454]
  PIN o[455]
    DIRECTION OUTPUT ;
    USE SIGNAL ;
    PORT
      LAYER M5 ;
        RECT  4.08 23.676 4.104 23.76 ;
    END
  END o[455]
  PIN o[456]
    DIRECTION OUTPUT ;
    USE SIGNAL ;
    PORT
      LAYER M5 ;
        RECT  4.176 23.676 4.2 23.76 ;
    END
  END o[456]
  PIN o[457]
    DIRECTION OUTPUT ;
    USE SIGNAL ;
    PORT
      LAYER M5 ;
        RECT  4.272 23.676 4.296 23.76 ;
    END
  END o[457]
  PIN o[458]
    DIRECTION OUTPUT ;
    USE SIGNAL ;
    PORT
      LAYER M5 ;
        RECT  4.368 23.676 4.392 23.76 ;
    END
  END o[458]
  PIN o[459]
    DIRECTION OUTPUT ;
    USE SIGNAL ;
    PORT
      LAYER M5 ;
        RECT  4.464 23.676 4.488 23.76 ;
    END
  END o[459]
  PIN o[45]
    DIRECTION OUTPUT ;
    USE SIGNAL ;
    PORT
      LAYER M5 ;
        RECT  33.84 23.676 33.864 23.76 ;
    END
  END o[45]
  PIN o[460]
    DIRECTION OUTPUT ;
    USE SIGNAL ;
    PORT
      LAYER M5 ;
        RECT  4.56 23.676 4.584 23.76 ;
    END
  END o[460]
  PIN o[461]
    DIRECTION OUTPUT ;
    USE SIGNAL ;
    PORT
      LAYER M5 ;
        RECT  4.656 23.676 4.68 23.76 ;
    END
  END o[461]
  PIN o[462]
    DIRECTION OUTPUT ;
    USE SIGNAL ;
    PORT
      LAYER M5 ;
        RECT  4.752 23.676 4.776 23.76 ;
    END
  END o[462]
  PIN o[463]
    DIRECTION OUTPUT ;
    USE SIGNAL ;
    PORT
      LAYER M5 ;
        RECT  4.848 23.676 4.872 23.76 ;
    END
  END o[463]
  PIN o[464]
    DIRECTION OUTPUT ;
    USE SIGNAL ;
    PORT
      LAYER M5 ;
        RECT  4.944 23.676 4.968 23.76 ;
    END
  END o[464]
  PIN o[465]
    DIRECTION OUTPUT ;
    USE SIGNAL ;
    PORT
      LAYER M5 ;
        RECT  5.04 23.676 5.064 23.76 ;
    END
  END o[465]
  PIN o[466]
    DIRECTION OUTPUT ;
    USE SIGNAL ;
    PORT
      LAYER M5 ;
        RECT  5.136 23.676 5.16 23.76 ;
    END
  END o[466]
  PIN o[467]
    DIRECTION OUTPUT ;
    USE SIGNAL ;
    PORT
      LAYER M5 ;
        RECT  5.232 23.676 5.256 23.76 ;
    END
  END o[467]
  PIN o[468]
    DIRECTION OUTPUT ;
    USE SIGNAL ;
    PORT
      LAYER M5 ;
        RECT  5.328 23.676 5.352 23.76 ;
    END
  END o[468]
  PIN o[469]
    DIRECTION OUTPUT ;
    USE SIGNAL ;
    PORT
      LAYER M5 ;
        RECT  5.424 23.676 5.448 23.76 ;
    END
  END o[469]
  PIN o[46]
    DIRECTION OUTPUT ;
    USE SIGNAL ;
    PORT
      LAYER M5 ;
        RECT  33.936 23.676 33.96 23.76 ;
    END
  END o[46]
  PIN o[470]
    DIRECTION OUTPUT ;
    USE SIGNAL ;
    PORT
      LAYER M5 ;
        RECT  5.52 23.676 5.544 23.76 ;
    END
  END o[470]
  PIN o[471]
    DIRECTION OUTPUT ;
    USE SIGNAL ;
    PORT
      LAYER M5 ;
        RECT  5.616 23.676 5.64 23.76 ;
    END
  END o[471]
  PIN o[472]
    DIRECTION OUTPUT ;
    USE SIGNAL ;
    PORT
      LAYER M5 ;
        RECT  5.712 23.676 5.736 23.76 ;
    END
  END o[472]
  PIN o[473]
    DIRECTION OUTPUT ;
    USE SIGNAL ;
    PORT
      LAYER M5 ;
        RECT  5.808 23.676 5.832 23.76 ;
    END
  END o[473]
  PIN o[474]
    DIRECTION OUTPUT ;
    USE SIGNAL ;
    PORT
      LAYER M5 ;
        RECT  5.904 23.676 5.928 23.76 ;
    END
  END o[474]
  PIN o[475]
    DIRECTION OUTPUT ;
    USE SIGNAL ;
    PORT
      LAYER M5 ;
        RECT  6 23.676 6.024 23.76 ;
    END
  END o[475]
  PIN o[476]
    DIRECTION OUTPUT ;
    USE SIGNAL ;
    PORT
      LAYER M5 ;
        RECT  6.096 23.676 6.12 23.76 ;
    END
  END o[476]
  PIN o[477]
    DIRECTION OUTPUT ;
    USE SIGNAL ;
    PORT
      LAYER M5 ;
        RECT  6.192 23.676 6.216 23.76 ;
    END
  END o[477]
  PIN o[478]
    DIRECTION OUTPUT ;
    USE SIGNAL ;
    PORT
      LAYER M5 ;
        RECT  6.288 23.676 6.312 23.76 ;
    END
  END o[478]
  PIN o[479]
    DIRECTION OUTPUT ;
    USE SIGNAL ;
    PORT
      LAYER M5 ;
        RECT  6.384 23.676 6.408 23.76 ;
    END
  END o[479]
  PIN o[47]
    DIRECTION OUTPUT ;
    USE SIGNAL ;
    PORT
      LAYER M5 ;
        RECT  34.032 23.676 34.056 23.76 ;
    END
  END o[47]
  PIN o[480]
    DIRECTION OUTPUT ;
    USE SIGNAL ;
    PORT
      LAYER M5 ;
        RECT  45.648 23.676 45.672 23.76 ;
    END
  END o[480]
  PIN o[481]
    DIRECTION OUTPUT ;
    USE SIGNAL ;
    PORT
      LAYER M5 ;
        RECT  45.744 23.676 45.768 23.76 ;
    END
  END o[481]
  PIN o[482]
    DIRECTION OUTPUT ;
    USE SIGNAL ;
    PORT
      LAYER M5 ;
        RECT  45.84 23.676 45.864 23.76 ;
    END
  END o[482]
  PIN o[483]
    DIRECTION OUTPUT ;
    USE SIGNAL ;
    PORT
      LAYER M5 ;
        RECT  45.936 23.676 45.96 23.76 ;
    END
  END o[483]
  PIN o[484]
    DIRECTION OUTPUT ;
    USE SIGNAL ;
    PORT
      LAYER M5 ;
        RECT  46.032 23.676 46.056 23.76 ;
    END
  END o[484]
  PIN o[485]
    DIRECTION OUTPUT ;
    USE SIGNAL ;
    PORT
      LAYER M5 ;
        RECT  46.128 23.676 46.152 23.76 ;
    END
  END o[485]
  PIN o[486]
    DIRECTION OUTPUT ;
    USE SIGNAL ;
    PORT
      LAYER M5 ;
        RECT  46.224 23.676 46.248 23.76 ;
    END
  END o[486]
  PIN o[487]
    DIRECTION OUTPUT ;
    USE SIGNAL ;
    PORT
      LAYER M5 ;
        RECT  46.32 23.676 46.344 23.76 ;
    END
  END o[487]
  PIN o[488]
    DIRECTION OUTPUT ;
    USE SIGNAL ;
    PORT
      LAYER M5 ;
        RECT  46.416 23.676 46.44 23.76 ;
    END
  END o[488]
  PIN o[489]
    DIRECTION OUTPUT ;
    USE SIGNAL ;
    PORT
      LAYER M5 ;
        RECT  46.512 23.676 46.536 23.76 ;
    END
  END o[489]
  PIN o[48]
    DIRECTION OUTPUT ;
    USE SIGNAL ;
    PORT
      LAYER M5 ;
        RECT  34.128 23.676 34.152 23.76 ;
    END
  END o[48]
  PIN o[490]
    DIRECTION OUTPUT ;
    USE SIGNAL ;
    PORT
      LAYER M5 ;
        RECT  46.608 23.676 46.632 23.76 ;
    END
  END o[490]
  PIN o[491]
    DIRECTION OUTPUT ;
    USE SIGNAL ;
    PORT
      LAYER M5 ;
        RECT  46.704 23.676 46.728 23.76 ;
    END
  END o[491]
  PIN o[492]
    DIRECTION OUTPUT ;
    USE SIGNAL ;
    PORT
      LAYER M5 ;
        RECT  46.8 23.676 46.824 23.76 ;
    END
  END o[492]
  PIN o[493]
    DIRECTION OUTPUT ;
    USE SIGNAL ;
    PORT
      LAYER M5 ;
        RECT  46.896 23.676 46.92 23.76 ;
    END
  END o[493]
  PIN o[494]
    DIRECTION OUTPUT ;
    USE SIGNAL ;
    PORT
      LAYER M5 ;
        RECT  46.992 23.676 47.016 23.76 ;
    END
  END o[494]
  PIN o[495]
    DIRECTION OUTPUT ;
    USE SIGNAL ;
    PORT
      LAYER M5 ;
        RECT  47.088 23.676 47.112 23.76 ;
    END
  END o[495]
  PIN o[496]
    DIRECTION OUTPUT ;
    USE SIGNAL ;
    PORT
      LAYER M5 ;
        RECT  47.184 23.676 47.208 23.76 ;
    END
  END o[496]
  PIN o[497]
    DIRECTION OUTPUT ;
    USE SIGNAL ;
    PORT
      LAYER M5 ;
        RECT  47.28 23.676 47.304 23.76 ;
    END
  END o[497]
  PIN o[498]
    DIRECTION OUTPUT ;
    USE SIGNAL ;
    PORT
      LAYER M5 ;
        RECT  47.376 23.676 47.4 23.76 ;
    END
  END o[498]
  PIN o[499]
    DIRECTION OUTPUT ;
    USE SIGNAL ;
    PORT
      LAYER M5 ;
        RECT  47.472 23.676 47.496 23.76 ;
    END
  END o[499]
  PIN o[49]
    DIRECTION OUTPUT ;
    USE SIGNAL ;
    PORT
      LAYER M5 ;
        RECT  34.224 23.676 34.248 23.76 ;
    END
  END o[49]
  PIN o[4]
    DIRECTION OUTPUT ;
    USE SIGNAL ;
    PORT
      LAYER M5 ;
        RECT  36.048 23.676 36.072 23.76 ;
    END
  END o[4]
  PIN o[500]
    DIRECTION OUTPUT ;
    USE SIGNAL ;
    PORT
      LAYER M5 ;
        RECT  47.568 23.676 47.592 23.76 ;
    END
  END o[500]
  PIN o[501]
    DIRECTION OUTPUT ;
    USE SIGNAL ;
    PORT
      LAYER M5 ;
        RECT  47.664 23.676 47.688 23.76 ;
    END
  END o[501]
  PIN o[502]
    DIRECTION OUTPUT ;
    USE SIGNAL ;
    PORT
      LAYER M5 ;
        RECT  47.76 23.676 47.784 23.76 ;
    END
  END o[502]
  PIN o[503]
    DIRECTION OUTPUT ;
    USE SIGNAL ;
    PORT
      LAYER M5 ;
        RECT  47.856 23.676 47.88 23.76 ;
    END
  END o[503]
  PIN o[504]
    DIRECTION OUTPUT ;
    USE SIGNAL ;
    PORT
      LAYER M5 ;
        RECT  47.952 23.676 47.976 23.76 ;
    END
  END o[504]
  PIN o[505]
    DIRECTION OUTPUT ;
    USE SIGNAL ;
    PORT
      LAYER M5 ;
        RECT  48.048 23.676 48.072 23.76 ;
    END
  END o[505]
  PIN o[506]
    DIRECTION OUTPUT ;
    USE SIGNAL ;
    PORT
      LAYER M5 ;
        RECT  48.144 23.676 48.168 23.76 ;
    END
  END o[506]
  PIN o[507]
    DIRECTION OUTPUT ;
    USE SIGNAL ;
    PORT
      LAYER M5 ;
        RECT  48.24 23.676 48.264 23.76 ;
    END
  END o[507]
  PIN o[508]
    DIRECTION OUTPUT ;
    USE SIGNAL ;
    PORT
      LAYER M5 ;
        RECT  48.336 23.676 48.36 23.76 ;
    END
  END o[508]
  PIN o[509]
    DIRECTION OUTPUT ;
    USE SIGNAL ;
    PORT
      LAYER M5 ;
        RECT  48.432 23.676 48.456 23.76 ;
    END
  END o[509]
  PIN o[50]
    DIRECTION OUTPUT ;
    USE SIGNAL ;
    PORT
      LAYER M5 ;
        RECT  34.32 23.676 34.344 23.76 ;
    END
  END o[50]
  PIN o[510]
    DIRECTION OUTPUT ;
    USE SIGNAL ;
    PORT
      LAYER M5 ;
        RECT  48.528 23.676 48.552 23.76 ;
    END
  END o[510]
  PIN o[511]
    DIRECTION OUTPUT ;
    USE SIGNAL ;
    PORT
      LAYER M5 ;
        RECT  48.624 23.676 48.648 23.76 ;
    END
  END o[511]
  PIN o[512]
    DIRECTION OUTPUT ;
    USE SIGNAL ;
    PORT
      LAYER M5 ;
        RECT  54.864 23.676 54.888 23.76 ;
    END
  END o[512]
  PIN o[513]
    DIRECTION OUTPUT ;
    USE SIGNAL ;
    PORT
      LAYER M5 ;
        RECT  54.96 23.676 54.984 23.76 ;
    END
  END o[513]
  PIN o[514]
    DIRECTION OUTPUT ;
    USE SIGNAL ;
    PORT
      LAYER M5 ;
        RECT  55.056 23.676 55.08 23.76 ;
    END
  END o[514]
  PIN o[515]
    DIRECTION OUTPUT ;
    USE SIGNAL ;
    PORT
      LAYER M5 ;
        RECT  55.152 23.676 55.176 23.76 ;
    END
  END o[515]
  PIN o[516]
    DIRECTION OUTPUT ;
    USE SIGNAL ;
    PORT
      LAYER M5 ;
        RECT  55.248 23.676 55.272 23.76 ;
    END
  END o[516]
  PIN o[517]
    DIRECTION OUTPUT ;
    USE SIGNAL ;
    PORT
      LAYER M5 ;
        RECT  55.344 23.676 55.368 23.76 ;
    END
  END o[517]
  PIN o[518]
    DIRECTION OUTPUT ;
    USE SIGNAL ;
    PORT
      LAYER M5 ;
        RECT  55.44 23.676 55.464 23.76 ;
    END
  END o[518]
  PIN o[519]
    DIRECTION OUTPUT ;
    USE SIGNAL ;
    PORT
      LAYER M5 ;
        RECT  55.536 23.676 55.56 23.76 ;
    END
  END o[519]
  PIN o[51]
    DIRECTION OUTPUT ;
    USE SIGNAL ;
    PORT
      LAYER M5 ;
        RECT  34.416 23.676 34.44 23.76 ;
    END
  END o[51]
  PIN o[520]
    DIRECTION OUTPUT ;
    USE SIGNAL ;
    PORT
      LAYER M5 ;
        RECT  55.632 23.676 55.656 23.76 ;
    END
  END o[520]
  PIN o[521]
    DIRECTION OUTPUT ;
    USE SIGNAL ;
    PORT
      LAYER M5 ;
        RECT  55.728 23.676 55.752 23.76 ;
    END
  END o[521]
  PIN o[522]
    DIRECTION OUTPUT ;
    USE SIGNAL ;
    PORT
      LAYER M5 ;
        RECT  55.824 23.676 55.848 23.76 ;
    END
  END o[522]
  PIN o[523]
    DIRECTION OUTPUT ;
    USE SIGNAL ;
    PORT
      LAYER M5 ;
        RECT  55.92 23.676 55.944 23.76 ;
    END
  END o[523]
  PIN o[524]
    DIRECTION OUTPUT ;
    USE SIGNAL ;
    PORT
      LAYER M5 ;
        RECT  56.016 23.676 56.04 23.76 ;
    END
  END o[524]
  PIN o[525]
    DIRECTION OUTPUT ;
    USE SIGNAL ;
    PORT
      LAYER M5 ;
        RECT  56.112 23.676 56.136 23.76 ;
    END
  END o[525]
  PIN o[526]
    DIRECTION OUTPUT ;
    USE SIGNAL ;
    PORT
      LAYER M5 ;
        RECT  56.208 23.676 56.232 23.76 ;
    END
  END o[526]
  PIN o[527]
    DIRECTION OUTPUT ;
    USE SIGNAL ;
    PORT
      LAYER M5 ;
        RECT  56.304 23.676 56.328 23.76 ;
    END
  END o[527]
  PIN o[528]
    DIRECTION OUTPUT ;
    USE SIGNAL ;
    PORT
      LAYER M5 ;
        RECT  56.4 23.676 56.424 23.76 ;
    END
  END o[528]
  PIN o[529]
    DIRECTION OUTPUT ;
    USE SIGNAL ;
    PORT
      LAYER M5 ;
        RECT  56.496 23.676 56.52 23.76 ;
    END
  END o[529]
  PIN o[52]
    DIRECTION OUTPUT ;
    USE SIGNAL ;
    PORT
      LAYER M5 ;
        RECT  34.512 23.676 34.536 23.76 ;
    END
  END o[52]
  PIN o[530]
    DIRECTION OUTPUT ;
    USE SIGNAL ;
    PORT
      LAYER M5 ;
        RECT  56.592 23.676 56.616 23.76 ;
    END
  END o[530]
  PIN o[531]
    DIRECTION OUTPUT ;
    USE SIGNAL ;
    PORT
      LAYER M5 ;
        RECT  56.688 23.676 56.712 23.76 ;
    END
  END o[531]
  PIN o[532]
    DIRECTION OUTPUT ;
    USE SIGNAL ;
    PORT
      LAYER M5 ;
        RECT  56.784 23.676 56.808 23.76 ;
    END
  END o[532]
  PIN o[533]
    DIRECTION OUTPUT ;
    USE SIGNAL ;
    PORT
      LAYER M5 ;
        RECT  56.88 23.676 56.904 23.76 ;
    END
  END o[533]
  PIN o[534]
    DIRECTION OUTPUT ;
    USE SIGNAL ;
    PORT
      LAYER M5 ;
        RECT  56.976 23.676 57 23.76 ;
    END
  END o[534]
  PIN o[535]
    DIRECTION OUTPUT ;
    USE SIGNAL ;
    PORT
      LAYER M5 ;
        RECT  57.072 23.676 57.096 23.76 ;
    END
  END o[535]
  PIN o[536]
    DIRECTION OUTPUT ;
    USE SIGNAL ;
    PORT
      LAYER M5 ;
        RECT  57.168 23.676 57.192 23.76 ;
    END
  END o[536]
  PIN o[537]
    DIRECTION OUTPUT ;
    USE SIGNAL ;
    PORT
      LAYER M5 ;
        RECT  57.264 23.676 57.288 23.76 ;
    END
  END o[537]
  PIN o[538]
    DIRECTION OUTPUT ;
    USE SIGNAL ;
    PORT
      LAYER M5 ;
        RECT  57.36 23.676 57.384 23.76 ;
    END
  END o[538]
  PIN o[539]
    DIRECTION OUTPUT ;
    USE SIGNAL ;
    PORT
      LAYER M5 ;
        RECT  57.456 23.676 57.48 23.76 ;
    END
  END o[539]
  PIN o[53]
    DIRECTION OUTPUT ;
    USE SIGNAL ;
    PORT
      LAYER M5 ;
        RECT  34.608 23.676 34.632 23.76 ;
    END
  END o[53]
  PIN o[540]
    DIRECTION OUTPUT ;
    USE SIGNAL ;
    PORT
      LAYER M5 ;
        RECT  57.552 23.676 57.576 23.76 ;
    END
  END o[540]
  PIN o[541]
    DIRECTION OUTPUT ;
    USE SIGNAL ;
    PORT
      LAYER M5 ;
        RECT  57.648 23.676 57.672 23.76 ;
    END
  END o[541]
  PIN o[542]
    DIRECTION OUTPUT ;
    USE SIGNAL ;
    PORT
      LAYER M5 ;
        RECT  57.744 23.676 57.768 23.76 ;
    END
  END o[542]
  PIN o[543]
    DIRECTION OUTPUT ;
    USE SIGNAL ;
    PORT
      LAYER M5 ;
        RECT  57.84 23.676 57.864 23.76 ;
    END
  END o[543]
  PIN o[544]
    DIRECTION OUTPUT ;
    USE SIGNAL ;
    PORT
      LAYER M5 ;
        RECT  48.72 23.676 48.744 23.76 ;
    END
  END o[544]
  PIN o[545]
    DIRECTION OUTPUT ;
    USE SIGNAL ;
    PORT
      LAYER M5 ;
        RECT  48.816 23.676 48.84 23.76 ;
    END
  END o[545]
  PIN o[546]
    DIRECTION OUTPUT ;
    USE SIGNAL ;
    PORT
      LAYER M5 ;
        RECT  48.912 23.676 48.936 23.76 ;
    END
  END o[546]
  PIN o[547]
    DIRECTION OUTPUT ;
    USE SIGNAL ;
    PORT
      LAYER M5 ;
        RECT  49.008 23.676 49.032 23.76 ;
    END
  END o[547]
  PIN o[548]
    DIRECTION OUTPUT ;
    USE SIGNAL ;
    PORT
      LAYER M5 ;
        RECT  49.104 23.676 49.128 23.76 ;
    END
  END o[548]
  PIN o[549]
    DIRECTION OUTPUT ;
    USE SIGNAL ;
    PORT
      LAYER M5 ;
        RECT  49.2 23.676 49.224 23.76 ;
    END
  END o[549]
  PIN o[54]
    DIRECTION OUTPUT ;
    USE SIGNAL ;
    PORT
      LAYER M5 ;
        RECT  34.704 23.676 34.728 23.76 ;
    END
  END o[54]
  PIN o[550]
    DIRECTION OUTPUT ;
    USE SIGNAL ;
    PORT
      LAYER M5 ;
        RECT  49.296 23.676 49.32 23.76 ;
    END
  END o[550]
  PIN o[551]
    DIRECTION OUTPUT ;
    USE SIGNAL ;
    PORT
      LAYER M5 ;
        RECT  49.392 23.676 49.416 23.76 ;
    END
  END o[551]
  PIN o[552]
    DIRECTION OUTPUT ;
    USE SIGNAL ;
    PORT
      LAYER M5 ;
        RECT  49.488 23.676 49.512 23.76 ;
    END
  END o[552]
  PIN o[553]
    DIRECTION OUTPUT ;
    USE SIGNAL ;
    PORT
      LAYER M5 ;
        RECT  49.584 23.676 49.608 23.76 ;
    END
  END o[553]
  PIN o[554]
    DIRECTION OUTPUT ;
    USE SIGNAL ;
    PORT
      LAYER M5 ;
        RECT  49.68 23.676 49.704 23.76 ;
    END
  END o[554]
  PIN o[555]
    DIRECTION OUTPUT ;
    USE SIGNAL ;
    PORT
      LAYER M5 ;
        RECT  49.776 23.676 49.8 23.76 ;
    END
  END o[555]
  PIN o[556]
    DIRECTION OUTPUT ;
    USE SIGNAL ;
    PORT
      LAYER M5 ;
        RECT  49.872 23.676 49.896 23.76 ;
    END
  END o[556]
  PIN o[557]
    DIRECTION OUTPUT ;
    USE SIGNAL ;
    PORT
      LAYER M5 ;
        RECT  49.968 23.676 49.992 23.76 ;
    END
  END o[557]
  PIN o[558]
    DIRECTION OUTPUT ;
    USE SIGNAL ;
    PORT
      LAYER M5 ;
        RECT  50.064 23.676 50.088 23.76 ;
    END
  END o[558]
  PIN o[559]
    DIRECTION OUTPUT ;
    USE SIGNAL ;
    PORT
      LAYER M5 ;
        RECT  50.16 23.676 50.184 23.76 ;
    END
  END o[559]
  PIN o[55]
    DIRECTION OUTPUT ;
    USE SIGNAL ;
    PORT
      LAYER M5 ;
        RECT  34.8 23.676 34.824 23.76 ;
    END
  END o[55]
  PIN o[560]
    DIRECTION OUTPUT ;
    USE SIGNAL ;
    PORT
      LAYER M5 ;
        RECT  50.256 23.676 50.28 23.76 ;
    END
  END o[560]
  PIN o[561]
    DIRECTION OUTPUT ;
    USE SIGNAL ;
    PORT
      LAYER M5 ;
        RECT  50.352 23.676 50.376 23.76 ;
    END
  END o[561]
  PIN o[562]
    DIRECTION OUTPUT ;
    USE SIGNAL ;
    PORT
      LAYER M5 ;
        RECT  50.448 23.676 50.472 23.76 ;
    END
  END o[562]
  PIN o[563]
    DIRECTION OUTPUT ;
    USE SIGNAL ;
    PORT
      LAYER M5 ;
        RECT  50.544 23.676 50.568 23.76 ;
    END
  END o[563]
  PIN o[564]
    DIRECTION OUTPUT ;
    USE SIGNAL ;
    PORT
      LAYER M5 ;
        RECT  50.64 23.676 50.664 23.76 ;
    END
  END o[564]
  PIN o[565]
    DIRECTION OUTPUT ;
    USE SIGNAL ;
    PORT
      LAYER M5 ;
        RECT  50.736 23.676 50.76 23.76 ;
    END
  END o[565]
  PIN o[566]
    DIRECTION OUTPUT ;
    USE SIGNAL ;
    PORT
      LAYER M5 ;
        RECT  50.832 23.676 50.856 23.76 ;
    END
  END o[566]
  PIN o[567]
    DIRECTION OUTPUT ;
    USE SIGNAL ;
    PORT
      LAYER M5 ;
        RECT  50.928 23.676 50.952 23.76 ;
    END
  END o[567]
  PIN o[568]
    DIRECTION OUTPUT ;
    USE SIGNAL ;
    PORT
      LAYER M5 ;
        RECT  51.024 23.676 51.048 23.76 ;
    END
  END o[568]
  PIN o[569]
    DIRECTION OUTPUT ;
    USE SIGNAL ;
    PORT
      LAYER M5 ;
        RECT  51.12 23.676 51.144 23.76 ;
    END
  END o[569]
  PIN o[56]
    DIRECTION OUTPUT ;
    USE SIGNAL ;
    PORT
      LAYER M5 ;
        RECT  34.896 23.676 34.92 23.76 ;
    END
  END o[56]
  PIN o[570]
    DIRECTION OUTPUT ;
    USE SIGNAL ;
    PORT
      LAYER M5 ;
        RECT  51.216 23.676 51.24 23.76 ;
    END
  END o[570]
  PIN o[571]
    DIRECTION OUTPUT ;
    USE SIGNAL ;
    PORT
      LAYER M5 ;
        RECT  51.312 23.676 51.336 23.76 ;
    END
  END o[571]
  PIN o[572]
    DIRECTION OUTPUT ;
    USE SIGNAL ;
    PORT
      LAYER M5 ;
        RECT  51.408 23.676 51.432 23.76 ;
    END
  END o[572]
  PIN o[573]
    DIRECTION OUTPUT ;
    USE SIGNAL ;
    PORT
      LAYER M5 ;
        RECT  51.504 23.676 51.528 23.76 ;
    END
  END o[573]
  PIN o[574]
    DIRECTION OUTPUT ;
    USE SIGNAL ;
    PORT
      LAYER M5 ;
        RECT  51.6 23.676 51.624 23.76 ;
    END
  END o[574]
  PIN o[575]
    DIRECTION OUTPUT ;
    USE SIGNAL ;
    PORT
      LAYER M5 ;
        RECT  51.696 23.676 51.72 23.76 ;
    END
  END o[575]
  PIN o[576]
    DIRECTION OUTPUT ;
    USE SIGNAL ;
    PORT
      LAYER M5 ;
        RECT  51.792 23.676 51.816 23.76 ;
    END
  END o[576]
  PIN o[577]
    DIRECTION OUTPUT ;
    USE SIGNAL ;
    PORT
      LAYER M5 ;
        RECT  51.888 23.676 51.912 23.76 ;
    END
  END o[577]
  PIN o[578]
    DIRECTION OUTPUT ;
    USE SIGNAL ;
    PORT
      LAYER M5 ;
        RECT  51.984 23.676 52.008 23.76 ;
    END
  END o[578]
  PIN o[579]
    DIRECTION OUTPUT ;
    USE SIGNAL ;
    PORT
      LAYER M5 ;
        RECT  52.08 23.676 52.104 23.76 ;
    END
  END o[579]
  PIN o[57]
    DIRECTION OUTPUT ;
    USE SIGNAL ;
    PORT
      LAYER M5 ;
        RECT  34.992 23.676 35.016 23.76 ;
    END
  END o[57]
  PIN o[580]
    DIRECTION OUTPUT ;
    USE SIGNAL ;
    PORT
      LAYER M5 ;
        RECT  52.176 23.676 52.2 23.76 ;
    END
  END o[580]
  PIN o[581]
    DIRECTION OUTPUT ;
    USE SIGNAL ;
    PORT
      LAYER M5 ;
        RECT  52.272 23.676 52.296 23.76 ;
    END
  END o[581]
  PIN o[582]
    DIRECTION OUTPUT ;
    USE SIGNAL ;
    PORT
      LAYER M5 ;
        RECT  52.368 23.676 52.392 23.76 ;
    END
  END o[582]
  PIN o[583]
    DIRECTION OUTPUT ;
    USE SIGNAL ;
    PORT
      LAYER M5 ;
        RECT  52.464 23.676 52.488 23.76 ;
    END
  END o[583]
  PIN o[584]
    DIRECTION OUTPUT ;
    USE SIGNAL ;
    PORT
      LAYER M5 ;
        RECT  52.56 23.676 52.584 23.76 ;
    END
  END o[584]
  PIN o[585]
    DIRECTION OUTPUT ;
    USE SIGNAL ;
    PORT
      LAYER M5 ;
        RECT  52.656 23.676 52.68 23.76 ;
    END
  END o[585]
  PIN o[586]
    DIRECTION OUTPUT ;
    USE SIGNAL ;
    PORT
      LAYER M5 ;
        RECT  52.752 23.676 52.776 23.76 ;
    END
  END o[586]
  PIN o[587]
    DIRECTION OUTPUT ;
    USE SIGNAL ;
    PORT
      LAYER M5 ;
        RECT  52.848 23.676 52.872 23.76 ;
    END
  END o[587]
  PIN o[588]
    DIRECTION OUTPUT ;
    USE SIGNAL ;
    PORT
      LAYER M5 ;
        RECT  52.944 23.676 52.968 23.76 ;
    END
  END o[588]
  PIN o[589]
    DIRECTION OUTPUT ;
    USE SIGNAL ;
    PORT
      LAYER M5 ;
        RECT  53.04 23.676 53.064 23.76 ;
    END
  END o[589]
  PIN o[58]
    DIRECTION OUTPUT ;
    USE SIGNAL ;
    PORT
      LAYER M5 ;
        RECT  35.088 23.676 35.112 23.76 ;
    END
  END o[58]
  PIN o[590]
    DIRECTION OUTPUT ;
    USE SIGNAL ;
    PORT
      LAYER M5 ;
        RECT  53.136 23.676 53.16 23.76 ;
    END
  END o[590]
  PIN o[591]
    DIRECTION OUTPUT ;
    USE SIGNAL ;
    PORT
      LAYER M5 ;
        RECT  53.232 23.676 53.256 23.76 ;
    END
  END o[591]
  PIN o[592]
    DIRECTION OUTPUT ;
    USE SIGNAL ;
    PORT
      LAYER M5 ;
        RECT  53.328 23.676 53.352 23.76 ;
    END
  END o[592]
  PIN o[593]
    DIRECTION OUTPUT ;
    USE SIGNAL ;
    PORT
      LAYER M5 ;
        RECT  53.424 23.676 53.448 23.76 ;
    END
  END o[593]
  PIN o[594]
    DIRECTION OUTPUT ;
    USE SIGNAL ;
    PORT
      LAYER M5 ;
        RECT  53.52 23.676 53.544 23.76 ;
    END
  END o[594]
  PIN o[595]
    DIRECTION OUTPUT ;
    USE SIGNAL ;
    PORT
      LAYER M5 ;
        RECT  53.616 23.676 53.64 23.76 ;
    END
  END o[595]
  PIN o[596]
    DIRECTION OUTPUT ;
    USE SIGNAL ;
    PORT
      LAYER M5 ;
        RECT  53.712 23.676 53.736 23.76 ;
    END
  END o[596]
  PIN o[597]
    DIRECTION OUTPUT ;
    USE SIGNAL ;
    PORT
      LAYER M5 ;
        RECT  53.808 23.676 53.832 23.76 ;
    END
  END o[597]
  PIN o[598]
    DIRECTION OUTPUT ;
    USE SIGNAL ;
    PORT
      LAYER M5 ;
        RECT  53.904 23.676 53.928 23.76 ;
    END
  END o[598]
  PIN o[599]
    DIRECTION OUTPUT ;
    USE SIGNAL ;
    PORT
      LAYER M5 ;
        RECT  54 23.676 54.024 23.76 ;
    END
  END o[599]
  PIN o[59]
    DIRECTION OUTPUT ;
    USE SIGNAL ;
    PORT
      LAYER M5 ;
        RECT  35.184 23.676 35.208 23.76 ;
    END
  END o[59]
  PIN o[5]
    DIRECTION OUTPUT ;
    USE SIGNAL ;
    PORT
      LAYER M5 ;
        RECT  36.144 23.676 36.168 23.76 ;
    END
  END o[5]
  PIN o[600]
    DIRECTION OUTPUT ;
    USE SIGNAL ;
    PORT
      LAYER M5 ;
        RECT  54.096 23.676 54.12 23.76 ;
    END
  END o[600]
  PIN o[601]
    DIRECTION OUTPUT ;
    USE SIGNAL ;
    PORT
      LAYER M5 ;
        RECT  54.192 23.676 54.216 23.76 ;
    END
  END o[601]
  PIN o[602]
    DIRECTION OUTPUT ;
    USE SIGNAL ;
    PORT
      LAYER M5 ;
        RECT  54.288 23.676 54.312 23.76 ;
    END
  END o[602]
  PIN o[603]
    DIRECTION OUTPUT ;
    USE SIGNAL ;
    PORT
      LAYER M5 ;
        RECT  54.384 23.676 54.408 23.76 ;
    END
  END o[603]
  PIN o[604]
    DIRECTION OUTPUT ;
    USE SIGNAL ;
    PORT
      LAYER M5 ;
        RECT  54.48 23.676 54.504 23.76 ;
    END
  END o[604]
  PIN o[605]
    DIRECTION OUTPUT ;
    USE SIGNAL ;
    PORT
      LAYER M5 ;
        RECT  54.576 23.676 54.6 23.76 ;
    END
  END o[605]
  PIN o[606]
    DIRECTION OUTPUT ;
    USE SIGNAL ;
    PORT
      LAYER M5 ;
        RECT  54.672 23.676 54.696 23.76 ;
    END
  END o[606]
  PIN o[607]
    DIRECTION OUTPUT ;
    USE SIGNAL ;
    PORT
      LAYER M5 ;
        RECT  54.768 23.676 54.792 23.76 ;
    END
  END o[607]
  PIN o[608]
    DIRECTION OUTPUT ;
    USE SIGNAL ;
    PORT
      LAYER M5 ;
        RECT  1.776 23.676 1.8 23.76 ;
    END
  END o[608]
  PIN o[609]
    DIRECTION OUTPUT ;
    USE SIGNAL ;
    PORT
      LAYER M5 ;
        RECT  1.872 23.676 1.896 23.76 ;
    END
  END o[609]
  PIN o[60]
    DIRECTION OUTPUT ;
    USE SIGNAL ;
    PORT
      LAYER M5 ;
        RECT  35.28 23.676 35.304 23.76 ;
    END
  END o[60]
  PIN o[610]
    DIRECTION OUTPUT ;
    USE SIGNAL ;
    PORT
      LAYER M5 ;
        RECT  1.968 23.676 1.992 23.76 ;
    END
  END o[610]
  PIN o[611]
    DIRECTION OUTPUT ;
    USE SIGNAL ;
    PORT
      LAYER M5 ;
        RECT  2.064 23.676 2.088 23.76 ;
    END
  END o[611]
  PIN o[612]
    DIRECTION OUTPUT ;
    USE SIGNAL ;
    PORT
      LAYER M5 ;
        RECT  2.16 23.676 2.184 23.76 ;
    END
  END o[612]
  PIN o[613]
    DIRECTION OUTPUT ;
    USE SIGNAL ;
    PORT
      LAYER M5 ;
        RECT  2.256 23.676 2.28 23.76 ;
    END
  END o[613]
  PIN o[614]
    DIRECTION OUTPUT ;
    USE SIGNAL ;
    PORT
      LAYER M5 ;
        RECT  2.352 23.676 2.376 23.76 ;
    END
  END o[614]
  PIN o[615]
    DIRECTION OUTPUT ;
    USE SIGNAL ;
    PORT
      LAYER M5 ;
        RECT  2.448 23.676 2.472 23.76 ;
    END
  END o[615]
  PIN o[616]
    DIRECTION OUTPUT ;
    USE SIGNAL ;
    PORT
      LAYER M5 ;
        RECT  2.544 23.676 2.568 23.76 ;
    END
  END o[616]
  PIN o[617]
    DIRECTION OUTPUT ;
    USE SIGNAL ;
    PORT
      LAYER M5 ;
        RECT  2.64 23.676 2.664 23.76 ;
    END
  END o[617]
  PIN o[618]
    DIRECTION OUTPUT ;
    USE SIGNAL ;
    PORT
      LAYER M5 ;
        RECT  2.736 23.676 2.76 23.76 ;
    END
  END o[618]
  PIN o[619]
    DIRECTION OUTPUT ;
    USE SIGNAL ;
    PORT
      LAYER M5 ;
        RECT  2.832 23.676 2.856 23.76 ;
    END
  END o[619]
  PIN o[61]
    DIRECTION OUTPUT ;
    USE SIGNAL ;
    PORT
      LAYER M5 ;
        RECT  35.376 23.676 35.4 23.76 ;
    END
  END o[61]
  PIN o[620]
    DIRECTION OUTPUT ;
    USE SIGNAL ;
    PORT
      LAYER M5 ;
        RECT  2.928 23.676 2.952 23.76 ;
    END
  END o[620]
  PIN o[621]
    DIRECTION OUTPUT ;
    USE SIGNAL ;
    PORT
      LAYER M5 ;
        RECT  3.024 23.676 3.048 23.76 ;
    END
  END o[621]
  PIN o[622]
    DIRECTION OUTPUT ;
    USE SIGNAL ;
    PORT
      LAYER M5 ;
        RECT  3.12 23.676 3.144 23.76 ;
    END
  END o[622]
  PIN o[623]
    DIRECTION OUTPUT ;
    USE SIGNAL ;
    PORT
      LAYER M5 ;
        RECT  3.216 23.676 3.24 23.76 ;
    END
  END o[623]
  PIN o[62]
    DIRECTION OUTPUT ;
    USE SIGNAL ;
    PORT
      LAYER M5 ;
        RECT  35.472 23.676 35.496 23.76 ;
    END
  END o[62]
  PIN o[63]
    DIRECTION OUTPUT ;
    USE SIGNAL ;
    PORT
      LAYER M5 ;
        RECT  35.568 23.676 35.592 23.76 ;
    END
  END o[63]
  PIN o[64]
    DIRECTION OUTPUT ;
    USE SIGNAL ;
    PORT
      LAYER M5 ;
        RECT  41.808 23.676 41.832 23.76 ;
    END
  END o[64]
  PIN o[65]
    DIRECTION OUTPUT ;
    USE SIGNAL ;
    PORT
      LAYER M5 ;
        RECT  41.904 23.676 41.928 23.76 ;
    END
  END o[65]
  PIN o[66]
    DIRECTION OUTPUT ;
    USE SIGNAL ;
    PORT
      LAYER M5 ;
        RECT  42 23.676 42.024 23.76 ;
    END
  END o[66]
  PIN o[67]
    DIRECTION OUTPUT ;
    USE SIGNAL ;
    PORT
      LAYER M5 ;
        RECT  42.096 23.676 42.12 23.76 ;
    END
  END o[67]
  PIN o[68]
    DIRECTION OUTPUT ;
    USE SIGNAL ;
    PORT
      LAYER M5 ;
        RECT  42.192 23.676 42.216 23.76 ;
    END
  END o[68]
  PIN o[69]
    DIRECTION OUTPUT ;
    USE SIGNAL ;
    PORT
      LAYER M5 ;
        RECT  42.288 23.676 42.312 23.76 ;
    END
  END o[69]
  PIN o[6]
    DIRECTION OUTPUT ;
    USE SIGNAL ;
    PORT
      LAYER M5 ;
        RECT  36.24 23.676 36.264 23.76 ;
    END
  END o[6]
  PIN o[70]
    DIRECTION OUTPUT ;
    USE SIGNAL ;
    PORT
      LAYER M5 ;
        RECT  42.384 23.676 42.408 23.76 ;
    END
  END o[70]
  PIN o[71]
    DIRECTION OUTPUT ;
    USE SIGNAL ;
    PORT
      LAYER M5 ;
        RECT  42.48 23.676 42.504 23.76 ;
    END
  END o[71]
  PIN o[72]
    DIRECTION OUTPUT ;
    USE SIGNAL ;
    PORT
      LAYER M5 ;
        RECT  42.576 23.676 42.6 23.76 ;
    END
  END o[72]
  PIN o[73]
    DIRECTION OUTPUT ;
    USE SIGNAL ;
    PORT
      LAYER M5 ;
        RECT  42.672 23.676 42.696 23.76 ;
    END
  END o[73]
  PIN o[74]
    DIRECTION OUTPUT ;
    USE SIGNAL ;
    PORT
      LAYER M5 ;
        RECT  42.768 23.676 42.792 23.76 ;
    END
  END o[74]
  PIN o[75]
    DIRECTION OUTPUT ;
    USE SIGNAL ;
    PORT
      LAYER M5 ;
        RECT  42.864 23.676 42.888 23.76 ;
    END
  END o[75]
  PIN o[76]
    DIRECTION OUTPUT ;
    USE SIGNAL ;
    PORT
      LAYER M5 ;
        RECT  42.96 23.676 42.984 23.76 ;
    END
  END o[76]
  PIN o[77]
    DIRECTION OUTPUT ;
    USE SIGNAL ;
    PORT
      LAYER M5 ;
        RECT  43.056 23.676 43.08 23.76 ;
    END
  END o[77]
  PIN o[78]
    DIRECTION OUTPUT ;
    USE SIGNAL ;
    PORT
      LAYER M5 ;
        RECT  43.152 23.676 43.176 23.76 ;
    END
  END o[78]
  PIN o[79]
    DIRECTION OUTPUT ;
    USE SIGNAL ;
    PORT
      LAYER M5 ;
        RECT  43.248 23.676 43.272 23.76 ;
    END
  END o[79]
  PIN o[7]
    DIRECTION OUTPUT ;
    USE SIGNAL ;
    PORT
      LAYER M5 ;
        RECT  36.336 23.676 36.36 23.76 ;
    END
  END o[7]
  PIN o[80]
    DIRECTION OUTPUT ;
    USE SIGNAL ;
    PORT
      LAYER M5 ;
        RECT  43.344 23.676 43.368 23.76 ;
    END
  END o[80]
  PIN o[81]
    DIRECTION OUTPUT ;
    USE SIGNAL ;
    PORT
      LAYER M5 ;
        RECT  43.44 23.676 43.464 23.76 ;
    END
  END o[81]
  PIN o[82]
    DIRECTION OUTPUT ;
    USE SIGNAL ;
    PORT
      LAYER M5 ;
        RECT  43.536 23.676 43.56 23.76 ;
    END
  END o[82]
  PIN o[83]
    DIRECTION OUTPUT ;
    USE SIGNAL ;
    PORT
      LAYER M5 ;
        RECT  43.632 23.676 43.656 23.76 ;
    END
  END o[83]
  PIN o[84]
    DIRECTION OUTPUT ;
    USE SIGNAL ;
    PORT
      LAYER M5 ;
        RECT  43.728 23.676 43.752 23.76 ;
    END
  END o[84]
  PIN o[85]
    DIRECTION OUTPUT ;
    USE SIGNAL ;
    PORT
      LAYER M5 ;
        RECT  43.824 23.676 43.848 23.76 ;
    END
  END o[85]
  PIN o[86]
    DIRECTION OUTPUT ;
    USE SIGNAL ;
    PORT
      LAYER M5 ;
        RECT  43.92 23.676 43.944 23.76 ;
    END
  END o[86]
  PIN o[87]
    DIRECTION OUTPUT ;
    USE SIGNAL ;
    PORT
      LAYER M5 ;
        RECT  44.016 23.676 44.04 23.76 ;
    END
  END o[87]
  PIN o[88]
    DIRECTION OUTPUT ;
    USE SIGNAL ;
    PORT
      LAYER M5 ;
        RECT  44.112 23.676 44.136 23.76 ;
    END
  END o[88]
  PIN o[89]
    DIRECTION OUTPUT ;
    USE SIGNAL ;
    PORT
      LAYER M5 ;
        RECT  44.208 23.676 44.232 23.76 ;
    END
  END o[89]
  PIN o[8]
    DIRECTION OUTPUT ;
    USE SIGNAL ;
    PORT
      LAYER M5 ;
        RECT  36.432 23.676 36.456 23.76 ;
    END
  END o[8]
  PIN o[90]
    DIRECTION OUTPUT ;
    USE SIGNAL ;
    PORT
      LAYER M5 ;
        RECT  44.304 23.676 44.328 23.76 ;
    END
  END o[90]
  PIN o[91]
    DIRECTION OUTPUT ;
    USE SIGNAL ;
    PORT
      LAYER M5 ;
        RECT  44.4 23.676 44.424 23.76 ;
    END
  END o[91]
  PIN o[92]
    DIRECTION OUTPUT ;
    USE SIGNAL ;
    PORT
      LAYER M5 ;
        RECT  44.496 23.676 44.52 23.76 ;
    END
  END o[92]
  PIN o[93]
    DIRECTION OUTPUT ;
    USE SIGNAL ;
    PORT
      LAYER M5 ;
        RECT  44.592 23.676 44.616 23.76 ;
    END
  END o[93]
  PIN o[94]
    DIRECTION OUTPUT ;
    USE SIGNAL ;
    PORT
      LAYER M5 ;
        RECT  44.688 23.676 44.712 23.76 ;
    END
  END o[94]
  PIN o[95]
    DIRECTION OUTPUT ;
    USE SIGNAL ;
    PORT
      LAYER M5 ;
        RECT  44.784 23.676 44.808 23.76 ;
    END
  END o[95]
  PIN o[96]
    DIRECTION OUTPUT ;
    USE SIGNAL ;
    PORT
      LAYER M5 ;
        RECT  38.736 23.676 38.76 23.76 ;
    END
  END o[96]
  PIN o[97]
    DIRECTION OUTPUT ;
    USE SIGNAL ;
    PORT
      LAYER M5 ;
        RECT  38.832 23.676 38.856 23.76 ;
    END
  END o[97]
  PIN o[98]
    DIRECTION OUTPUT ;
    USE SIGNAL ;
    PORT
      LAYER M5 ;
        RECT  38.928 23.676 38.952 23.76 ;
    END
  END o[98]
  PIN o[99]
    DIRECTION OUTPUT ;
    USE SIGNAL ;
    PORT
      LAYER M5 ;
        RECT  39.024 23.676 39.048 23.76 ;
    END
  END o[99]
  PIN o[9]
    DIRECTION OUTPUT ;
    USE SIGNAL ;
    PORT
      LAYER M5 ;
        RECT  36.528 23.676 36.552 23.76 ;
    END
  END o[9]
  PIN rs
    DIRECTION INPUT ;
    USE SIGNAL ;
    PORT
      LAYER M4 ;
        RECT  0 11.28 0.084 11.304 ;
    END
  END rs
  PIN rso
    DIRECTION OUTPUT ;
    USE SIGNAL ;
    PORT
      LAYER M5 ;
        RECT  3.312 23.676 3.336 23.76 ;
    END
  END rso
  PIN VDD
    DIRECTION INOUT ;
    USE POWER ;
    PORT
      LAYER M5 ;
        RECT  61.992 2.151 62.112 21.609 ;
        RECT  59.292 2.151 59.412 21.609 ;
        RECT  56.592 2.151 56.712 21.609 ;
        RECT  53.892 2.151 54.012 21.609 ;
        RECT  51.192 2.151 51.312 21.609 ;
        RECT  48.492 2.151 48.612 21.609 ;
        RECT  45.792 2.151 45.912 21.609 ;
        RECT  43.092 2.151 43.212 21.609 ;
        RECT  40.392 2.151 40.512 21.609 ;
        RECT  37.692 2.151 37.812 21.609 ;
        RECT  34.992 2.151 35.112 21.609 ;
        RECT  32.292 2.151 32.412 21.609 ;
        RECT  29.592 2.151 29.712 21.609 ;
        RECT  26.892 2.151 27.012 21.609 ;
        RECT  24.192 2.151 24.312 21.609 ;
        RECT  21.492 2.151 21.612 21.609 ;
        RECT  18.792 2.151 18.912 21.609 ;
        RECT  16.092 2.151 16.212 21.609 ;
        RECT  13.392 2.151 13.512 21.609 ;
        RECT  10.692 2.151 10.812 21.609 ;
        RECT  7.992 2.151 8.112 21.609 ;
        RECT  5.292 2.151 5.412 21.609 ;
        RECT  2.592 2.151 2.712 21.609 ;
    END
  END VDD
  PIN VSS
    DIRECTION INOUT ;
    USE GROUND ;
    PORT
      LAYER M5 ;
        RECT  61.8 2.137 61.92 21.623 ;
        RECT  59.1 2.137 59.22 21.623 ;
        RECT  56.4 2.137 56.52 21.623 ;
        RECT  53.7 2.137 53.82 21.623 ;
        RECT  51 2.137 51.12 21.623 ;
        RECT  48.3 2.137 48.42 21.623 ;
        RECT  45.6 2.137 45.72 21.623 ;
        RECT  42.9 2.137 43.02 21.623 ;
        RECT  40.2 2.137 40.32 21.623 ;
        RECT  37.5 2.137 37.62 21.623 ;
        RECT  34.8 2.137 34.92 21.623 ;
        RECT  32.1 2.137 32.22 21.623 ;
        RECT  29.4 2.137 29.52 21.623 ;
        RECT  26.7 2.137 26.82 21.623 ;
        RECT  24 2.137 24.12 21.623 ;
        RECT  21.3 2.137 21.42 21.623 ;
        RECT  18.6 2.137 18.72 21.623 ;
        RECT  15.9 2.137 16.02 21.623 ;
        RECT  13.2 2.137 13.32 21.623 ;
        RECT  10.5 2.137 10.62 21.623 ;
        RECT  7.8 2.137 7.92 21.623 ;
        RECT  5.1 2.137 5.22 21.623 ;
        RECT  2.4 2.137 2.52 21.623 ;
    END
  END VSS
  # OT_OBS_CLOSED layer=M5 d_um=1.536 added=55
  OBS
    LAYER RVTN ;
     RECT  2.16 2.16 62.64 2.295 ;
     RECT  2.16 2.565 62.64 2.835 ;
     RECT  2.16 3.105 62.64 3.375 ;
     RECT  2.16 3.645 62.64 3.915 ;
     RECT  2.16 4.185 62.64 4.455 ;
     RECT  2.16 4.725 62.64 4.995 ;
     RECT  2.16 5.265 62.64 5.535 ;
     RECT  2.16 5.805 62.64 6.075 ;
     RECT  2.16 6.345 62.64 6.615 ;
     RECT  2.16 6.885 62.64 7.155 ;
     RECT  2.16 7.425 62.64 7.695 ;
     RECT  2.16 7.965 62.64 8.235 ;
     RECT  2.16 8.505 62.64 8.775 ;
     RECT  2.16 9.045 62.64 9.315 ;
     RECT  2.16 9.585 62.64 9.855 ;
     RECT  2.16 10.125 62.64 10.395 ;
     RECT  2.16 10.665 62.64 10.935 ;
     RECT  2.16 11.205 62.64 11.475 ;
     RECT  2.16 11.745 62.64 12.015 ;
     RECT  2.16 12.285 62.64 12.555 ;
     RECT  2.16 12.825 62.64 13.095 ;
     RECT  2.16 13.365 62.64 13.635 ;
     RECT  2.16 13.905 62.64 14.175 ;
     RECT  2.16 14.445 62.64 14.715 ;
     RECT  2.16 14.985 62.64 15.255 ;
     RECT  2.16 15.525 62.64 15.795 ;
     RECT  2.16 16.065 62.64 16.335 ;
     RECT  2.16 16.605 62.64 16.875 ;
     RECT  2.16 17.145 62.64 17.415 ;
     RECT  2.16 17.685 62.64 17.955 ;
     RECT  2.16 18.225 62.64 18.495 ;
     RECT  2.16 18.765 62.64 19.035 ;
     RECT  2.16 19.305 62.64 19.575 ;
     RECT  2.16 19.845 62.64 20.115 ;
     RECT  2.16 20.385 62.64 20.655 ;
     RECT  2.16 20.925 62.64 21.195 ;
     RECT  2.16 21.465 62.64 21.6 ;
    LAYER RVTP ;
     RECT  2.16 2.295 62.64 2.565 ;
     RECT  2.16 2.835 62.64 3.105 ;
     RECT  2.16 3.375 62.64 3.645 ;
     RECT  2.16 3.915 62.64 4.185 ;
     RECT  2.16 4.455 62.64 4.725 ;
     RECT  2.16 4.995 62.64 5.265 ;
     RECT  2.16 5.535 62.64 5.805 ;
     RECT  2.16 6.075 62.64 6.345 ;
     RECT  2.16 6.615 62.64 6.885 ;
     RECT  2.16 7.155 62.64 7.425 ;
     RECT  2.16 7.695 62.64 7.965 ;
     RECT  2.16 8.235 62.64 8.505 ;
     RECT  2.16 8.775 62.64 9.045 ;
     RECT  2.16 9.315 62.64 9.585 ;
     RECT  2.16 9.855 62.64 10.125 ;
     RECT  2.16 10.395 62.64 10.665 ;
     RECT  2.16 10.935 62.64 11.205 ;
     RECT  2.16 11.475 62.64 11.745 ;
     RECT  2.16 12.015 62.64 12.285 ;
     RECT  2.16 12.555 62.64 12.825 ;
     RECT  2.16 13.095 62.64 13.365 ;
     RECT  2.16 13.635 62.64 13.905 ;
     RECT  2.16 14.175 62.64 14.445 ;
     RECT  2.16 14.715 62.64 14.985 ;
     RECT  2.16 15.255 62.64 15.525 ;
     RECT  2.16 15.795 62.64 16.065 ;
     RECT  2.16 16.335 62.64 16.605 ;
     RECT  2.16 16.875 62.64 17.145 ;
     RECT  2.16 17.415 62.64 17.685 ;
     RECT  2.16 17.955 62.64 18.225 ;
     RECT  2.16 18.495 62.64 18.765 ;
     RECT  2.16 19.035 62.64 19.305 ;
     RECT  2.16 19.575 62.64 19.845 ;
     RECT  2.16 20.115 62.64 20.385 ;
     RECT  2.16 20.655 62.64 20.925 ;
     RECT  2.16 21.195 62.64 21.465 ;
    LAYER M1 ;
     RECT  2.16 2.151 62.64 21.609 ;
    LAYER M2 ;
     RECT  0.823 3.582 0.931 3.6 ;
     RECT  0.931 3.582 1.723 3.978 ;
     RECT  1.723 3.582 1.759 4.41 ;
     RECT  1.795 20.898 1.975 20.916 ;
     RECT  1.975 20.898 2.047 21.294 ;
     RECT  1.759 3.582 2.083 4.482 ;
     RECT  2.083 2.736 2.119 2.754 ;
     RECT  2.047 13.176 2.119 13.194 ;
     RECT  2.119 2.646 2.155 2.754 ;
     RECT  2.047 20.898 2.155 21.384 ;
     RECT  2.155 2.268 2.16 2.754 ;
     RECT  2.083 3.582 2.16 5.094 ;
     RECT  2.119 10.062 2.16 10.08 ;
     RECT  2.119 12.996 2.16 13.194 ;
     RECT  1.975 16.686 2.16 16.704 ;
     RECT  2.155 20.556 2.16 21.384 ;
     RECT  2.16 2.151 2.659 21.609 ;
     RECT  3.127 22.788 3.407 22.806 ;
     RECT  2.659 2.07 4.387 21.609 ;
     RECT  4.387 1.836 5.899 21.609 ;
     RECT  5.899 1.836 7.655 21.654 ;
     RECT  7.411 22.788 7.763 22.806 ;
     RECT  7.655 1.836 11.479 21.609 ;
     RECT  11.479 1.836 11.867 21.654 ;
     RECT  11.867 1.836 13.171 21.609 ;
     RECT  13.171 1.8 15.611 21.609 ;
     RECT  15.611 1.836 16.159 21.609 ;
     RECT  16.159 1.836 17.591 21.654 ;
     RECT  17.591 1.836 18.527 21.609 ;
     RECT  18.527 1.962 19.831 21.609 ;
     RECT  19.831 1.962 20.687 21.654 ;
     RECT  20.687 2.151 20.975 21.654 ;
     RECT  20.975 2.151 21.847 21.609 ;
     RECT  21.847 2.151 23.287 21.654 ;
     RECT  23.287 2.106 23.351 21.654 ;
     RECT  23.351 2.106 24.187 21.609 ;
     RECT  24.187 1.998 25.123 21.609 ;
     RECT  25.123 1.998 26.231 21.654 ;
     RECT  26.231 1.998 27.067 21.609 ;
     RECT  27.067 1.926 29.011 21.609 ;
     RECT  29.011 1.764 29.371 21.609 ;
     RECT  29.371 1.728 29.659 21.609 ;
     RECT  29.659 1.728 31.307 21.654 ;
     RECT  31.307 1.728 34.367 21.609 ;
     RECT  34.367 1.8 35.455 21.609 ;
     RECT  35.419 22.788 36.383 22.806 ;
     RECT  38.335 22.788 38.507 22.806 ;
     RECT  39.379 22.788 39.551 22.806 ;
     RECT  35.455 1.764 41.467 21.609 ;
     RECT  41.467 1.764 41.927 21.654 ;
     RECT  41.927 1.926 41.999 21.654 ;
     RECT  41.999 1.962 42.395 21.654 ;
     RECT  42.395 2.151 44.735 21.654 ;
     RECT  44.735 2.151 46.039 21.609 ;
     RECT  46.039 2.106 46.975 21.609 ;
     RECT  46.975 2.034 48.235 21.609 ;
     RECT  48.235 1.881 48.731 21.654 ;
     RECT  48.731 1.881 50.287 21.609 ;
     RECT  50.287 1.881 51.979 21.654 ;
     RECT  51.979 1.836 52.403 21.654 ;
     RECT  52.403 1.836 56.551 21.609 ;
     RECT  56.551 1.836 57.839 21.654 ;
     RECT  57.839 1.836 59.459 21.609 ;
     RECT  59.459 1.881 59.719 21.609 ;
     RECT  59.719 1.881 61.511 21.654 ;
     RECT  61.511 2.151 62.64 21.654 ;
     RECT  62.64 3.924 62.663 3.942 ;
     RECT  62.64 8.244 62.663 8.262 ;
     RECT  62.64 5.544 62.735 5.868 ;
     RECT  62.64 9.936 62.735 13.662 ;
     RECT  62.64 14.922 62.771 17.874 ;
     RECT  62.735 5.85 62.843 5.868 ;
     RECT  62.771 15.066 62.843 17.874 ;
     RECT  62.64 18.666 62.843 21.654 ;
     RECT  62.735 10.296 63.095 13.662 ;
     RECT  62.843 19.278 63.095 21.654 ;
     RECT  62.843 15.066 63.131 17.784 ;
     RECT  63.131 16.506 63.239 17.784 ;
     RECT  63.095 19.278 63.275 19.836 ;
     RECT  63.275 19.278 63.311 19.296 ;
     RECT  63.095 20.592 63.419 21.654 ;
     RECT  63.095 10.296 63.491 13.464 ;
     RECT  63.239 17.388 63.563 17.784 ;
     RECT  63.419 20.592 63.599 21.492 ;
     RECT  63.491 10.296 63.635 13.014 ;
     RECT  63.599 20.628 63.635 21.492 ;
     RECT  63.635 12.258 63.671 13.014 ;
     RECT  63.635 21.168 63.671 21.492 ;
     RECT  63.131 15.066 63.707 15.714 ;
     RECT  63.239 16.506 63.743 16.524 ;
     RECT  63.635 10.296 63.887 11.394 ;
     RECT  63.671 21.168 63.887 21.456 ;
     RECT  63.563 17.766 63.923 17.784 ;
     RECT  63.887 10.791 63.959 11.394 ;
     RECT  63.959 11.376 63.995 11.394 ;
     RECT  63.887 21.438 63.995 21.456 ;
     RECT  63.707 15.696 64.031 15.714 ;
     RECT  63.671 12.996 64.067 13.014 ;
    LAYER M3 ;
     RECT  8.28 0.091 8.298 0.139 ;
     RECT  40.716 0.091 40.734 0.139 ;
     RECT  56.844 0.091 56.862 0.139 ;
     RECT  8.28 0.139 8.442 0.187 ;
     RECT  10.98 0.091 11.394 0.187 ;
     RECT  37.98 0.091 37.998 0.187 ;
     RECT  40.716 0.139 40.878 0.187 ;
     RECT  40.716 0.187 40.95 0.269 ;
     RECT  56.844 0.139 56.97 0.269 ;
     RECT  37.98 0.187 38.61 0.317 ;
     RECT  40.86 0.269 40.95 0.317 ;
     RECT  56.952 0.269 56.97 0.317 ;
     RECT  8.208 0.187 8.514 0.365 ;
     RECT  10.908 0.187 11.394 0.365 ;
     RECT  40.932 0.317 40.95 0.365 ;
     RECT  11.376 0.365 11.394 0.413 ;
     RECT  8.208 0.365 8.226 0.461 ;
     RECT  57.6 0.523 57.618 0.571 ;
     RECT  58.536 0.139 58.554 0.571 ;
     RECT  12.24 1.051 12.258 1.099 ;
     RECT  62.568 0.091 62.586 1.099 ;
     RECT  62.28 1.099 62.586 1.147 ;
     RECT  61.596 1.147 62.586 1.675 ;
     RECT  3.492 0.571 3.51 1.723 ;
     RECT  12.24 1.099 12.474 1.723 ;
     RECT  13.68 1.099 13.698 1.723 ;
     RECT  26.136 1.243 26.154 1.723 ;
     RECT  38.592 0.317 38.61 1.723 ;
     RECT  46.116 0.091 46.134 1.723 ;
     RECT  48.996 1.147 49.014 1.723 ;
     RECT  51.48 0.523 51.498 1.723 ;
     RECT  57.6 0.571 58.554 1.723 ;
     RECT  3.384 1.723 10.206 1.771 ;
     RECT  11.304 1.723 14.49 1.771 ;
     RECT  15.372 1.723 15.39 1.771 ;
     RECT  16.236 1.723 18.198 1.771 ;
     RECT  19.152 1.723 26.154 1.771 ;
     RECT  27.252 1.723 34.362 1.771 ;
     RECT  56.772 1.723 60.03 1.771 ;
     RECT  61.56 1.675 62.586 1.771 ;
     RECT  45.396 1.723 49.122 1.819 ;
     RECT  56.772 1.771 62.586 1.819 ;
     RECT  27.18 1.771 34.362 1.831 ;
     RECT  35.28 1.723 40.554 1.831 ;
     RECT  50.652 1.723 53.55 1.867 ;
     RECT  54.36 1.723 55.674 1.867 ;
     RECT  11.304 1.771 26.154 1.876 ;
     RECT  50.652 1.867 55.674 1.876 ;
     RECT  27.18 1.831 40.554 1.921 ;
     RECT  3.168 1.771 10.206 1.957 ;
     RECT  11.088 1.876 26.154 1.957 ;
     RECT  3.168 1.957 26.154 2.011 ;
     RECT  27.072 1.921 40.554 2.011 ;
     RECT  41.4 1.723 44.55 2.011 ;
     RECT  2.736 2.011 26.154 2.029 ;
     RECT  2.736 2.029 26.226 2.065 ;
     RECT  27.072 2.011 44.55 2.065 ;
     RECT  45.36 1.819 49.122 2.065 ;
     RECT  50.652 1.876 55.854 2.065 ;
     RECT  45.36 2.065 49.374 2.101 ;
     RECT  2.664 2.065 44.55 2.143 ;
     RECT  50.508 2.065 55.854 2.143 ;
     RECT  56.736 1.819 62.586 2.143 ;
     RECT  2.415 2.143 44.55 2.191 ;
     RECT  45.36 2.101 49.662 2.191 ;
     RECT  50.508 2.143 62.586 2.191 ;
     RECT  2.268 2.191 62.586 2.263 ;
     RECT  2.16 2.263 62.586 2.641 ;
     RECT  2.124 2.641 62.586 2.731 ;
     RECT  2.088 2.731 62.586 2.875 ;
     RECT  0.828 2.923 0.846 2.971 ;
     RECT  0.828 2.971 0.954 3.403 ;
     RECT  1.728 2.875 62.586 3.403 ;
     RECT  0.828 3.403 62.586 3.605 ;
     RECT  0.936 3.605 62.586 3.919 ;
     RECT  0.936 3.919 62.658 3.947 ;
     RECT  1.728 3.947 62.658 3.979 ;
     RECT  0.936 3.947 0.954 3.983 ;
     RECT  1.728 3.979 62.73 4.415 ;
     RECT  1.764 4.415 62.73 4.487 ;
     RECT  2.088 4.487 62.73 4.555 ;
     RECT  2.088 4.555 62.838 5.099 ;
     RECT  2.124 5.099 62.838 5.873 ;
     RECT  2.124 5.873 62.658 8.267 ;
     RECT  2.124 8.267 62.406 9.931 ;
     RECT  2.124 9.931 62.73 10.085 ;
     RECT  2.232 10.085 62.73 10.625 ;
     RECT  2.268 10.625 62.73 10.699 ;
     RECT  2.268 10.699 62.766 10.741 ;
     RECT  63.864 10.291 63.882 10.786 ;
     RECT  2.268 10.741 62.802 11.011 ;
     RECT  2.268 11.011 62.91 11.173 ;
     RECT  2.268 11.173 62.946 11.326 ;
     RECT  63.864 10.786 63.954 11.326 ;
     RECT  2.268 11.326 63.954 11.371 ;
     RECT  2.268 11.371 63.99 11.705 ;
     RECT  2.304 11.705 63.99 11.975 ;
     RECT  2.34 11.975 63.99 12.991 ;
     RECT  2.124 12.991 64.062 13.171 ;
     RECT  2.052 13.171 64.062 16.681 ;
     RECT  1.98 16.681 64.062 20.893 ;
     RECT  1.8 20.893 64.062 21.437 ;
     RECT  1.8 21.437 63.99 21.461 ;
     RECT  47.844 21.461 63.954 21.485 ;
     RECT  1.8 21.461 46.674 21.533 ;
     RECT  1.8 21.533 25.146 21.569 ;
     RECT  25.956 21.533 40.698 21.569 ;
     RECT  47.844 21.485 63.918 21.569 ;
     RECT  26.136 21.569 40.305 21.581 ;
     RECT  1.8 21.569 8.478 21.617 ;
     RECT  13.215 21.569 25.146 21.617 ;
     RECT  32.115 21.581 40.305 21.617 ;
     RECT  41.436 21.533 46.674 21.617 ;
     RECT  57.6 21.569 60.966 21.617 ;
     RECT  61.815 21.569 63.918 21.617 ;
     RECT  3.168 21.617 8.478 21.629 ;
     RECT  16.092 21.617 25.146 21.629 ;
     RECT  26.136 21.581 29.97 21.629 ;
     RECT  20.844 21.629 25.146 21.659 ;
     RECT  31.176 21.581 31.302 21.659 ;
     RECT  41.436 21.617 42.282 21.659 ;
     RECT  55.692 21.569 56.574 21.659 ;
     RECT  1.8 21.617 2.286 21.677 ;
     RECT  3.168 21.629 8.406 21.677 ;
     RECT  9.54 21.569 12.438 21.677 ;
     RECT  13.68 21.617 15.246 21.677 ;
     RECT  16.092 21.629 20.07 21.677 ;
     RECT  20.844 21.659 24.822 21.677 ;
     RECT  32.292 21.617 34.398 21.677 ;
     RECT  41.436 21.659 42.246 21.677 ;
     RECT  43.092 21.617 46.674 21.677 ;
     RECT  49.68 21.569 54.918 21.677 ;
     RECT  57.6 21.617 58.554 21.677 ;
     RECT  59.292 21.617 60.966 21.677 ;
     RECT  5.544 21.677 8.226 21.725 ;
     RECT  16.092 21.677 18.99 21.725 ;
     RECT  20.844 21.677 23.958 21.725 ;
     RECT  26.136 21.629 27.378 21.725 ;
     RECT  32.292 21.677 32.994 21.725 ;
     RECT  37.836 21.617 40.122 21.725 ;
     RECT  50.256 21.677 54.918 21.725 ;
     RECT  2.268 21.677 2.286 21.773 ;
     RECT  9.54 21.677 11.898 21.773 ;
     RECT  16.092 21.725 16.434 21.773 ;
     RECT  21.708 21.725 23.958 21.773 ;
     RECT  26.208 21.725 27.378 21.773 ;
     RECT  32.292 21.725 32.922 21.773 ;
     RECT  35.28 21.617 36.882 21.773 ;
     RECT  47.988 21.569 48.87 21.773 ;
     RECT  50.256 21.725 53.586 21.773 ;
     RECT  55.692 21.659 56.214 21.773 ;
     RECT  59.292 21.677 59.958 21.773 ;
     RECT  9.54 21.773 10.89 21.821 ;
     RECT  22.212 21.773 23.634 21.821 ;
     RECT  28.476 21.629 29.97 21.821 ;
     RECT  33.84 21.677 34.398 21.821 ;
     RECT  43.092 21.677 43.146 21.821 ;
     RECT  47.988 21.773 48.798 21.821 ;
     RECT  62.532 21.617 63.918 21.869 ;
     RECT  32.904 21.773 32.922 21.917 ;
     RECT  43.128 21.821 43.146 21.917 ;
     RECT  51.804 21.773 53.586 22.013 ;
     RECT  17.496 21.725 18.306 22.157 ;
     RECT  13.68 21.677 14.85 22.205 ;
     RECT  17.496 22.157 17.514 22.205 ;
     RECT  22.68 21.821 23.634 22.205 ;
     RECT  26.208 21.773 26.478 22.205 ;
     RECT  38.484 21.725 40.122 22.205 ;
     RECT  41.688 21.677 42.246 22.205 ;
     RECT  44.172 21.677 46.17 22.205 ;
     RECT  55.692 21.773 55.71 22.205 ;
     RECT  5.544 21.725 7.758 22.253 ;
     RECT  9.54 21.821 10.278 22.253 ;
     RECT  16.38 21.773 16.434 22.253 ;
     RECT  28.476 21.821 29.142 22.253 ;
     RECT  44.172 22.205 45.126 22.253 ;
     RECT  47.988 21.821 48.222 22.253 ;
     RECT  50.256 21.773 50.886 22.253 ;
     RECT  52.416 22.013 53.586 22.253 ;
     RECT  58.176 21.677 58.518 22.253 ;
     RECT  44.172 22.253 44.37 22.301 ;
     RECT  52.416 22.253 52.434 22.301 ;
     RECT  58.176 22.253 58.482 22.301 ;
     RECT  16.38 22.253 16.398 22.733 ;
     RECT  45.108 22.253 45.126 22.733 ;
     RECT  3.168 21.677 3.942 22.781 ;
     RECT  9.54 22.253 9.558 22.781 ;
     RECT  11.88 21.773 11.898 22.781 ;
     RECT  14.436 22.205 14.85 22.781 ;
     RECT  20.844 21.725 20.862 22.781 ;
     RECT  22.68 22.205 23.31 22.781 ;
     RECT  31.176 21.659 31.194 22.781 ;
     RECT  35.352 21.773 36.882 22.781 ;
     RECT  44.352 22.301 44.37 22.781 ;
     RECT  48.204 22.253 48.222 22.781 ;
     RECT  53.244 22.253 53.586 22.781 ;
     RECT  58.464 22.301 58.482 22.781 ;
     RECT  3.168 22.781 3.474 22.783 ;
     RECT  38.484 22.205 38.502 22.783 ;
     RECT  7.056 22.253 7.758 22.811 ;
     RECT  35.424 22.781 36.378 22.811 ;
     RECT  38.34 22.783 38.502 22.811 ;
     RECT  39.384 22.205 40.122 22.811 ;
     RECT  7.056 22.811 7.686 22.829 ;
     RECT  26.46 22.205 26.478 22.829 ;
     RECT  38.34 22.811 38.358 22.829 ;
     RECT  39.528 22.811 40.122 22.829 ;
     RECT  41.688 22.205 41.706 22.829 ;
     RECT  59.472 21.773 59.958 22.829 ;
     RECT  24.804 21.677 24.822 23.275 ;
     RECT  27.36 21.773 27.378 23.275 ;
     RECT  28.476 22.253 28.494 23.275 ;
     RECT  29.952 21.821 29.97 23.275 ;
     RECT  40.104 22.829 40.122 23.275 ;
     RECT  19.728 21.677 19.926 23.323 ;
     RECT  38.088 23.275 38.178 23.323 ;
     RECT  46.152 22.205 46.17 23.323 ;
     RECT  62.64 21.869 63.918 23.323 ;
     RECT  28.476 23.275 28.53 23.371 ;
     RECT  43.668 23.275 43.686 23.371 ;
     RECT  60.912 21.677 60.966 23.371 ;
     RECT  18.288 22.157 18.306 23.405 ;
     RECT  13.68 22.205 13.698 23.419 ;
     RECT  14.436 22.781 14.706 23.419 ;
     RECT  16.776 23.323 16.794 23.419 ;
     RECT  24.732 23.275 24.966 23.419 ;
     RECT  28.404 23.371 28.53 23.419 ;
     RECT  33.84 21.821 34.146 23.419 ;
     RECT  40.104 23.275 40.77 23.419 ;
     RECT  46.152 23.323 46.458 23.419 ;
     RECT  60.912 23.371 61.29 23.419 ;
     RECT  33.372 23.419 34.146 23.467 ;
     RECT  59.58 22.829 59.958 23.467 ;
     RECT  60.732 23.419 61.29 23.467 ;
     RECT  5.544 22.253 6.138 23.501 ;
     RECT  27.144 23.275 27.378 23.501 ;
     RECT  28.188 23.419 28.53 23.501 ;
     RECT  37.98 23.323 38.178 23.501 ;
     RECT  62.604 23.323 63.918 23.501 ;
     RECT  29.952 23.275 30.006 23.515 ;
     RECT  43.452 23.371 43.686 23.515 ;
     RECT  54.432 21.725 54.918 23.515 ;
     RECT  56.88 23.419 56.898 23.515 ;
     RECT  59.58 23.467 61.29 23.515 ;
     RECT  13.68 23.419 14.706 23.549 ;
     RECT  24.624 23.419 24.966 23.549 ;
     RECT  28.188 23.501 28.494 23.549 ;
     RECT  53.244 22.781 53.37 23.549 ;
     RECT  5.76 23.501 6.138 23.597 ;
     RECT  10.152 23.371 10.242 23.597 ;
     RECT  16.776 23.419 17.046 23.597 ;
     RECT  24.804 23.549 24.966 23.597 ;
     RECT  28.476 23.549 28.494 23.597 ;
     RECT  35.424 22.811 35.442 23.597 ;
     RECT  43.452 23.515 43.758 23.597 ;
     RECT  46.152 23.419 46.71 23.597 ;
     RECT  62.64 23.501 63.918 23.597 ;
     RECT  3.132 22.783 3.474 23.645 ;
     RECT  5.76 23.597 5.778 23.645 ;
     RECT  7.488 22.829 7.686 23.645 ;
     RECT  10.224 23.597 10.242 23.645 ;
     RECT  13.68 23.549 14.598 23.645 ;
     RECT  16.92 23.597 16.938 23.645 ;
     RECT  19.26 23.323 19.926 23.645 ;
     RECT  22.68 22.781 22.698 23.645 ;
     RECT  24.804 23.597 24.822 23.645 ;
     RECT  27.36 23.501 27.378 23.645 ;
     RECT  29.664 23.515 30.006 23.645 ;
     RECT  31.788 23.419 31.806 23.645 ;
     RECT  33.228 23.467 34.146 23.645 ;
     RECT  36.36 22.811 36.378 23.645 ;
     RECT  37.98 23.501 37.998 23.645 ;
     RECT  40.104 23.419 40.986 23.645 ;
     RECT  43.524 23.597 43.758 23.645 ;
     RECT  46.152 23.597 46.602 23.645 ;
     RECT  50.688 22.253 50.706 23.645 ;
     RECT  53.244 23.549 53.262 23.645 ;
     RECT  54.18 23.515 54.918 23.645 ;
     RECT  56.88 23.515 57.114 23.645 ;
     RECT  59.58 23.515 61.398 23.645 ;
     RECT  63.036 23.597 63.918 23.645 ;
     RECT  48.816 23.611 48.834 23.741 ;
    LAYER M4 ;
     RECT  0.084 11.184 0.179 11.208 ;
     RECT  0.06 11.208 0.179 11.28 ;
     RECT  0.084 11.28 0.179 11.304 ;
     RECT  0.709 2.88 0.773 2.904 ;
     RECT  0.773 2.88 0.856 2.952 ;
     RECT  0.997 3.984 1.189 4.008 ;
     RECT  1.189 3.984 1.285 4.056 ;
     RECT  1.285 3.984 1.381 4.104 ;
     RECT  0.856 2.88 1.457 3 ;
     RECT  1.381 3.984 1.457 4.776 ;
     RECT  1.861 20.304 1.957 20.328 ;
     RECT  1.957 20.064 2.053 20.328 ;
     RECT  2.149 18.96 2.197 18.984 ;
     RECT  2.053 20.064 2.197 20.376 ;
     RECT  1.745 21.648 2.257 21.672 ;
     RECT  2.197 18.96 2.293 20.472 ;
     RECT  0.133 12.576 2.329 12.6 ;
     RECT  2.293 0.24 2.341 0.264 ;
     RECT  2.293 23.424 2.341 23.448 ;
     RECT  2.149 15.84 2.365 15.864 ;
     RECT  1.457 2.88 2.408 4.776 ;
     RECT  0.179 11.28 2.408 11.304 ;
     RECT  2.329 12.48 2.408 12.6 ;
     RECT  2.365 14.928 2.408 15.864 ;
     RECT  2.293 18.768 2.408 20.472 ;
     RECT  2.257 21.648 2.408 21.768 ;
     RECT  2.341 23.328 2.437 23.448 ;
     RECT  2.341 0.24 2.533 0.408 ;
     RECT  2.533 0.24 2.677 0.6 ;
     RECT  2.408 2.148 2.677 21.768 ;
     RECT  2.677 1.92 2.704 21.768 ;
     RECT  2.437 23.328 2.821 23.496 ;
     RECT  2.677 0.144 2.867 0.6 ;
     RECT  2.704 11.232 2.867 21.768 ;
     RECT  2.821 23.328 2.867 23.64 ;
     RECT  2.867 11.424 2.869 21.768 ;
     RECT  2.704 1.92 2.917 4.968 ;
     RECT  2.869 11.424 2.945 21.912 ;
     RECT  2.945 12.672 3.059 21.912 ;
     RECT  2.945 11.424 3.089 11.688 ;
     RECT  3.059 12.672 3.377 21.24 ;
     RECT  2.867 23.52 3.485 23.64 ;
     RECT  2.867 0.576 3.521 0.6 ;
     RECT  2.704 6.624 3.697 6.648 ;
     RECT  3.697 6 3.805 6.648 ;
     RECT  3.377 18.672 3.917 21.24 ;
     RECT  3.089 11.568 3.925 11.688 ;
     RECT  3.377 12.672 3.925 17.688 ;
     RECT  3.869 22.752 3.953 22.776 ;
     RECT  3.925 11.568 4.057 17.688 ;
     RECT  3.917 19.248 4.261 21.24 ;
     RECT  3.805 6 4.381 7.128 ;
     RECT  2.704 8.208 4.381 8.232 ;
     RECT  4.381 6 4.405 8.232 ;
     RECT  2.917 1.728 4.501 4.968 ;
     RECT  4.405 6 4.501 8.808 ;
     RECT  4.057 11.472 4.597 17.688 ;
     RECT  4.597 11.472 4.981 18.216 ;
     RECT  4.261 19.248 4.981 21.672 ;
     RECT  4.501 1.728 5.108 8.808 ;
     RECT  4.981 11.472 5.108 21.672 ;
     RECT  4.789 23.568 5.125 23.592 ;
     RECT  5.125 23.28 5.221 23.592 ;
     RECT  5.221 23.28 5.317 23.64 ;
     RECT  5.108 1.728 5.404 21.672 ;
     RECT  5.221 0.336 5.413 0.36 ;
     RECT  5.413 0.336 5.509 0.456 ;
     RECT  5.509 0.144 5.555 0.456 ;
     RECT  5.555 0.144 5.603 0.36 ;
     RECT  5.317 23.088 5.651 23.64 ;
     RECT  5.603 0.144 5.699 0.168 ;
     RECT  5.651 23.376 5.699 23.64 ;
     RECT  5.699 23.568 5.789 23.64 ;
     RECT  5.404 12 5.825 16.92 ;
     RECT  5.789 23.568 6.149 23.592 ;
     RECT  5.404 18.912 6.373 21.672 ;
     RECT  5.825 12.192 6.397 16.92 ;
     RECT  6.373 18.912 6.725 22.248 ;
     RECT  6.397 12.192 6.793 17.064 ;
     RECT  6.725 18.96 6.797 22.248 ;
     RECT  6.797 19.344 6.833 22.248 ;
     RECT  6.833 19.392 7.045 22.248 ;
     RECT  6.793 12.096 7.189 17.064 ;
     RECT  7.045 19.392 7.309 22.824 ;
     RECT  7.309 22.8 7.429 22.824 ;
     RECT  7.573 0.144 7.669 0.168 ;
     RECT  7.189 11.712 7.669 17.064 ;
     RECT  7.429 22.8 7.697 23.64 ;
     RECT  5.404 1.728 7.808 8.808 ;
     RECT  6.757 10.032 7.808 10.056 ;
     RECT  7.669 11.712 7.808 17.4 ;
     RECT  7.309 19.392 7.808 21.72 ;
     RECT  7.697 22.8 7.859 23.544 ;
     RECT  7.669 0.144 8.005 0.264 ;
     RECT  7.808 1.728 8.104 21.72 ;
     RECT  8.005 0.144 8.197 0.312 ;
     RECT  8.104 18.816 8.237 21.72 ;
     RECT  8.197 0.144 8.242 0.456 ;
     RECT  7.859 23.424 8.243 23.544 ;
     RECT  8.242 0.096 8.339 0.456 ;
     RECT  8.339 0.096 8.353 0.36 ;
     RECT  8.243 23.52 8.387 23.544 ;
     RECT  8.237 18.816 8.417 21.672 ;
     RECT  8.353 0.144 8.486 0.36 ;
     RECT  8.417 18.816 8.489 21.624 ;
     RECT  8.486 0.192 8.525 0.36 ;
     RECT  8.525 0.192 8.531 0.312 ;
     RECT  8.531 0.192 8.569 0.216 ;
     RECT  8.104 1.728 9.097 17.016 ;
     RECT  9.097 1.728 9.205 17.112 ;
     RECT  8.489 18.816 9.253 21.24 ;
     RECT  9.253 18.72 9.445 21.24 ;
     RECT  9.349 22.752 9.569 22.776 ;
     RECT  9.205 1.728 9.733 17.64 ;
     RECT  9.445 18.672 9.733 21.24 ;
     RECT  9.733 1.728 10.213 21.24 ;
     RECT  9.745 22.224 10.213 22.248 ;
     RECT  10.097 23.328 10.213 23.592 ;
     RECT  10.213 23.328 10.297 23.64 ;
     RECT  10.261 0.144 10.357 0.168 ;
     RECT  10.297 23.328 10.451 23.352 ;
     RECT  10.357 0.144 10.501 0.264 ;
     RECT  10.213 1.728 10.789 22.248 ;
     RECT  10.789 1.728 10.804 22.776 ;
     RECT  10.501 0.144 10.897 0.312 ;
     RECT  10.804 18.72 10.901 22.776 ;
     RECT  10.897 0.144 10.93 0.36 ;
     RECT  10.901 18.72 11.117 21.768 ;
     RECT  10.93 0.096 11.221 0.36 ;
     RECT  11.117 18.768 11.261 21.768 ;
     RECT  11.261 19.344 11.441 21.672 ;
     RECT  11.221 0.096 11.449 0.408 ;
     RECT  10.804 1.728 12.229 17.688 ;
     RECT  11.441 19.92 12.449 21.672 ;
     RECT  12.449 19.92 12.517 21.612 ;
     RECT  12.229 1.056 12.709 17.688 ;
     RECT  12.517 19.872 12.853 21.612 ;
     RECT  10.901 22.752 12.853 22.776 ;
     RECT  12.709 1.056 13.093 18.216 ;
     RECT  12.853 19.344 13.093 21.612 ;
     RECT  12.853 22.752 13.285 23.592 ;
     RECT  13.093 1.056 13.331 21.612 ;
     RECT  13.331 1.104 13.477 21.612 ;
     RECT  13.477 1.104 13.504 21.72 ;
     RECT  13.504 10.608 13.669 21.72 ;
     RECT  13.285 22.752 13.669 23.64 ;
     RECT  13.504 1.104 13.715 9.528 ;
     RECT  13.669 10.608 13.817 23.64 ;
     RECT  13.817 10.608 14.069 21.672 ;
     RECT  14.069 10.656 14.291 21.672 ;
     RECT  13.817 22.704 14.609 23.64 ;
     RECT  14.291 18.528 15.301 21.672 ;
     RECT  14.291 10.656 15.349 17.064 ;
     RECT  15.301 18.24 15.349 21.672 ;
     RECT  15.349 10.656 15.877 21.672 ;
     RECT  14.609 22.704 15.877 23.592 ;
     RECT  13.715 1.728 15.908 9.528 ;
     RECT  15.877 10.656 15.908 23.592 ;
     RECT  15.733 0.144 16.069 0.168 ;
     RECT  15.908 1.728 16.204 23.592 ;
     RECT  16.069 0.144 16.261 0.36 ;
     RECT  16.204 10.656 16.355 23.592 ;
     RECT  16.261 0.144 16.403 0.456 ;
     RECT  16.355 10.656 16.403 11.688 ;
     RECT  16.355 12.672 16.409 23.592 ;
     RECT  16.409 12.672 16.499 22.248 ;
     RECT  16.403 0.144 16.547 0.168 ;
     RECT  16.403 10.704 16.643 11.688 ;
     RECT  16.643 10.704 16.739 10.728 ;
     RECT  16.409 23.328 16.882 23.592 ;
     RECT  16.882 23.328 16.883 23.64 ;
     RECT  16.204 1.728 16.913 9.24 ;
     RECT  16.883 23.376 16.993 23.64 ;
     RECT  16.499 12.672 17.449 22.2 ;
     RECT  17.449 12.48 18.205 22.2 ;
     RECT  18.205 12.048 18.373 22.2 ;
     RECT  16.993 23.376 18.373 23.592 ;
     RECT  16.913 1.728 18.608 8.808 ;
     RECT  18.373 12.048 18.608 23.592 ;
     RECT  18.608 1.728 18.707 23.592 ;
     RECT  18.707 1.728 18.904 21.72 ;
     RECT  18.904 12 19.001 21.72 ;
     RECT  18.853 0.144 19.043 0.168 ;
     RECT  18.707 22.704 19.234 23.592 ;
     RECT  19.001 12 19.577 21.672 ;
     RECT  19.234 22.704 19.937 23.64 ;
     RECT  19.577 12 20.629 17.64 ;
     RECT  19.577 18.624 20.629 21.672 ;
     RECT  19.937 22.704 20.873 22.776 ;
     RECT  20.629 12 20.876 21.672 ;
     RECT  20.876 11.952 20.965 21.672 ;
     RECT  18.904 1.728 21.308 8.808 ;
     RECT  20.965 11.952 21.308 22.248 ;
     RECT  21.109 0.144 21.587 0.168 ;
     RECT  21.308 1.728 21.604 22.248 ;
     RECT  21.604 12 22.021 22.248 ;
     RECT  21.637 23.568 22.021 23.592 ;
     RECT  22.021 12 22.241 23.592 ;
     RECT  22.241 22.752 22.597 23.592 ;
     RECT  22.597 22.752 22.709 23.64 ;
     RECT  22.241 12 23.461 21.672 ;
     RECT  22.709 22.752 23.461 22.776 ;
     RECT  21.604 1.728 24.008 8.808 ;
     RECT  23.461 12 24.008 22.776 ;
     RECT  24.008 1.728 24.037 22.776 ;
     RECT  24.037 1.728 24.277 23.592 ;
     RECT  24.277 0.24 24.304 23.592 ;
     RECT  24.304 0.24 24.419 8.808 ;
     RECT  24.419 0.24 24.467 0.36 ;
     RECT  24.304 18.768 24.563 23.592 ;
     RECT  24.419 1.728 24.581 8.808 ;
     RECT  24.563 22.752 24.754 23.592 ;
     RECT  24.754 22.752 24.833 23.64 ;
     RECT  24.833 23.28 24.877 23.64 ;
     RECT  24.877 23.28 24.988 23.592 ;
     RECT  24.304 11.664 25.043 17.736 ;
     RECT  24.988 23.28 25.043 23.4 ;
     RECT  25.043 15.744 25.301 17.736 ;
     RECT  24.563 18.768 25.333 21.72 ;
     RECT  25.333 18.144 25.417 21.72 ;
     RECT  25.417 18.24 25.427 21.72 ;
     RECT  25.301 15.744 25.445 17.016 ;
     RECT  25.427 18.768 25.517 21.72 ;
     RECT  24.581 1.728 26.125 8.232 ;
     RECT  25.517 18.816 26.197 21.72 ;
     RECT  26.125 1.248 26.291 8.232 ;
     RECT  26.197 18.816 26.449 22.2 ;
     RECT  25.043 11.664 26.521 14.76 ;
     RECT  25.445 15.744 26.521 16.92 ;
     RECT  26.485 0.144 26.581 0.168 ;
     RECT  26.449 18.816 26.675 22.824 ;
     RECT  26.291 1.728 26.708 8.232 ;
     RECT  26.521 11.664 26.708 16.92 ;
     RECT  26.675 18.816 26.708 21.768 ;
     RECT  26.581 0.144 26.771 0.264 ;
     RECT  26.708 1.728 26.908 21.768 ;
     RECT  26.908 1.728 27.004 21.672 ;
     RECT  26.917 23.28 27.013 23.4 ;
     RECT  26.771 0.144 27.203 0.168 ;
     RECT  27.013 23.28 27.301 23.544 ;
     RECT  27.004 11.664 28.021 17.064 ;
     RECT  27.301 23.28 28.069 23.64 ;
     RECT  27.004 19.872 28.117 21.672 ;
     RECT  28.117 19.776 28.165 21.672 ;
     RECT  28.069 23.232 28.307 23.64 ;
     RECT  28.307 23.28 28.541 23.64 ;
     RECT  28.165 19.632 28.645 21.672 ;
     RECT  28.645 19.536 28.825 21.672 ;
     RECT  28.825 19.152 28.897 21.672 ;
     RECT  28.897 18.864 29.113 21.672 ;
     RECT  29.077 0.192 29.173 0.216 ;
     RECT  29.173 0.192 29.269 0.264 ;
     RECT  29.269 0.144 29.363 0.264 ;
     RECT  27.004 1.728 29.408 8.232 ;
     RECT  28.021 11.664 29.408 17.64 ;
     RECT  29.113 18.864 29.408 22.248 ;
     RECT  29.363 0.144 29.459 0.216 ;
     RECT  29.459 0.144 29.555 0.168 ;
     RECT  29.408 1.728 29.651 22.248 ;
     RECT  29.651 1.728 29.704 21.768 ;
     RECT  29.704 11.136 29.765 21.768 ;
     RECT  28.541 23.376 29.941 23.64 ;
     RECT  29.941 23.28 30.061 23.64 ;
     RECT  30.061 23.28 30.181 23.592 ;
     RECT  30.757 0.336 30.853 0.36 ;
     RECT  30.853 0.24 30.899 0.36 ;
     RECT  29.765 11.136 30.953 21.576 ;
     RECT  30.953 12.576 30.997 21.576 ;
     RECT  30.899 0.24 31.043 0.264 ;
     RECT  30.181 22.752 31.205 23.592 ;
     RECT  29.704 1.728 31.525 8.232 ;
     RECT  31.205 23.328 31.762 23.592 ;
     RECT  31.762 23.328 31.859 23.64 ;
     RECT  30.997 12.576 32.005 21.672 ;
     RECT  32.005 12.576 32.101 21.72 ;
     RECT  31.525 1.728 32.108 9.144 ;
     RECT  30.953 11.136 32.108 11.16 ;
     RECT  32.101 12.576 32.108 21.768 ;
     RECT  31.957 0.144 32.147 0.168 ;
     RECT  32.108 1.728 32.293 21.768 ;
     RECT  32.293 1.728 32.389 21.816 ;
     RECT  32.389 1.728 32.404 21.912 ;
     RECT  31.859 23.328 32.485 23.592 ;
     RECT  32.404 1.728 32.537 8.808 ;
     RECT  32.485 23.28 33.202 23.592 ;
     RECT  32.404 12.816 33.445 21.912 ;
     RECT  33.202 23.28 33.445 23.64 ;
     RECT  32.537 1.728 34.193 4.728 ;
     RECT  33.445 12.816 34.201 23.64 ;
     RECT  34.201 12.816 34.297 23.592 ;
     RECT  34.193 1.824 34.808 4.728 ;
     RECT  32.537 6 34.808 8.808 ;
     RECT  32.404 11.136 34.808 11.16 ;
     RECT  34.297 12.336 34.808 23.592 ;
     RECT  34.789 0.144 34.885 0.168 ;
     RECT  34.808 1.824 35.104 23.592 ;
     RECT  34.885 0.144 35.219 0.408 ;
     RECT  35.219 0.144 35.267 0.216 ;
     RECT  35.104 1.824 35.269 8.808 ;
     RECT  35.104 12.336 35.309 23.592 ;
     RECT  35.267 0.192 35.363 0.216 ;
     RECT  35.309 12.336 35.363 21.576 ;
     RECT  35.363 12.384 35.651 21.576 ;
     RECT  35.651 12.576 35.921 21.576 ;
     RECT  35.309 22.656 36.037 23.592 ;
     RECT  36.037 22.656 36.389 23.64 ;
     RECT  36.389 22.656 36.572 23.592 ;
     RECT  36.572 22.224 36.659 23.592 ;
     RECT  36.659 22.752 36.947 23.592 ;
     RECT  35.921 12.576 37.093 21.192 ;
     RECT  35.269 1.728 37.508 8.808 ;
     RECT  37.093 12.576 37.508 21.24 ;
     RECT  37.333 0.144 37.669 0.168 ;
     RECT  37.669 0.144 37.765 0.36 ;
     RECT  37.508 1.728 37.765 21.612 ;
     RECT  37.765 1.728 37.804 21.72 ;
     RECT  37.804 12.864 37.865 21.72 ;
     RECT  36.947 23.52 37.909 23.592 ;
     RECT  37.909 23.376 37.925 23.592 ;
     RECT  37.765 0.144 37.954 0.456 ;
     RECT  37.925 23.376 37.969 23.64 ;
     RECT  37.954 0.096 38.003 0.456 ;
     RECT  37.865 12.864 38.009 21.096 ;
     RECT  37.969 23.328 38.009 23.64 ;
     RECT  38.009 23.328 38.077 23.592 ;
     RECT  38.003 0.096 38.099 0.312 ;
     RECT  38.077 23.28 38.147 23.592 ;
     RECT  38.099 0.192 38.195 0.312 ;
     RECT  38.147 23.28 38.233 23.496 ;
     RECT  38.009 18.192 38.477 21.096 ;
     RECT  37.804 1.728 38.531 8.808 ;
     RECT  38.195 0.192 38.621 0.216 ;
     RECT  38.531 1.728 38.627 7.704 ;
     RECT  38.009 12.864 38.729 17.064 ;
     RECT  38.477 18.24 38.833 21.096 ;
     RECT  38.833 18.24 38.933 21.144 ;
     RECT  38.627 1.728 39.059 7.128 ;
     RECT  38.933 18.24 39.077 21.24 ;
     RECT  38.329 22.8 39.077 22.824 ;
     RECT  39.077 18.24 39.161 22.824 ;
     RECT  39.059 1.728 39.203 6.6 ;
     RECT  38.729 13.104 39.397 17.064 ;
     RECT  39.161 22.8 39.635 22.824 ;
     RECT  39.925 0.144 39.973 0.168 ;
     RECT  39.973 0.144 40.021 0.36 ;
     RECT  39.203 1.728 40.021 6.408 ;
     RECT  40.021 0.144 40.208 6.408 ;
     RECT  38.531 8.784 40.208 8.808 ;
     RECT  39.085 10.848 40.208 10.872 ;
     RECT  39.397 13.104 40.208 17.16 ;
     RECT  39.161 18.24 40.208 21.528 ;
     RECT  40.208 0.144 40.211 21.612 ;
     RECT  40.211 1.728 40.504 21.612 ;
     RECT  40.504 12.24 40.643 18.216 ;
     RECT  40.211 0.144 40.69 0.36 ;
     RECT  39.877 23.328 40.741 23.64 ;
     RECT  40.69 0.096 40.789 0.36 ;
     RECT  40.789 0.144 40.922 0.36 ;
     RECT  40.922 0.192 40.961 0.36 ;
     RECT  40.961 0.192 40.979 0.312 ;
     RECT  40.741 23.28 40.997 23.64 ;
     RECT  40.979 0.192 41.005 0.216 ;
     RECT  40.997 23.28 41.027 23.448 ;
     RECT  40.504 8.784 41.069 8.808 ;
     RECT  40.504 19.344 41.125 21.612 ;
     RECT  41.125 19.344 41.173 21.672 ;
     RECT  41.66 22.8 41.747 22.824 ;
     RECT  40.643 12.528 41.797 18.216 ;
     RECT  41.173 19.344 41.797 21.768 ;
     RECT  41.797 12.528 41.825 21.768 ;
     RECT  41.825 13.344 42.173 21.768 ;
     RECT  42.173 13.344 42.757 22.2 ;
     RECT  40.504 1.728 42.908 5.496 ;
     RECT  42.757 13.344 42.908 22.776 ;
     RECT  42.908 1.728 43.204 22.776 ;
     RECT  43.045 0.144 43.331 0.168 ;
     RECT  43.204 13.152 43.333 22.776 ;
     RECT  43.333 13.152 43.397 23.448 ;
     RECT  43.397 13.152 43.474 23.592 ;
     RECT  43.474 13.152 43.769 23.64 ;
     RECT  43.769 13.152 43.907 23.544 ;
     RECT  43.204 1.728 44.129 5.496 ;
     RECT  43.907 13.152 44.233 22.776 ;
     RECT  44.233 12.72 44.381 22.776 ;
     RECT  44.381 12.72 44.435 22.728 ;
     RECT  44.435 12.72 44.593 21.24 ;
     RECT  44.593 12.576 44.665 21.24 ;
     RECT  44.435 22.224 45.137 22.728 ;
     RECT  44.665 12.528 45.529 21.24 ;
     RECT  44.129 1.728 45.608 5.112 ;
     RECT  43.204 11.424 45.608 11.448 ;
     RECT  45.529 12.528 45.608 22.2 ;
     RECT  45.608 1.728 45.683 22.2 ;
     RECT  45.733 0.432 45.829 0.456 ;
     RECT  45.683 1.728 45.904 21.672 ;
     RECT  45.829 0.432 45.925 0.552 ;
     RECT  45.925 0.336 46.021 0.552 ;
     RECT  46.021 0.24 46.067 0.552 ;
     RECT  46.067 0.24 46.076 0.36 ;
     RECT  45.904 16.848 46.109 21.672 ;
     RECT  46.076 0.096 46.115 0.36 ;
     RECT  46.115 0.096 46.163 0.264 ;
     RECT  45.904 10.848 46.253 11.448 ;
     RECT  45.904 12.48 46.289 15.816 ;
     RECT  45.733 23.472 46.429 23.64 ;
     RECT  45.904 1.728 46.451 5.112 ;
     RECT  46.429 23.328 46.657 23.64 ;
     RECT  46.109 19.344 46.685 21.672 ;
     RECT  46.657 23.328 46.765 23.592 ;
     RECT  46.109 16.848 46.797 18.264 ;
     RECT  46.797 18.24 46.883 18.264 ;
     RECT  46.289 13.152 47.125 15.816 ;
     RECT  46.797 16.848 47.125 17.256 ;
     RECT  46.253 10.848 47.153 10.872 ;
     RECT  46.685 19.344 47.42 21.336 ;
     RECT  46.451 1.728 47.473 4.728 ;
     RECT  47.42 18.816 47.749 21.336 ;
     RECT  47.749 18.816 47.893 21.528 ;
     RECT  47.893 18.768 47.977 21.528 ;
     RECT  47.077 22.752 47.977 22.776 ;
     RECT  47.125 13.152 48.044 17.256 ;
     RECT  47.977 18.768 48.085 22.776 ;
     RECT  48.044 13.152 48.133 17.688 ;
     RECT  48.085 18.768 48.133 23.592 ;
     RECT  48.085 0.144 48.181 0.168 ;
     RECT  47.473 1.728 48.308 5.112 ;
     RECT  48.133 13.152 48.308 23.592 ;
     RECT  48.181 0.144 48.467 0.264 ;
     RECT  48.308 1.728 48.604 23.592 ;
     RECT  48.604 13.68 48.757 23.592 ;
     RECT  48.467 0.144 48.803 0.168 ;
     RECT  48.757 13.68 48.845 23.736 ;
     RECT  48.845 13.68 48.889 23.64 ;
     RECT  48.604 1.728 48.956 4.728 ;
     RECT  48.956 1.152 49.089 4.728 ;
     RECT  49.089 1.728 49.177 4.728 ;
     RECT  48.889 13.68 49.187 23.592 ;
     RECT  49.187 23.568 50.149 23.592 ;
     RECT  49.177 2.256 50.173 4.728 ;
     RECT  49.187 13.68 50.341 22.344 ;
     RECT  50.149 23.568 50.341 23.64 ;
     RECT  50.341 13.68 50.461 23.64 ;
     RECT  50.173 2.256 50.597 5.496 ;
     RECT  50.461 13.296 50.713 23.64 ;
     RECT  50.773 0.144 50.869 0.168 ;
     RECT  50.869 0.144 50.963 0.264 ;
     RECT  50.597 1.728 51.008 5.496 ;
     RECT  50.317 6.816 51.008 6.84 ;
     RECT  50.317 10.896 51.008 10.92 ;
     RECT  50.713 13.104 51.008 23.64 ;
     RECT  50.963 0.24 51.059 0.264 ;
     RECT  51.008 1.728 51.304 23.64 ;
     RECT  51.304 13.056 51.443 23.64 ;
     RECT  51.452 0.528 51.539 0.552 ;
     RECT  51.304 11.952 52.309 11.976 ;
     RECT  52.309 11.328 52.445 11.976 ;
     RECT  52.445 11.952 52.499 11.976 ;
     RECT  52.549 12 53.377 12.024 ;
     RECT  51.443 13.104 53.377 23.64 ;
     RECT  53.377 12 53.557 23.64 ;
     RECT  53.557 0.24 53.605 0.264 ;
     RECT  51.304 1.728 53.708 6.024 ;
     RECT  51.304 8.784 53.708 8.808 ;
     RECT  53.557 11.76 53.708 23.64 ;
     RECT  53.605 0.24 53.941 0.36 ;
     RECT  53.708 1.728 54.004 23.64 ;
     RECT  53.941 0.144 54.131 0.36 ;
     RECT  54.004 10.416 54.179 23.64 ;
     RECT  54.179 23.328 54.323 23.64 ;
     RECT  54.323 23.424 54.659 23.64 ;
     RECT  54.659 23.616 54.929 23.64 ;
     RECT  54.179 10.416 55.573 22.2 ;
     RECT  55.573 10.176 55.765 22.2 ;
     RECT  54.004 1.728 56.408 7.128 ;
     RECT  54.004 8.784 56.408 8.808 ;
     RECT  55.765 10.176 56.408 21.768 ;
     RECT  56.408 1.728 56.435 21.768 ;
     RECT  56.245 0.144 56.581 0.168 ;
     RECT  56.485 23.424 56.581 23.448 ;
     RECT  56.435 1.728 56.704 21.72 ;
     RECT  56.704 9.936 56.723 21.72 ;
     RECT  56.581 23.424 56.773 23.544 ;
     RECT  56.581 0.144 56.818 0.408 ;
     RECT  56.818 0.096 56.917 0.408 ;
     RECT  56.917 0.144 57.025 0.408 ;
     RECT  56.773 23.424 57.061 23.64 ;
     RECT  57.061 23.376 57.125 23.64 ;
     RECT  56.704 1.728 57.299 6.024 ;
     RECT  57.299 1.728 57.395 4.776 ;
     RECT  56.723 9.936 57.685 21.672 ;
     RECT  57.685 9.936 57.881 21.816 ;
     RECT  56.704 8.784 57.971 8.808 ;
     RECT  57.589 0.528 58.021 0.552 ;
     RECT  57.881 9.984 58.025 21.816 ;
     RECT  58.025 10.224 58.117 21.816 ;
     RECT  57.125 23.376 58.117 23.592 ;
     RECT  58.021 0.528 58.355 0.6 ;
     RECT  58.117 10.224 58.493 23.592 ;
     RECT  58.355 0.528 58.525 0.552 ;
     RECT  58.525 0.144 58.547 0.552 ;
     RECT  57.395 1.728 59.108 3.72 ;
     RECT  57.395 4.704 59.108 4.776 ;
     RECT  57.299 6 59.108 6.024 ;
     RECT  56.704 7.104 59.108 7.128 ;
     RECT  58.493 10.224 59.108 22.296 ;
     RECT  59.108 1.728 59.404 22.296 ;
     RECT  59.404 10.608 59.461 22.296 ;
     RECT  58.493 23.424 59.461 23.592 ;
     RECT  59.461 10.608 59.554 23.592 ;
     RECT  58.547 0.144 59.555 0.168 ;
     RECT  59.554 10.608 59.795 23.64 ;
     RECT  59.795 10.608 60.659 22.152 ;
     RECT  59.795 23.28 60.805 23.64 ;
     RECT  60.659 10.608 60.829 21.672 ;
     RECT  60.805 22.752 60.977 23.64 ;
     RECT  60.977 23.328 61.139 23.64 ;
     RECT  59.404 1.728 61.541 4.776 ;
     RECT  61.541 1.152 61.621 4.776 ;
     RECT  61.621 1.152 61.669 4.968 ;
     RECT  60.829 9.936 61.765 21.672 ;
     RECT  61.669 1.152 61.808 5.064 ;
     RECT  59.404 7.104 61.808 7.128 ;
     RECT  61.765 9.936 61.808 21.816 ;
     RECT  61.621 0.144 61.811 0.168 ;
     RECT  61.808 1.152 62.053 21.816 ;
     RECT  62.053 1.152 62.104 21.864 ;
     RECT  62.104 1.152 62.201 2.28 ;
     RECT  62.104 14.832 62.201 21.864 ;
     RECT  61.139 23.376 62.245 23.64 ;
     RECT  62.201 2.256 62.291 2.28 ;
     RECT  62.104 10.368 62.339 13.704 ;
     RECT  62.104 3.696 62.345 4.584 ;
     RECT  62.339 10.368 62.381 13.128 ;
     RECT  62.381 10.368 62.417 12.024 ;
     RECT  62.381 13.104 62.435 13.128 ;
     RECT  62.104 5.712 62.483 5.736 ;
     RECT  62.201 14.832 62.579 18.264 ;
     RECT  62.513 0.096 62.597 0.12 ;
     RECT  62.269 1.104 62.675 1.128 ;
     RECT  62.417 10.704 62.705 12.024 ;
     RECT  62.705 10.704 62.777 10.728 ;
     RECT  62.345 3.984 62.785 4.584 ;
     RECT  62.579 15.408 62.813 18.264 ;
     RECT  62.201 19.344 62.881 21.864 ;
     RECT  62.785 4.56 62.893 4.584 ;
     RECT  62.813 15.408 62.915 18.216 ;
     RECT  62.705 12 63.011 12.024 ;
     RECT  62.915 15.984 63.059 18.216 ;
     RECT  63.059 16.56 63.107 18.216 ;
     RECT  62.881 19.344 63.133 22.248 ;
     RECT  62.245 23.232 63.133 23.64 ;
     RECT  63.133 19.344 63.196 23.64 ;
     RECT  63.107 16.656 63.203 18.216 ;
     RECT  63.203 17.616 63.209 18.216 ;
     RECT  63.196 20.592 63.217 23.64 ;
     RECT  63.277 19.296 63.443 19.32 ;
     RECT  63.217 20.976 63.539 23.64 ;
     RECT  63.539 20.976 63.569 22.2 ;
     RECT  63.209 18.192 63.635 18.216 ;
     RECT  63.569 20.976 63.713 21.672 ;
     RECT  63.713 21.072 63.827 21.672 ;
     RECT  63.539 23.616 63.929 23.64 ;
     RECT  63.827 21.072 63.965 21.48 ;
     RECT  63.965 21.072 64.037 21.432 ;
     RECT  64.037 21.408 64.073 21.432 ;
    LAYER M5 ;
     RECT  0.744 0.016 0.816 0.084 ;
     RECT  0.84 0.016 0.912 0.084 ;
     RECT  0.936 0.016 1.008 0.084 ;
     RECT  1.032 0.016 1.104 0.084 ;
     RECT  1.128 0.016 1.2 0.084 ;
     RECT  1.224 0.016 1.296 0.084 ;
     RECT  1.32 0.016 1.392 0.084 ;
     RECT  1.416 0.016 1.488 0.084 ;
     RECT  1.512 0.016 1.584 0.084 ;
     RECT  1.608 0.016 1.68 0.084 ;
     RECT  1.704 0.016 1.776 0.084 ;
     RECT  1.8 0.016 1.872 0.084 ;
     RECT  1.896 0.016 1.968 0.084 ;
     RECT  1.992 0.016 2.064 0.084 ;
     RECT  2.088 0.016 2.16 0.084 ;
     RECT  2.184 0.016 2.256 0.084 ;
     RECT  2.28 0.016 2.352 0.084 ;
     RECT  2.376 0.016 2.448 0.084 ;
     RECT  2.472 0.016 2.544 0.084 ;
     RECT  2.568 0.016 2.64 0.084 ;
     RECT  2.664 0.016 2.736 0.084 ;
     RECT  2.76 0.016 2.832 0.084 ;
     RECT  2.856 0.016 2.928 0.084 ;
     RECT  2.952 0.016 3.024 0.084 ;
     RECT  3.048 0.016 3.12 0.084 ;
     RECT  3.144 0.016 3.216 0.084 ;
     RECT  3.24 0.016 3.312 0.084 ;
     RECT  3.336 0.016 3.408 0.084 ;
     RECT  3.432 0.016 3.504 0.084 ;
     RECT  3.528 0.016 3.6 0.084 ;
     RECT  3.624 0.016 3.696 0.084 ;
     RECT  3.72 0.016 3.792 0.084 ;
     RECT  3.816 0.016 3.888 0.084 ;
     RECT  3.912 0.016 3.984 0.084 ;
     RECT  4.008 0.016 4.08 0.084 ;
     RECT  4.104 0.016 4.176 0.084 ;
     RECT  4.2 0.016 4.272 0.084 ;
     RECT  4.296 0.016 4.368 0.084 ;
     RECT  4.392 0.016 4.464 0.084 ;
     RECT  4.488 0.016 4.56 0.084 ;
     RECT  4.584 0.016 4.656 0.084 ;
     RECT  4.68 0.016 4.752 0.084 ;
     RECT  4.776 0.016 4.848 0.084 ;
     RECT  4.872 0.016 4.944 0.084 ;
     RECT  4.968 0.016 5.04 0.084 ;
     RECT  5.064 0.016 5.136 0.084 ;
     RECT  5.16 0.016 5.232 0.084 ;
     RECT  5.256 0.016 5.328 0.084 ;
     RECT  5.352 0.016 5.424 0.084 ;
     RECT  5.448 0.016 5.52 0.084 ;
     RECT  5.544 0.016 5.616 0.084 ;
     RECT  5.64 0.016 5.712 0.084 ;
     RECT  5.736 0.016 5.808 0.084 ;
     RECT  5.832 0.016 5.904 0.084 ;
     RECT  5.928 0.016 6 0.084 ;
     RECT  6.024 0.016 6.096 0.084 ;
     RECT  6.12 0.016 6.192 0.084 ;
     RECT  6.216 0.016 6.288 0.084 ;
     RECT  6.312 0.016 6.384 0.084 ;
     RECT  6.408 0.016 6.48 0.084 ;
     RECT  6.504 0.016 6.576 0.084 ;
     RECT  6.6 0.016 6.672 0.084 ;
     RECT  6.696 0.016 6.768 0.084 ;
     RECT  6.792 0.016 6.864 0.084 ;
     RECT  6.888 0.016 6.96 0.084 ;
     RECT  6.984 0.016 7.056 0.084 ;
     RECT  7.08 0.016 7.152 0.084 ;
     RECT  7.176 0.016 7.248 0.084 ;
     RECT  7.272 0.016 7.344 0.084 ;
     RECT  7.368 0.016 7.44 0.084 ;
     RECT  7.464 0.016 7.536 0.084 ;
     RECT  7.56 0.016 7.632 0.084 ;
     RECT  7.656 0.016 7.728 0.084 ;
     RECT  7.752 0.016 7.824 0.084 ;
     RECT  7.848 0.016 7.92 0.084 ;
     RECT  7.944 0.016 8.016 0.084 ;
     RECT  8.04 0.016 8.112 0.084 ;
     RECT  8.136 0.016 8.208 0.084 ;
     RECT  8.232 0.016 8.304 0.084 ;
     RECT  8.328 0.016 8.4 0.084 ;
     RECT  8.424 0.016 8.496 0.084 ;
     RECT  8.52 0.016 8.592 0.084 ;
     RECT  8.616 0.016 8.688 0.084 ;
     RECT  8.712 0.016 8.784 0.084 ;
     RECT  8.808 0.016 8.88 0.084 ;
     RECT  8.904 0.016 8.976 0.084 ;
     RECT  9 0.016 9.072 0.084 ;
     RECT  9.096 0.016 9.168 0.084 ;
     RECT  9.192 0.016 9.264 0.084 ;
     RECT  9.288 0.016 9.36 0.084 ;
     RECT  9.384 0.016 9.456 0.084 ;
     RECT  9.48 0.016 9.552 0.084 ;
     RECT  9.576 0.016 9.648 0.084 ;
     RECT  9.672 0.016 9.744 0.084 ;
     RECT  9.768 0.016 9.84 0.084 ;
     RECT  9.864 0.016 9.936 0.084 ;
     RECT  9.96 0.016 10.032 0.084 ;
     RECT  10.056 0.016 10.128 0.084 ;
     RECT  10.152 0.016 10.224 0.084 ;
     RECT  10.248 0.016 10.32 0.084 ;
     RECT  10.344 0.016 10.416 0.084 ;
     RECT  10.44 0.016 10.512 0.084 ;
     RECT  10.536 0.016 10.608 0.084 ;
     RECT  10.632 0.016 10.704 0.084 ;
     RECT  10.728 0.016 10.8 0.084 ;
     RECT  10.824 0.016 10.896 0.084 ;
     RECT  10.92 0.016 10.992 0.084 ;
     RECT  11.016 0.016 11.088 0.084 ;
     RECT  11.112 0.016 11.184 0.084 ;
     RECT  11.208 0.016 11.28 0.084 ;
     RECT  11.304 0.016 11.376 0.084 ;
     RECT  11.4 0.016 11.472 0.084 ;
     RECT  11.496 0.016 11.568 0.084 ;
     RECT  11.592 0.016 11.664 0.084 ;
     RECT  11.688 0.016 11.76 0.084 ;
     RECT  11.784 0.016 11.856 0.084 ;
     RECT  11.88 0.016 11.952 0.084 ;
     RECT  11.976 0.016 12.048 0.084 ;
     RECT  12.072 0.016 12.144 0.084 ;
     RECT  12.168 0.016 12.24 0.084 ;
     RECT  12.264 0.016 12.336 0.084 ;
     RECT  12.36 0.016 12.432 0.084 ;
     RECT  12.456 0.016 12.528 0.084 ;
     RECT  12.552 0.016 12.624 0.084 ;
     RECT  12.648 0.016 12.72 0.084 ;
     RECT  12.744 0.016 12.816 0.084 ;
     RECT  12.84 0.016 12.912 0.084 ;
     RECT  12.936 0.016 13.008 0.084 ;
     RECT  13.032 0.016 13.104 0.084 ;
     RECT  13.128 0.016 13.2 0.084 ;
     RECT  13.224 0.016 13.296 0.084 ;
     RECT  13.32 0.016 13.392 0.084 ;
     RECT  13.416 0.016 13.488 0.084 ;
     RECT  13.512 0.016 13.584 0.084 ;
     RECT  13.608 0.016 13.68 0.084 ;
     RECT  13.704 0.016 13.776 0.084 ;
     RECT  13.8 0.016 13.872 0.084 ;
     RECT  13.896 0.016 13.968 0.084 ;
     RECT  13.992 0.016 14.064 0.084 ;
     RECT  14.088 0.016 14.16 0.084 ;
     RECT  14.184 0.016 14.256 0.084 ;
     RECT  14.28 0.016 14.352 0.084 ;
     RECT  14.376 0.016 14.448 0.084 ;
     RECT  14.472 0.016 14.544 0.084 ;
     RECT  14.568 0.016 14.64 0.084 ;
     RECT  14.664 0.016 14.736 0.084 ;
     RECT  14.76 0.016 14.832 0.084 ;
     RECT  14.856 0.016 14.928 0.084 ;
     RECT  14.952 0.016 15.024 0.084 ;
     RECT  15.048 0.016 15.12 0.084 ;
     RECT  15.144 0.016 15.216 0.084 ;
     RECT  15.24 0.016 15.312 0.084 ;
     RECT  15.336 0.016 15.408 0.084 ;
     RECT  15.432 0.016 15.504 0.084 ;
     RECT  15.528 0.016 15.6 0.084 ;
     RECT  15.624 0.016 15.696 0.084 ;
     RECT  15.72 0.016 15.792 0.084 ;
     RECT  15.816 0.016 15.888 0.084 ;
     RECT  15.912 0.016 15.984 0.084 ;
     RECT  16.008 0.016 16.08 0.084 ;
     RECT  16.104 0.016 16.176 0.084 ;
     RECT  16.2 0.016 16.272 0.084 ;
     RECT  16.296 0.016 16.368 0.084 ;
     RECT  16.392 0.016 16.464 0.084 ;
     RECT  16.488 0.016 16.56 0.084 ;
     RECT  16.584 0.016 16.656 0.084 ;
     RECT  16.68 0.016 16.752 0.084 ;
     RECT  16.776 0.016 16.848 0.084 ;
     RECT  16.872 0.016 16.944 0.084 ;
     RECT  16.968 0.016 17.04 0.084 ;
     RECT  17.064 0.016 17.136 0.084 ;
     RECT  17.16 0.016 17.232 0.084 ;
     RECT  17.256 0.016 17.328 0.084 ;
     RECT  17.352 0.016 17.424 0.084 ;
     RECT  17.448 0.016 17.52 0.084 ;
     RECT  17.544 0.016 17.616 0.084 ;
     RECT  17.64 0.016 17.712 0.084 ;
     RECT  17.736 0.016 17.808 0.084 ;
     RECT  17.832 0.016 17.904 0.084 ;
     RECT  17.928 0.016 18 0.084 ;
     RECT  18.024 0.016 18.096 0.084 ;
     RECT  18.12 0.016 18.192 0.084 ;
     RECT  18.216 0.016 18.288 0.084 ;
     RECT  18.312 0.016 18.384 0.084 ;
     RECT  18.408 0.016 18.48 0.084 ;
     RECT  18.504 0.016 18.576 0.084 ;
     RECT  18.6 0.016 18.672 0.084 ;
     RECT  18.696 0.016 18.768 0.084 ;
     RECT  18.792 0.016 18.864 0.084 ;
     RECT  18.888 0.016 18.96 0.084 ;
     RECT  18.984 0.016 19.056 0.084 ;
     RECT  19.08 0.016 19.92 0.084 ;
     RECT  19.944 0.016 20.016 0.084 ;
     RECT  20.04 0.016 20.112 0.084 ;
     RECT  20.136 0.016 20.208 0.084 ;
     RECT  20.232 0.016 20.304 0.084 ;
     RECT  20.328 0.016 20.4 0.084 ;
     RECT  20.424 0.016 20.496 0.084 ;
     RECT  20.52 0.016 20.592 0.084 ;
     RECT  20.616 0.016 20.688 0.084 ;
     RECT  20.712 0.016 20.784 0.084 ;
     RECT  20.808 0.016 20.88 0.084 ;
     RECT  20.904 0.016 20.976 0.084 ;
     RECT  21 0.016 21.072 0.084 ;
     RECT  21.096 0.016 21.168 0.084 ;
     RECT  21.192 0.016 21.264 0.084 ;
     RECT  21.288 0.016 21.36 0.084 ;
     RECT  21.384 0.016 21.456 0.084 ;
     RECT  21.48 0.016 21.552 0.084 ;
     RECT  21.576 0.016 21.648 0.084 ;
     RECT  21.672 0.016 21.744 0.084 ;
     RECT  21.768 0.016 21.84 0.084 ;
     RECT  21.864 0.016 21.936 0.084 ;
     RECT  21.96 0.016 22.032 0.084 ;
     RECT  22.056 0.016 22.128 0.084 ;
     RECT  22.152 0.016 22.224 0.084 ;
     RECT  22.248 0.016 22.32 0.084 ;
     RECT  22.344 0.016 22.416 0.084 ;
     RECT  22.44 0.016 22.512 0.084 ;
     RECT  22.536 0.016 22.608 0.084 ;
     RECT  22.632 0.016 22.704 0.084 ;
     RECT  22.728 0.016 22.8 0.084 ;
     RECT  22.824 0.016 22.896 0.084 ;
     RECT  22.92 0.016 22.992 0.084 ;
     RECT  23.016 0.016 23.088 0.084 ;
     RECT  23.112 0.016 23.184 0.084 ;
     RECT  23.208 0.016 23.28 0.084 ;
     RECT  23.304 0.016 23.376 0.084 ;
     RECT  23.4 0.016 23.472 0.084 ;
     RECT  23.496 0.016 23.568 0.084 ;
     RECT  23.592 0.016 23.664 0.084 ;
     RECT  23.688 0.016 23.76 0.084 ;
     RECT  23.784 0.016 23.856 0.084 ;
     RECT  23.88 0.016 23.952 0.084 ;
     RECT  23.976 0.016 24.048 0.084 ;
     RECT  24.072 0.016 24.144 0.084 ;
     RECT  24.168 0.016 24.24 0.084 ;
     RECT  24.264 0.016 24.336 0.084 ;
     RECT  24.36 0.016 24.432 0.084 ;
     RECT  24.456 0.016 24.528 0.084 ;
     RECT  24.552 0.016 24.624 0.084 ;
     RECT  24.648 0.016 24.72 0.084 ;
     RECT  24.744 0.016 24.816 0.084 ;
     RECT  24.84 0.016 24.912 0.084 ;
     RECT  24.936 0.016 25.008 0.084 ;
     RECT  25.032 0.016 25.104 0.084 ;
     RECT  25.128 0.016 25.2 0.084 ;
     RECT  25.224 0.016 25.296 0.084 ;
     RECT  25.32 0.016 25.392 0.084 ;
     RECT  25.416 0.016 25.488 0.084 ;
     RECT  25.512 0.016 25.584 0.084 ;
     RECT  25.608 0.016 25.68 0.084 ;
     RECT  25.704 0.016 25.776 0.084 ;
     RECT  25.8 0.016 25.872 0.084 ;
     RECT  25.896 0.016 25.968 0.084 ;
     RECT  25.992 0.016 26.064 0.084 ;
     RECT  26.088 0.016 26.16 0.084 ;
     RECT  26.184 0.016 26.256 0.084 ;
     RECT  26.28 0.016 26.352 0.084 ;
     RECT  26.376 0.016 26.448 0.084 ;
     RECT  26.472 0.016 26.544 0.084 ;
     RECT  26.568 0.016 26.64 0.084 ;
     RECT  26.664 0.016 26.736 0.084 ;
     RECT  26.76 0.016 26.832 0.084 ;
     RECT  26.856 0.016 26.928 0.084 ;
     RECT  26.952 0.016 27.024 0.084 ;
     RECT  27.048 0.016 27.12 0.084 ;
     RECT  27.144 0.016 27.216 0.084 ;
     RECT  27.24 0.016 27.312 0.084 ;
     RECT  27.336 0.016 27.408 0.084 ;
     RECT  27.432 0.016 27.504 0.084 ;
     RECT  27.528 0.016 27.6 0.084 ;
     RECT  27.624 0.016 27.696 0.084 ;
     RECT  27.72 0.016 27.792 0.084 ;
     RECT  27.816 0.016 27.888 0.084 ;
     RECT  27.912 0.016 27.984 0.084 ;
     RECT  28.008 0.016 28.08 0.084 ;
     RECT  28.104 0.016 28.176 0.084 ;
     RECT  28.2 0.016 28.272 0.084 ;
     RECT  28.296 0.016 28.368 0.084 ;
     RECT  28.392 0.016 28.464 0.084 ;
     RECT  28.488 0.016 28.56 0.084 ;
     RECT  28.584 0.016 28.656 0.084 ;
     RECT  28.68 0.016 28.752 0.084 ;
     RECT  28.776 0.016 28.848 0.084 ;
     RECT  28.872 0.016 28.944 0.084 ;
     RECT  28.968 0.016 29.04 0.084 ;
     RECT  29.064 0.016 29.136 0.084 ;
     RECT  29.16 0.016 29.232 0.084 ;
     RECT  29.256 0.016 29.328 0.084 ;
     RECT  29.352 0.016 29.424 0.084 ;
     RECT  29.448 0.016 29.52 0.084 ;
     RECT  29.544 0.016 29.616 0.084 ;
     RECT  29.64 0.016 29.712 0.084 ;
     RECT  29.736 0.016 29.808 0.084 ;
     RECT  29.832 0.016 29.904 0.084 ;
     RECT  29.928 0.016 30 0.084 ;
     RECT  30.024 0.016 30.096 0.084 ;
     RECT  30.12 0.016 30.192 0.084 ;
     RECT  30.216 0.016 30.288 0.084 ;
     RECT  30.312 0.016 30.384 0.084 ;
     RECT  30.408 0.016 30.48 0.084 ;
     RECT  30.504 0.016 30.576 0.084 ;
     RECT  30.6 0.016 30.672 0.084 ;
     RECT  30.696 0.016 30.768 0.084 ;
     RECT  30.792 0.016 30.864 0.084 ;
     RECT  30.888 0.016 30.96 0.084 ;
     RECT  30.984 0.016 31.056 0.084 ;
     RECT  31.08 0.016 31.152 0.084 ;
     RECT  31.176 0.016 31.248 0.084 ;
     RECT  31.272 0.016 31.344 0.084 ;
     RECT  31.368 0.016 31.44 0.084 ;
     RECT  31.464 0.016 31.536 0.084 ;
     RECT  31.56 0.016 31.632 0.084 ;
     RECT  31.656 0.016 31.728 0.084 ;
     RECT  31.752 0.016 31.824 0.084 ;
     RECT  31.848 0.016 31.92 0.084 ;
     RECT  31.944 0.016 32.016 0.084 ;
     RECT  32.04 0.016 32.112 0.084 ;
     RECT  32.136 0.016 32.208 0.084 ;
     RECT  32.232 0.016 32.304 0.084 ;
     RECT  32.328 0.016 32.4 0.084 ;
     RECT  32.424 0.016 32.496 0.084 ;
     RECT  32.52 0.016 32.592 0.084 ;
     RECT  32.616 0.016 32.688 0.084 ;
     RECT  32.712 0.016 32.784 0.084 ;
     RECT  32.808 0.016 32.88 0.084 ;
     RECT  32.904 0.016 32.976 0.084 ;
     RECT  33 0.016 33.072 0.084 ;
     RECT  33.096 0.016 33.168 0.084 ;
     RECT  33.192 0.016 33.264 0.084 ;
     RECT  33.288 0.016 33.36 0.084 ;
     RECT  33.384 0.016 33.456 0.084 ;
     RECT  33.48 0.016 33.552 0.084 ;
     RECT  33.576 0.016 33.648 0.084 ;
     RECT  33.672 0.016 33.744 0.084 ;
     RECT  33.768 0.016 33.84 0.084 ;
     RECT  33.864 0.016 33.936 0.084 ;
     RECT  33.96 0.016 34.032 0.084 ;
     RECT  34.056 0.016 34.128 0.084 ;
     RECT  34.152 0.016 34.224 0.084 ;
     RECT  34.248 0.016 34.32 0.084 ;
     RECT  34.344 0.016 34.416 0.084 ;
     RECT  34.44 0.016 34.512 0.084 ;
     RECT  34.536 0.016 34.608 0.084 ;
     RECT  34.632 0.016 34.704 0.084 ;
     RECT  34.728 0.016 34.8 0.084 ;
     RECT  34.824 0.016 34.896 0.084 ;
     RECT  34.92 0.016 34.992 0.084 ;
     RECT  35.016 0.016 35.088 0.084 ;
     RECT  35.112 0.016 35.184 0.084 ;
     RECT  35.208 0.016 35.28 0.084 ;
     RECT  35.304 0.016 35.376 0.084 ;
     RECT  35.4 0.016 35.472 0.084 ;
     RECT  35.496 0.016 35.568 0.084 ;
     RECT  35.592 0.016 35.664 0.084 ;
     RECT  35.688 0.016 35.76 0.084 ;
     RECT  35.784 0.016 35.856 0.084 ;
     RECT  35.88 0.016 35.952 0.084 ;
     RECT  35.976 0.016 36.048 0.084 ;
     RECT  36.072 0.016 36.144 0.084 ;
     RECT  36.168 0.016 36.24 0.084 ;
     RECT  36.264 0.016 36.336 0.084 ;
     RECT  36.36 0.016 36.432 0.084 ;
     RECT  36.456 0.016 36.528 0.084 ;
     RECT  36.552 0.016 36.624 0.084 ;
     RECT  36.648 0.016 36.72 0.084 ;
     RECT  36.744 0.016 36.816 0.084 ;
     RECT  36.84 0.016 36.912 0.084 ;
     RECT  36.936 0.016 37.008 0.084 ;
     RECT  37.032 0.016 37.104 0.084 ;
     RECT  37.128 0.016 37.2 0.084 ;
     RECT  37.224 0.016 37.296 0.084 ;
     RECT  37.32 0.016 37.392 0.084 ;
     RECT  37.416 0.016 37.488 0.084 ;
     RECT  37.512 0.016 37.584 0.084 ;
     RECT  37.608 0.016 37.68 0.084 ;
     RECT  37.704 0.016 37.776 0.084 ;
     RECT  37.8 0.016 37.872 0.084 ;
     RECT  37.896 0.016 37.968 0.084 ;
     RECT  37.992 0.016 38.064 0.084 ;
     RECT  38.088 0.016 38.16 0.084 ;
     RECT  38.184 0.016 38.256 0.084 ;
     RECT  38.28 0.016 39.12 0.084 ;
     RECT  39.144 0.016 39.216 0.084 ;
     RECT  39.24 0.016 39.312 0.084 ;
     RECT  39.336 0.016 39.408 0.084 ;
     RECT  39.432 0.016 39.504 0.084 ;
     RECT  39.528 0.016 39.6 0.084 ;
     RECT  39.624 0.016 39.696 0.084 ;
     RECT  39.72 0.016 39.792 0.084 ;
     RECT  39.816 0.016 39.888 0.084 ;
     RECT  39.912 0.016 39.984 0.084 ;
     RECT  40.008 0.016 40.08 0.084 ;
     RECT  40.104 0.016 40.176 0.084 ;
     RECT  40.2 0.016 40.272 0.084 ;
     RECT  40.296 0.016 40.368 0.084 ;
     RECT  40.392 0.016 40.464 0.084 ;
     RECT  40.488 0.016 40.56 0.084 ;
     RECT  40.584 0.016 40.656 0.084 ;
     RECT  40.68 0.016 40.752 0.084 ;
     RECT  40.776 0.016 40.848 0.084 ;
     RECT  40.872 0.016 40.944 0.084 ;
     RECT  40.968 0.016 41.04 0.084 ;
     RECT  41.064 0.016 41.136 0.084 ;
     RECT  41.16 0.016 41.232 0.084 ;
     RECT  41.256 0.016 41.328 0.084 ;
     RECT  41.352 0.016 41.424 0.084 ;
     RECT  41.448 0.016 41.52 0.084 ;
     RECT  41.544 0.016 41.616 0.084 ;
     RECT  41.64 0.016 41.712 0.084 ;
     RECT  41.736 0.016 41.808 0.084 ;
     RECT  41.832 0.016 41.904 0.084 ;
     RECT  41.928 0.016 42 0.084 ;
     RECT  42.024 0.016 42.096 0.084 ;
     RECT  42.12 0.016 42.192 0.084 ;
     RECT  42.216 0.016 42.288 0.084 ;
     RECT  42.312 0.016 42.384 0.084 ;
     RECT  42.408 0.016 42.48 0.084 ;
     RECT  42.504 0.016 42.576 0.084 ;
     RECT  42.6 0.016 42.672 0.084 ;
     RECT  42.696 0.016 42.768 0.084 ;
     RECT  42.792 0.016 42.864 0.084 ;
     RECT  42.888 0.016 42.96 0.084 ;
     RECT  42.984 0.016 43.056 0.084 ;
     RECT  43.08 0.016 43.152 0.084 ;
     RECT  43.176 0.016 43.248 0.084 ;
     RECT  43.272 0.016 43.344 0.084 ;
     RECT  43.368 0.016 43.44 0.084 ;
     RECT  43.464 0.016 43.536 0.084 ;
     RECT  43.56 0.016 43.632 0.084 ;
     RECT  43.656 0.016 43.728 0.084 ;
     RECT  43.752 0.016 43.824 0.084 ;
     RECT  43.848 0.016 43.92 0.084 ;
     RECT  43.944 0.016 44.016 0.084 ;
     RECT  44.04 0.016 44.112 0.084 ;
     RECT  44.136 0.016 44.208 0.084 ;
     RECT  44.232 0.016 44.304 0.084 ;
     RECT  44.328 0.016 44.4 0.084 ;
     RECT  44.424 0.016 44.496 0.084 ;
     RECT  44.52 0.016 44.592 0.084 ;
     RECT  44.616 0.016 44.688 0.084 ;
     RECT  44.712 0.016 44.784 0.084 ;
     RECT  44.808 0.016 44.88 0.084 ;
     RECT  44.904 0.016 44.976 0.084 ;
     RECT  45 0.016 45.072 0.084 ;
     RECT  45.096 0.016 45.168 0.084 ;
     RECT  45.192 0.016 45.264 0.084 ;
     RECT  45.288 0.016 45.36 0.084 ;
     RECT  45.384 0.016 45.456 0.084 ;
     RECT  45.48 0.016 45.552 0.084 ;
     RECT  45.576 0.016 45.648 0.084 ;
     RECT  45.672 0.016 45.744 0.084 ;
     RECT  45.768 0.016 45.84 0.084 ;
     RECT  45.864 0.016 45.936 0.084 ;
     RECT  45.96 0.016 46.032 0.084 ;
     RECT  46.056 0.016 46.128 0.084 ;
     RECT  46.152 0.016 46.224 0.084 ;
     RECT  46.248 0.016 46.32 0.084 ;
     RECT  46.344 0.016 46.416 0.084 ;
     RECT  46.44 0.016 46.512 0.084 ;
     RECT  46.536 0.016 46.608 0.084 ;
     RECT  46.632 0.016 46.704 0.084 ;
     RECT  46.728 0.016 46.8 0.084 ;
     RECT  46.824 0.016 46.896 0.084 ;
     RECT  46.92 0.016 46.992 0.084 ;
     RECT  47.016 0.016 47.088 0.084 ;
     RECT  47.112 0.016 47.184 0.084 ;
     RECT  47.208 0.016 47.28 0.084 ;
     RECT  47.304 0.016 47.376 0.084 ;
     RECT  47.4 0.016 47.472 0.084 ;
     RECT  47.496 0.016 47.568 0.084 ;
     RECT  47.592 0.016 47.664 0.084 ;
     RECT  47.688 0.016 47.76 0.084 ;
     RECT  47.784 0.016 47.856 0.084 ;
     RECT  47.88 0.016 47.952 0.084 ;
     RECT  47.976 0.016 48.048 0.084 ;
     RECT  48.072 0.016 48.144 0.084 ;
     RECT  48.168 0.016 48.24 0.084 ;
     RECT  48.264 0.016 48.336 0.084 ;
     RECT  48.36 0.016 48.432 0.084 ;
     RECT  48.456 0.016 48.528 0.084 ;
     RECT  48.552 0.016 48.624 0.084 ;
     RECT  48.648 0.016 48.72 0.084 ;
     RECT  48.744 0.016 48.816 0.084 ;
     RECT  48.84 0.016 48.912 0.084 ;
     RECT  48.936 0.016 49.008 0.084 ;
     RECT  49.032 0.016 49.104 0.084 ;
     RECT  49.128 0.016 49.2 0.084 ;
     RECT  49.224 0.016 49.296 0.084 ;
     RECT  49.32 0.016 49.392 0.084 ;
     RECT  49.416 0.016 49.488 0.084 ;
     RECT  49.512 0.016 49.584 0.084 ;
     RECT  49.608 0.016 49.68 0.084 ;
     RECT  49.704 0.016 49.776 0.084 ;
     RECT  49.8 0.016 49.872 0.084 ;
     RECT  49.896 0.016 49.968 0.084 ;
     RECT  49.992 0.016 50.064 0.084 ;
     RECT  50.088 0.016 50.16 0.084 ;
     RECT  50.184 0.016 50.256 0.084 ;
     RECT  50.28 0.016 50.352 0.084 ;
     RECT  50.376 0.016 50.448 0.084 ;
     RECT  50.472 0.016 50.544 0.084 ;
     RECT  50.568 0.016 50.64 0.084 ;
     RECT  50.664 0.016 50.736 0.084 ;
     RECT  50.76 0.016 50.832 0.084 ;
     RECT  50.856 0.016 50.928 0.084 ;
     RECT  50.952 0.016 51.024 0.084 ;
     RECT  51.048 0.016 51.12 0.084 ;
     RECT  51.144 0.016 51.216 0.084 ;
     RECT  51.24 0.016 51.312 0.084 ;
     RECT  51.336 0.016 51.408 0.084 ;
     RECT  51.432 0.016 51.504 0.084 ;
     RECT  51.528 0.016 51.6 0.084 ;
     RECT  51.624 0.016 51.696 0.084 ;
     RECT  51.72 0.016 51.792 0.084 ;
     RECT  51.816 0.016 51.888 0.084 ;
     RECT  51.912 0.016 51.984 0.084 ;
     RECT  52.008 0.016 52.08 0.084 ;
     RECT  52.104 0.016 52.176 0.084 ;
     RECT  52.2 0.016 52.272 0.084 ;
     RECT  52.296 0.016 52.368 0.084 ;
     RECT  52.392 0.016 52.464 0.084 ;
     RECT  52.488 0.016 52.56 0.084 ;
     RECT  52.584 0.016 52.656 0.084 ;
     RECT  52.68 0.016 52.752 0.084 ;
     RECT  52.776 0.016 52.848 0.084 ;
     RECT  52.872 0.016 52.944 0.084 ;
     RECT  52.968 0.016 53.04 0.084 ;
     RECT  53.064 0.016 53.136 0.084 ;
     RECT  53.16 0.016 53.232 0.084 ;
     RECT  53.256 0.016 53.328 0.084 ;
     RECT  53.352 0.016 53.424 0.084 ;
     RECT  53.448 0.016 53.52 0.084 ;
     RECT  53.544 0.016 53.616 0.084 ;
     RECT  53.64 0.016 53.712 0.084 ;
     RECT  53.736 0.016 53.808 0.084 ;
     RECT  53.832 0.016 53.904 0.084 ;
     RECT  53.928 0.016 54 0.084 ;
     RECT  54.024 0.016 54.096 0.084 ;
     RECT  54.12 0.016 54.192 0.084 ;
     RECT  54.216 0.016 54.288 0.084 ;
     RECT  54.312 0.016 54.384 0.084 ;
     RECT  54.408 0.016 54.48 0.084 ;
     RECT  54.504 0.016 54.576 0.084 ;
     RECT  54.6 0.016 54.672 0.084 ;
     RECT  54.696 0.016 54.768 0.084 ;
     RECT  54.792 0.016 54.864 0.084 ;
     RECT  54.888 0.016 54.96 0.084 ;
     RECT  54.984 0.016 55.056 0.084 ;
     RECT  55.08 0.016 55.152 0.084 ;
     RECT  55.176 0.016 55.248 0.084 ;
     RECT  55.272 0.016 55.344 0.084 ;
     RECT  55.368 0.016 55.44 0.084 ;
     RECT  55.464 0.016 55.536 0.084 ;
     RECT  55.56 0.016 55.632 0.084 ;
     RECT  55.656 0.016 55.728 0.084 ;
     RECT  55.752 0.016 55.824 0.084 ;
     RECT  55.848 0.016 55.92 0.084 ;
     RECT  55.944 0.016 56.016 0.084 ;
     RECT  56.04 0.016 56.112 0.084 ;
     RECT  56.136 0.016 56.208 0.084 ;
     RECT  56.232 0.016 56.304 0.084 ;
     RECT  56.328 0.016 56.4 0.084 ;
     RECT  56.424 0.016 56.496 0.084 ;
     RECT  56.52 0.016 56.592 0.084 ;
     RECT  56.616 0.016 56.688 0.084 ;
     RECT  56.712 0.016 56.784 0.084 ;
     RECT  56.808 0.016 56.88 0.084 ;
     RECT  56.904 0.016 56.976 0.084 ;
     RECT  57 0.016 57.072 0.084 ;
     RECT  57.096 0.016 57.168 0.084 ;
     RECT  57.192 0.016 57.264 0.084 ;
     RECT  57.288 0.016 57.36 0.084 ;
     RECT  57.384 0.016 57.456 0.084 ;
     RECT  57.48 0.016 58.32 0.084 ;
     RECT  58.344 0.016 58.416 0.084 ;
     RECT  58.44 0.016 58.512 0.084 ;
     RECT  58.536 0.016 58.608 0.084 ;
     RECT  58.632 0.016 58.704 0.084 ;
     RECT  58.728 0.016 58.8 0.084 ;
     RECT  58.824 0.016 58.896 0.084 ;
     RECT  58.92 0.016 58.992 0.084 ;
     RECT  59.016 0.016 59.088 0.084 ;
     RECT  59.112 0.016 59.184 0.084 ;
     RECT  59.208 0.016 59.28 0.084 ;
     RECT  59.304 0.016 59.376 0.084 ;
     RECT  59.4 0.016 59.472 0.084 ;
     RECT  59.496 0.016 59.568 0.084 ;
     RECT  59.592 0.016 59.664 0.084 ;
     RECT  59.688 0.016 59.76 0.084 ;
     RECT  59.784 0.016 59.856 0.084 ;
     RECT  59.88 0.016 59.952 0.084 ;
     RECT  59.976 0.016 60.048 0.084 ;
     RECT  60.072 0.016 60.144 0.084 ;
     RECT  60.168 0.016 60.24 0.084 ;
     RECT  60.264 0.016 60.336 0.084 ;
     RECT  60.36 0.016 60.432 0.084 ;
     RECT  60.456 0.016 60.528 0.084 ;
     RECT  60.552 0.016 60.624 0.084 ;
     RECT  60.648 0.016 60.72 0.084 ;
     RECT  60.744 0.016 60.816 0.084 ;
     RECT  60.84 0.016 60.912 0.084 ;
     RECT  60.936 0.016 61.008 0.084 ;
     RECT  61.032 0.016 61.104 0.084 ;
     RECT  61.128 0.016 61.2 0.084 ;
     RECT  61.224 0.016 61.296 0.084 ;
     RECT  61.32 0.016 61.392 0.084 ;
     RECT  61.416 0.016 61.488 0.084 ;
     RECT  61.512 0.016 61.584 0.084 ;
     RECT  61.608 0.016 61.68 0.084 ;
     RECT  61.704 0.016 61.776 0.084 ;
     RECT  61.8 0.016 61.872 0.084 ;
     RECT  61.896 0.016 61.968 0.084 ;
     RECT  61.992 0.016 62.064 0.084 ;
     RECT  62.088 0.016 62.16 0.084 ;
     RECT  62.184 0.016 62.256 0.084 ;
     RECT  62.28 0.016 62.352 0.084 ;
     RECT  62.376 0.016 62.448 0.084 ;
     RECT  62.472 0.016 62.544 0.084 ;
     RECT  62.568 0.016 62.64 0.084 ;
     RECT  62.664 0.016 62.736 0.084 ;
     RECT  62.76 0.016 62.832 0.084 ;
     RECT  0.72 0.084 62.856 2.915 ;
     RECT  0.816 2.915 62.856 2.963 ;
     RECT  0.912 2.963 62.856 3.011 ;
     RECT  1.008 3.011 62.856 3.539 ;
     RECT  1.008 3.539 54.792 3.587 ;
     RECT  1.008 3.587 40.92 3.731 ;
     RECT  42.096 3.587 54.792 3.731 ;
     RECT  1.008 3.731 30.984 3.779 ;
     RECT  23.136 3.779 27.864 3.923 ;
     RECT  56.208 3.539 62.856 3.923 ;
     RECT  1.008 3.779 21.912 4.019 ;
     RECT  23.136 3.923 27.768 4.019 ;
     RECT  28.944 3.779 30.984 4.019 ;
     RECT  32.1 3.731 40.512 4.019 ;
     RECT  42.768 3.731 54.792 4.019 ;
     RECT  56.4 3.923 62.856 4.019 ;
     RECT  1.2 4.019 2.712 4.067 ;
     RECT  3.696 4.019 21.912 4.067 ;
     RECT  48.3 4.019 54.792 4.067 ;
     RECT  1.296 4.067 2.712 4.115 ;
     RECT  34.32 4.019 40.512 4.115 ;
     RECT  3.792 4.067 21.912 4.163 ;
     RECT  29.04 4.019 30.984 4.355 ;
     RECT  1.392 4.115 2.712 4.451 ;
     RECT  60.768 4.019 62.856 4.595 ;
     RECT  1.392 4.451 1.416 4.787 ;
     RECT  60.768 4.595 62.472 5.075 ;
     RECT  29.4 4.355 30.984 5.077 ;
     RECT  23.136 4.019 25.032 5.123 ;
     RECT  44.832 4.019 46.536 5.123 ;
     RECT  56.4 4.019 59.412 5.507 ;
     RECT  26.592 4.019 27.72 5.555 ;
     RECT  61.8 5.075 62.472 5.747 ;
     RECT  34.8 4.115 40.512 6.419 ;
     RECT  34.8 6.419 39.192 6.611 ;
     RECT  34.8 6.611 39.048 7.139 ;
     RECT  34.8 7.139 38.616 7.715 ;
     RECT  34.8 7.715 38.52 8.243 ;
     RECT  4.416 4.163 21.912 8.819 ;
     RECT  32.1 4.019 33.336 8.819 ;
     RECT  5.1 8.819 21.912 9.011 ;
     RECT  10.032 9.011 21.912 9.395 ;
     RECT  10.032 9.395 14.52 9.539 ;
     RECT  56.4 5.507 56.712 9.925 ;
     RECT  57.84 5.507 59.412 9.925 ;
     RECT  5.1 9.011 8.76 10.067 ;
     RECT  53.7 4.067 54.792 10.165 ;
     RECT  56.4 9.925 59.412 10.165 ;
     RECT  7.2 10.067 8.76 10.643 ;
     RECT  10.5 9.539 14.52 11.171 ;
     RECT  29.4 5.077 31.08 11.171 ;
     RECT  2.4 4.451 2.712 11.221 ;
     RECT  42.9 4.019 43.8 11.459 ;
     RECT  23.28 5.123 25.032 11.699 ;
     RECT  7.2 10.643 8.112 11.747 ;
     RECT  53.7 10.165 59.412 11.749 ;
     RECT  48.3 4.067 52.44 11.941 ;
     RECT  61.8 5.747 62.112 11.989 ;
     RECT  40.2 6.419 40.512 12.229 ;
     RECT  23.28 11.699 24.312 12.275 ;
     RECT  5.1 10.067 5.976 12.277 ;
     RECT  4.992 12.277 5.976 12.469 ;
     RECT  10.5 11.171 14.136 12.469 ;
     RECT  15.9 9.395 21.912 12.469 ;
     RECT  26.7 5.555 27.72 12.469 ;
     RECT  29.4 11.171 29.712 12.469 ;
     RECT  2.4 11.221 2.856 12.515 ;
     RECT  40.2 12.229 40.632 12.517 ;
     RECT  0.144 11.173 0.168 12.611 ;
     RECT  3.936 12.517 3.96 12.757 ;
     RECT  31.056 11.171 31.08 12.757 ;
     RECT  32.1 8.819 32.412 12.757 ;
     RECT  10.5 12.469 21.912 12.851 ;
     RECT  24 12.275 24.312 12.901 ;
     RECT  34.8 8.243 38.472 12.997 ;
     RECT  10.5 12.851 21.612 13.093 ;
     RECT  3.888 12.757 3.96 13.141 ;
     RECT  9.792 13.093 21.612 13.235 ;
     RECT  26.7 12.469 29.712 13.477 ;
     RECT  31.056 12.757 32.412 13.477 ;
     RECT  40.2 12.517 41.592 13.477 ;
     RECT  42.9 11.459 43.212 13.477 ;
     RECT  40.2 13.477 43.8 13.525 ;
     RECT  44.976 5.123 46.536 13.525 ;
     RECT  4.992 12.469 6.216 13.621 ;
     RECT  7.584 11.747 8.112 13.621 ;
     RECT  22.944 13.477 22.968 13.621 ;
     RECT  24 12.901 24.408 13.621 ;
     RECT  34.8 12.997 38.616 13.621 ;
     RECT  22.944 13.621 24.408 13.669 ;
     RECT  34.8 13.621 39.144 13.909 ;
     RECT  40.2 13.525 46.536 13.909 ;
     RECT  34.8 13.909 46.536 14.053 ;
     RECT  53.568 11.749 59.412 14.053 ;
     RECT  60.768 5.075 60.792 14.053 ;
     RECT  3.888 13.141 4.008 14.197 ;
     RECT  4.992 13.621 8.112 14.197 ;
     RECT  12.24 13.235 21.612 14.197 ;
     RECT  22.656 13.669 24.408 14.197 ;
     RECT  26.7 13.477 32.412 14.245 ;
     RECT  33.408 13.093 33.432 14.245 ;
     RECT  48.3 11.941 52.488 14.245 ;
     RECT  53.568 14.053 60.792 14.245 ;
     RECT  61.8 11.989 63 14.245 ;
     RECT  2.4 12.515 2.712 14.533 ;
     RECT  3.888 14.197 8.112 14.533 ;
     RECT  34.8 14.053 46.968 14.533 ;
     RECT  9.792 13.235 11.256 14.629 ;
     RECT  12.24 14.197 24.408 14.677 ;
     RECT  2.4 14.533 8.112 14.773 ;
     RECT  9.12 14.629 11.256 14.773 ;
     RECT  26.7 14.245 33.432 14.773 ;
     RECT  34.56 14.533 46.968 14.773 ;
     RECT  2.4 14.773 11.256 14.821 ;
     RECT  12.24 14.677 24.792 14.821 ;
     RECT  2.4 14.821 24.792 15.445 ;
     RECT  2.4 15.445 25.032 15.827 ;
     RECT  26.7 14.773 46.968 15.925 ;
     RECT  48.3 14.245 63 15.973 ;
     RECT  26.7 15.925 47.16 16.357 ;
     RECT  48.3 15.973 63.048 16.357 ;
     RECT  26.7 16.357 63.048 16.405 ;
     RECT  25.872 16.405 63.048 16.549 ;
     RECT  25.872 16.549 63.096 16.645 ;
     RECT  2.4 15.827 24.792 16.837 ;
     RECT  25.872 16.645 63.192 16.837 ;
     RECT  2.4 16.837 63.192 18.181 ;
     RECT  2.4 18.181 63.624 18.757 ;
     RECT  2.304 18.757 63.624 18.949 ;
     RECT  2.16 18.949 63.624 20.053 ;
     RECT  1.968 20.053 63.624 20.293 ;
     RECT  1.872 20.293 63.624 21.061 ;
     RECT  1.872 21.061 64.008 21.155 ;
     RECT  1.872 21.155 6.312 21.637 ;
     RECT  1.776 21.637 6.312 22.165 ;
     RECT  7.536 21.155 64.008 22.165 ;
     RECT  1.776 22.165 64.008 23.676 ;
     RECT  1.8 23.676 1.872 23.696 ;
     RECT  1.896 23.676 1.968 23.696 ;
     RECT  1.992 23.676 2.064 23.696 ;
     RECT  2.088 23.676 2.16 23.696 ;
     RECT  2.184 23.676 2.256 23.696 ;
     RECT  2.28 23.676 2.352 23.696 ;
     RECT  2.376 23.676 2.448 23.696 ;
     RECT  2.472 23.676 2.544 23.696 ;
     RECT  2.568 23.676 2.64 23.696 ;
     RECT  2.664 23.676 2.736 23.696 ;
     RECT  2.76 23.676 2.832 23.696 ;
     RECT  2.856 23.676 2.928 23.696 ;
     RECT  2.952 23.676 3.024 23.696 ;
     RECT  3.048 23.676 3.12 23.696 ;
     RECT  3.144 23.676 3.216 23.696 ;
     RECT  3.24 23.676 3.312 23.696 ;
     RECT  3.336 23.676 3.408 23.696 ;
     RECT  3.432 23.676 3.504 23.696 ;
     RECT  3.528 23.676 3.6 23.696 ;
     RECT  3.624 23.676 3.696 23.696 ;
     RECT  3.72 23.676 3.792 23.696 ;
     RECT  3.816 23.676 3.888 23.696 ;
     RECT  3.912 23.676 3.984 23.696 ;
     RECT  4.008 23.676 4.08 23.696 ;
     RECT  4.104 23.676 4.176 23.696 ;
     RECT  4.2 23.676 4.272 23.696 ;
     RECT  4.296 23.676 4.368 23.696 ;
     RECT  4.392 23.676 4.464 23.696 ;
     RECT  4.488 23.676 4.56 23.696 ;
     RECT  4.584 23.676 4.656 23.696 ;
     RECT  4.68 23.676 4.752 23.696 ;
     RECT  4.776 23.676 4.848 23.696 ;
     RECT  4.872 23.676 4.944 23.696 ;
     RECT  4.968 23.676 5.04 23.696 ;
     RECT  5.064 23.676 5.136 23.696 ;
     RECT  5.16 23.676 5.232 23.696 ;
     RECT  5.256 23.676 5.328 23.696 ;
     RECT  5.352 23.676 5.424 23.696 ;
     RECT  5.448 23.676 5.52 23.696 ;
     RECT  5.544 23.676 5.616 23.696 ;
     RECT  5.64 23.676 5.712 23.696 ;
     RECT  5.736 23.676 5.808 23.696 ;
     RECT  5.832 23.676 5.904 23.696 ;
     RECT  5.928 23.676 6 23.696 ;
     RECT  6.024 23.676 6.096 23.696 ;
     RECT  6.12 23.676 6.192 23.696 ;
     RECT  6.216 23.676 6.288 23.696 ;
     RECT  6.312 23.676 6.384 23.696 ;
     RECT  6.408 23.676 7.248 23.696 ;
     RECT  7.272 23.676 7.344 23.696 ;
     RECT  7.368 23.676 7.44 23.696 ;
     RECT  7.464 23.676 7.536 23.696 ;
     RECT  7.56 23.676 7.632 23.696 ;
     RECT  7.656 23.676 7.728 23.696 ;
     RECT  7.752 23.676 7.824 23.696 ;
     RECT  7.848 23.676 7.92 23.696 ;
     RECT  7.944 23.676 8.016 23.696 ;
     RECT  8.04 23.676 8.112 23.696 ;
     RECT  8.136 23.676 8.208 23.696 ;
     RECT  8.232 23.676 8.304 23.696 ;
     RECT  8.328 23.676 8.4 23.696 ;
     RECT  8.424 23.676 8.496 23.696 ;
     RECT  8.52 23.676 8.592 23.696 ;
     RECT  8.616 23.676 8.688 23.696 ;
     RECT  8.712 23.676 8.784 23.696 ;
     RECT  8.808 23.676 8.88 23.696 ;
     RECT  8.904 23.676 8.976 23.696 ;
     RECT  9 23.676 9.072 23.696 ;
     RECT  9.096 23.676 9.168 23.696 ;
     RECT  9.192 23.676 9.264 23.696 ;
     RECT  9.288 23.676 9.36 23.696 ;
     RECT  9.384 23.676 9.456 23.696 ;
     RECT  9.48 23.676 9.552 23.696 ;
     RECT  9.576 23.676 9.648 23.696 ;
     RECT  9.672 23.676 9.744 23.696 ;
     RECT  9.768 23.676 9.84 23.696 ;
     RECT  9.864 23.676 9.936 23.696 ;
     RECT  9.96 23.676 10.032 23.696 ;
     RECT  10.056 23.676 10.128 23.696 ;
     RECT  10.152 23.676 10.224 23.696 ;
     RECT  10.248 23.676 10.32 23.696 ;
     RECT  10.344 23.676 10.416 23.696 ;
     RECT  10.44 23.676 10.512 23.696 ;
     RECT  10.536 23.676 10.608 23.696 ;
     RECT  10.632 23.676 10.704 23.696 ;
     RECT  10.728 23.676 10.8 23.696 ;
     RECT  10.824 23.676 10.896 23.696 ;
     RECT  10.92 23.676 10.992 23.696 ;
     RECT  11.016 23.676 11.088 23.696 ;
     RECT  11.112 23.676 11.184 23.696 ;
     RECT  11.208 23.676 11.28 23.696 ;
     RECT  11.304 23.676 11.376 23.696 ;
     RECT  11.4 23.676 11.472 23.696 ;
     RECT  11.496 23.676 11.568 23.696 ;
     RECT  11.592 23.676 11.664 23.696 ;
     RECT  11.688 23.676 11.76 23.696 ;
     RECT  11.784 23.676 11.856 23.696 ;
     RECT  11.88 23.676 11.952 23.696 ;
     RECT  11.976 23.676 12.048 23.696 ;
     RECT  12.072 23.676 12.144 23.696 ;
     RECT  12.168 23.676 12.24 23.696 ;
     RECT  12.264 23.676 12.336 23.696 ;
     RECT  12.36 23.676 12.432 23.696 ;
     RECT  12.456 23.676 12.528 23.696 ;
     RECT  12.552 23.676 12.624 23.696 ;
     RECT  12.648 23.676 12.72 23.696 ;
     RECT  12.744 23.676 12.816 23.696 ;
     RECT  12.84 23.676 12.912 23.696 ;
     RECT  12.936 23.676 13.008 23.696 ;
     RECT  13.032 23.676 13.104 23.696 ;
     RECT  13.128 23.676 13.2 23.696 ;
     RECT  13.224 23.676 13.296 23.696 ;
     RECT  13.32 23.676 13.392 23.696 ;
     RECT  13.416 23.676 13.488 23.696 ;
     RECT  13.512 23.676 13.584 23.696 ;
     RECT  13.608 23.676 13.68 23.696 ;
     RECT  13.704 23.676 13.776 23.696 ;
     RECT  13.8 23.676 13.872 23.696 ;
     RECT  13.896 23.676 13.968 23.696 ;
     RECT  13.992 23.676 14.064 23.696 ;
     RECT  14.088 23.676 14.16 23.696 ;
     RECT  14.184 23.676 14.256 23.696 ;
     RECT  14.28 23.676 14.352 23.696 ;
     RECT  14.376 23.676 14.448 23.696 ;
     RECT  14.472 23.676 14.544 23.696 ;
     RECT  14.568 23.676 14.64 23.696 ;
     RECT  14.664 23.676 14.736 23.696 ;
     RECT  14.76 23.676 14.832 23.696 ;
     RECT  14.856 23.676 14.928 23.696 ;
     RECT  14.952 23.676 15.024 23.696 ;
     RECT  15.048 23.676 15.12 23.696 ;
     RECT  15.144 23.676 15.216 23.696 ;
     RECT  15.24 23.676 15.312 23.696 ;
     RECT  15.336 23.676 15.408 23.696 ;
     RECT  15.432 23.676 15.504 23.696 ;
     RECT  15.528 23.676 15.6 23.696 ;
     RECT  15.624 23.676 15.696 23.696 ;
     RECT  15.72 23.676 15.792 23.696 ;
     RECT  15.816 23.676 15.888 23.696 ;
     RECT  15.912 23.676 15.984 23.696 ;
     RECT  16.008 23.676 16.08 23.696 ;
     RECT  16.104 23.676 16.176 23.696 ;
     RECT  16.2 23.676 16.272 23.696 ;
     RECT  16.296 23.676 16.368 23.696 ;
     RECT  16.392 23.676 16.464 23.696 ;
     RECT  16.488 23.676 16.56 23.696 ;
     RECT  16.584 23.676 16.656 23.696 ;
     RECT  16.68 23.676 16.752 23.696 ;
     RECT  16.776 23.676 16.848 23.696 ;
     RECT  16.872 23.676 16.944 23.696 ;
     RECT  16.968 23.676 17.04 23.696 ;
     RECT  17.064 23.676 17.136 23.696 ;
     RECT  17.16 23.676 17.232 23.696 ;
     RECT  17.256 23.676 17.328 23.696 ;
     RECT  17.352 23.676 17.424 23.696 ;
     RECT  17.448 23.676 17.52 23.696 ;
     RECT  17.544 23.676 17.616 23.696 ;
     RECT  17.64 23.676 17.712 23.696 ;
     RECT  17.736 23.676 17.808 23.696 ;
     RECT  17.832 23.676 17.904 23.696 ;
     RECT  17.928 23.676 18 23.696 ;
     RECT  18.024 23.676 18.096 23.696 ;
     RECT  18.12 23.676 18.192 23.696 ;
     RECT  18.216 23.676 18.288 23.696 ;
     RECT  18.312 23.676 18.384 23.696 ;
     RECT  18.408 23.676 18.48 23.696 ;
     RECT  18.504 23.676 18.576 23.696 ;
     RECT  18.6 23.676 18.672 23.696 ;
     RECT  18.696 23.676 18.768 23.696 ;
     RECT  18.792 23.676 18.864 23.696 ;
     RECT  18.888 23.676 18.96 23.696 ;
     RECT  18.984 23.676 19.056 23.696 ;
     RECT  19.08 23.676 19.152 23.696 ;
     RECT  19.176 23.676 19.248 23.696 ;
     RECT  19.272 23.676 19.344 23.696 ;
     RECT  19.368 23.676 19.44 23.696 ;
     RECT  19.464 23.676 19.536 23.696 ;
     RECT  19.56 23.676 19.632 23.696 ;
     RECT  19.656 23.676 19.728 23.696 ;
     RECT  19.752 23.676 19.824 23.696 ;
     RECT  19.848 23.676 19.92 23.696 ;
     RECT  19.944 23.676 20.016 23.696 ;
     RECT  20.04 23.676 20.112 23.696 ;
     RECT  20.136 23.676 20.208 23.696 ;
     RECT  20.232 23.676 20.304 23.696 ;
     RECT  20.328 23.676 20.4 23.696 ;
     RECT  20.424 23.676 20.496 23.696 ;
     RECT  20.52 23.676 20.592 23.696 ;
     RECT  20.616 23.676 20.688 23.696 ;
     RECT  20.712 23.676 20.784 23.696 ;
     RECT  20.808 23.676 20.88 23.696 ;
     RECT  20.904 23.676 20.976 23.696 ;
     RECT  21 23.676 21.072 23.696 ;
     RECT  21.096 23.676 21.168 23.696 ;
     RECT  21.192 23.676 21.264 23.696 ;
     RECT  21.288 23.676 21.36 23.696 ;
     RECT  21.384 23.676 21.456 23.696 ;
     RECT  21.48 23.676 21.552 23.696 ;
     RECT  21.576 23.676 21.648 23.696 ;
     RECT  21.672 23.676 21.744 23.696 ;
     RECT  21.768 23.676 21.84 23.696 ;
     RECT  21.864 23.676 21.936 23.696 ;
     RECT  21.96 23.676 22.032 23.696 ;
     RECT  22.056 23.676 22.128 23.696 ;
     RECT  22.152 23.676 22.224 23.696 ;
     RECT  22.248 23.676 22.32 23.696 ;
     RECT  22.344 23.676 22.416 23.696 ;
     RECT  22.44 23.676 22.512 23.696 ;
     RECT  22.536 23.676 22.608 23.696 ;
     RECT  22.632 23.676 22.704 23.696 ;
     RECT  22.728 23.676 22.8 23.696 ;
     RECT  22.824 23.676 22.896 23.696 ;
     RECT  22.92 23.676 22.992 23.696 ;
     RECT  23.016 23.676 23.088 23.696 ;
     RECT  23.112 23.676 23.184 23.696 ;
     RECT  23.208 23.676 23.28 23.696 ;
     RECT  23.304 23.676 23.376 23.696 ;
     RECT  23.4 23.676 23.472 23.696 ;
     RECT  23.496 23.676 23.568 23.696 ;
     RECT  23.592 23.676 23.664 23.696 ;
     RECT  23.688 23.676 23.76 23.696 ;
     RECT  23.784 23.676 23.856 23.696 ;
     RECT  23.88 23.676 23.952 23.696 ;
     RECT  23.976 23.676 24.048 23.696 ;
     RECT  24.072 23.676 24.144 23.696 ;
     RECT  24.168 23.676 24.24 23.696 ;
     RECT  24.264 23.676 24.336 23.696 ;
     RECT  24.36 23.676 24.432 23.696 ;
     RECT  24.456 23.676 24.528 23.696 ;
     RECT  24.552 23.676 24.624 23.696 ;
     RECT  24.648 23.676 24.72 23.696 ;
     RECT  24.744 23.676 24.816 23.696 ;
     RECT  24.84 23.676 24.912 23.696 ;
     RECT  24.936 23.676 25.008 23.696 ;
     RECT  25.032 23.676 25.104 23.696 ;
     RECT  25.128 23.676 25.2 23.696 ;
     RECT  25.224 23.676 25.296 23.696 ;
     RECT  25.32 23.676 25.392 23.696 ;
     RECT  25.416 23.676 25.488 23.696 ;
     RECT  25.512 23.676 25.584 23.696 ;
     RECT  25.608 23.676 26.448 23.696 ;
     RECT  26.472 23.676 26.544 23.696 ;
     RECT  26.568 23.676 26.64 23.696 ;
     RECT  26.664 23.676 26.736 23.696 ;
     RECT  26.76 23.676 26.832 23.696 ;
     RECT  26.856 23.676 26.928 23.696 ;
     RECT  26.952 23.676 27.024 23.696 ;
     RECT  27.048 23.676 27.12 23.696 ;
     RECT  27.144 23.676 27.216 23.696 ;
     RECT  27.24 23.676 27.312 23.696 ;
     RECT  27.336 23.676 27.408 23.696 ;
     RECT  27.432 23.676 27.504 23.696 ;
     RECT  27.528 23.676 27.6 23.696 ;
     RECT  27.624 23.676 27.696 23.696 ;
     RECT  27.72 23.676 27.792 23.696 ;
     RECT  27.816 23.676 27.888 23.696 ;
     RECT  27.912 23.676 27.984 23.696 ;
     RECT  28.008 23.676 28.08 23.696 ;
     RECT  28.104 23.676 28.176 23.696 ;
     RECT  28.2 23.676 28.272 23.696 ;
     RECT  28.296 23.676 28.368 23.696 ;
     RECT  28.392 23.676 28.464 23.696 ;
     RECT  28.488 23.676 28.56 23.696 ;
     RECT  28.584 23.676 28.656 23.696 ;
     RECT  28.68 23.676 28.752 23.696 ;
     RECT  28.776 23.676 28.848 23.696 ;
     RECT  28.872 23.676 28.944 23.696 ;
     RECT  28.968 23.676 29.04 23.696 ;
     RECT  29.064 23.676 29.136 23.696 ;
     RECT  29.16 23.676 29.232 23.696 ;
     RECT  29.256 23.676 29.328 23.696 ;
     RECT  29.352 23.676 29.424 23.696 ;
     RECT  29.448 23.676 29.52 23.696 ;
     RECT  29.544 23.676 29.616 23.696 ;
     RECT  29.64 23.676 29.712 23.696 ;
     RECT  29.736 23.676 29.808 23.696 ;
     RECT  29.832 23.676 29.904 23.696 ;
     RECT  29.928 23.676 30 23.696 ;
     RECT  30.024 23.676 30.096 23.696 ;
     RECT  30.12 23.676 30.192 23.696 ;
     RECT  30.216 23.676 30.288 23.696 ;
     RECT  30.312 23.676 30.384 23.696 ;
     RECT  30.408 23.676 30.48 23.696 ;
     RECT  30.504 23.676 30.576 23.696 ;
     RECT  30.6 23.676 30.672 23.696 ;
     RECT  30.696 23.676 30.768 23.696 ;
     RECT  30.792 23.676 30.864 23.696 ;
     RECT  30.888 23.676 30.96 23.696 ;
     RECT  30.984 23.676 31.056 23.696 ;
     RECT  31.08 23.676 31.152 23.696 ;
     RECT  31.176 23.676 31.248 23.696 ;
     RECT  31.272 23.676 31.344 23.696 ;
     RECT  31.368 23.676 31.44 23.696 ;
     RECT  31.464 23.676 31.536 23.696 ;
     RECT  31.56 23.676 31.632 23.696 ;
     RECT  31.656 23.676 31.728 23.696 ;
     RECT  31.752 23.676 31.824 23.696 ;
     RECT  31.848 23.676 31.92 23.696 ;
     RECT  31.944 23.676 32.016 23.696 ;
     RECT  32.04 23.676 32.112 23.696 ;
     RECT  32.136 23.676 32.208 23.696 ;
     RECT  32.232 23.676 32.304 23.696 ;
     RECT  32.328 23.676 32.4 23.696 ;
     RECT  32.424 23.676 32.496 23.696 ;
     RECT  32.52 23.676 32.592 23.696 ;
     RECT  32.616 23.676 32.688 23.696 ;
     RECT  32.712 23.676 32.784 23.696 ;
     RECT  32.808 23.676 32.88 23.696 ;
     RECT  32.904 23.676 32.976 23.696 ;
     RECT  33 23.676 33.072 23.696 ;
     RECT  33.096 23.676 33.168 23.696 ;
     RECT  33.192 23.676 33.264 23.696 ;
     RECT  33.288 23.676 33.36 23.696 ;
     RECT  33.384 23.676 33.456 23.696 ;
     RECT  33.48 23.676 33.552 23.696 ;
     RECT  33.576 23.676 33.648 23.696 ;
     RECT  33.672 23.676 33.744 23.696 ;
     RECT  33.768 23.676 33.84 23.696 ;
     RECT  33.864 23.676 33.936 23.696 ;
     RECT  33.96 23.676 34.032 23.696 ;
     RECT  34.056 23.676 34.128 23.696 ;
     RECT  34.152 23.676 34.224 23.696 ;
     RECT  34.248 23.676 34.32 23.696 ;
     RECT  34.344 23.676 34.416 23.696 ;
     RECT  34.44 23.676 34.512 23.696 ;
     RECT  34.536 23.676 34.608 23.696 ;
     RECT  34.632 23.676 34.704 23.696 ;
     RECT  34.728 23.676 34.8 23.696 ;
     RECT  34.824 23.676 34.896 23.696 ;
     RECT  34.92 23.676 34.992 23.696 ;
     RECT  35.016 23.676 35.088 23.696 ;
     RECT  35.112 23.676 35.184 23.696 ;
     RECT  35.208 23.676 35.28 23.696 ;
     RECT  35.304 23.676 35.376 23.696 ;
     RECT  35.4 23.676 35.472 23.696 ;
     RECT  35.496 23.676 35.568 23.696 ;
     RECT  35.592 23.676 35.664 23.696 ;
     RECT  35.688 23.676 35.76 23.696 ;
     RECT  35.784 23.676 35.856 23.696 ;
     RECT  35.88 23.676 35.952 23.696 ;
     RECT  35.976 23.676 36.048 23.696 ;
     RECT  36.072 23.676 36.144 23.696 ;
     RECT  36.168 23.676 36.24 23.696 ;
     RECT  36.264 23.676 36.336 23.696 ;
     RECT  36.36 23.676 36.432 23.696 ;
     RECT  36.456 23.676 36.528 23.696 ;
     RECT  36.552 23.676 36.624 23.696 ;
     RECT  36.648 23.676 36.72 23.696 ;
     RECT  36.744 23.676 36.816 23.696 ;
     RECT  36.84 23.676 36.912 23.696 ;
     RECT  36.936 23.676 37.008 23.696 ;
     RECT  37.032 23.676 37.104 23.696 ;
     RECT  37.128 23.676 37.2 23.696 ;
     RECT  37.224 23.676 37.296 23.696 ;
     RECT  37.32 23.676 37.392 23.696 ;
     RECT  37.416 23.676 37.488 23.696 ;
     RECT  37.512 23.676 37.584 23.696 ;
     RECT  37.608 23.676 37.68 23.696 ;
     RECT  37.704 23.676 37.776 23.696 ;
     RECT  37.8 23.676 37.872 23.696 ;
     RECT  37.896 23.676 37.968 23.696 ;
     RECT  37.992 23.676 38.064 23.696 ;
     RECT  38.088 23.676 38.16 23.696 ;
     RECT  38.184 23.676 38.256 23.696 ;
     RECT  38.28 23.676 38.352 23.696 ;
     RECT  38.376 23.676 38.448 23.696 ;
     RECT  38.472 23.676 38.544 23.696 ;
     RECT  38.568 23.676 38.64 23.696 ;
     RECT  38.664 23.676 38.736 23.696 ;
     RECT  38.76 23.676 38.832 23.696 ;
     RECT  38.856 23.676 38.928 23.696 ;
     RECT  38.952 23.676 39.024 23.696 ;
     RECT  39.048 23.676 39.12 23.696 ;
     RECT  39.144 23.676 39.216 23.696 ;
     RECT  39.24 23.676 39.312 23.696 ;
     RECT  39.336 23.676 39.408 23.696 ;
     RECT  39.432 23.676 39.504 23.696 ;
     RECT  39.528 23.676 39.6 23.696 ;
     RECT  39.624 23.676 39.696 23.696 ;
     RECT  39.72 23.676 39.792 23.696 ;
     RECT  39.816 23.676 39.888 23.696 ;
     RECT  39.912 23.676 39.984 23.696 ;
     RECT  40.008 23.676 40.08 23.696 ;
     RECT  40.104 23.676 40.176 23.696 ;
     RECT  40.2 23.676 40.272 23.696 ;
     RECT  40.296 23.676 40.368 23.696 ;
     RECT  40.392 23.676 40.464 23.696 ;
     RECT  40.488 23.676 40.56 23.696 ;
     RECT  40.584 23.676 40.656 23.696 ;
     RECT  40.68 23.676 40.752 23.696 ;
     RECT  40.776 23.676 40.848 23.696 ;
     RECT  40.872 23.676 40.944 23.696 ;
     RECT  40.968 23.676 41.04 23.696 ;
     RECT  41.064 23.676 41.136 23.696 ;
     RECT  41.16 23.676 41.232 23.696 ;
     RECT  41.256 23.676 41.328 23.696 ;
     RECT  41.352 23.676 41.424 23.696 ;
     RECT  41.448 23.676 41.52 23.696 ;
     RECT  41.544 23.676 41.616 23.696 ;
     RECT  41.64 23.676 41.712 23.696 ;
     RECT  41.736 23.676 41.808 23.696 ;
     RECT  41.832 23.676 41.904 23.696 ;
     RECT  41.928 23.676 42 23.696 ;
     RECT  42.024 23.676 42.096 23.696 ;
     RECT  42.12 23.676 42.192 23.696 ;
     RECT  42.216 23.676 42.288 23.696 ;
     RECT  42.312 23.676 42.384 23.696 ;
     RECT  42.408 23.676 42.48 23.696 ;
     RECT  42.504 23.676 42.576 23.696 ;
     RECT  42.6 23.676 42.672 23.696 ;
     RECT  42.696 23.676 42.768 23.696 ;
     RECT  42.792 23.676 42.864 23.696 ;
     RECT  42.888 23.676 42.96 23.696 ;
     RECT  42.984 23.676 43.056 23.696 ;
     RECT  43.08 23.676 43.152 23.696 ;
     RECT  43.176 23.676 43.248 23.696 ;
     RECT  43.272 23.676 43.344 23.696 ;
     RECT  43.368 23.676 43.44 23.696 ;
     RECT  43.464 23.676 43.536 23.696 ;
     RECT  43.56 23.676 43.632 23.696 ;
     RECT  43.656 23.676 43.728 23.696 ;
     RECT  43.752 23.676 43.824 23.696 ;
     RECT  43.848 23.676 43.92 23.696 ;
     RECT  43.944 23.676 44.016 23.696 ;
     RECT  44.04 23.676 44.112 23.696 ;
     RECT  44.136 23.676 44.208 23.696 ;
     RECT  44.232 23.676 44.304 23.696 ;
     RECT  44.328 23.676 44.4 23.696 ;
     RECT  44.424 23.676 44.496 23.696 ;
     RECT  44.52 23.676 44.592 23.696 ;
     RECT  44.616 23.676 44.688 23.696 ;
     RECT  44.712 23.676 44.784 23.696 ;
     RECT  44.808 23.676 45.648 23.696 ;
     RECT  45.672 23.676 45.744 23.696 ;
     RECT  45.768 23.676 45.84 23.696 ;
     RECT  45.864 23.676 45.936 23.696 ;
     RECT  45.96 23.676 46.032 23.696 ;
     RECT  46.056 23.676 46.128 23.696 ;
     RECT  46.152 23.676 46.224 23.696 ;
     RECT  46.248 23.676 46.32 23.696 ;
     RECT  46.344 23.676 46.416 23.696 ;
     RECT  46.44 23.676 46.512 23.696 ;
     RECT  46.536 23.676 46.608 23.696 ;
     RECT  46.632 23.676 46.704 23.696 ;
     RECT  46.728 23.676 46.8 23.696 ;
     RECT  46.824 23.676 46.896 23.696 ;
     RECT  46.92 23.676 46.992 23.696 ;
     RECT  47.016 23.676 47.088 23.696 ;
     RECT  47.112 23.676 47.184 23.696 ;
     RECT  47.208 23.676 47.28 23.696 ;
     RECT  47.304 23.676 47.376 23.696 ;
     RECT  47.4 23.676 47.472 23.696 ;
     RECT  47.496 23.676 47.568 23.696 ;
     RECT  47.592 23.676 47.664 23.696 ;
     RECT  47.688 23.676 47.76 23.696 ;
     RECT  47.784 23.676 47.856 23.696 ;
     RECT  47.88 23.676 47.952 23.696 ;
     RECT  47.976 23.676 48.048 23.696 ;
     RECT  48.072 23.676 48.144 23.696 ;
     RECT  48.168 23.676 48.24 23.696 ;
     RECT  48.264 23.676 48.336 23.696 ;
     RECT  48.36 23.676 48.432 23.696 ;
     RECT  48.456 23.676 48.528 23.696 ;
     RECT  48.552 23.676 48.624 23.696 ;
     RECT  48.648 23.676 48.72 23.696 ;
     RECT  48.744 23.676 48.816 23.696 ;
     RECT  48.84 23.676 48.912 23.696 ;
     RECT  48.936 23.676 49.008 23.696 ;
     RECT  49.032 23.676 49.104 23.696 ;
     RECT  49.128 23.676 49.2 23.696 ;
     RECT  49.224 23.676 49.296 23.696 ;
     RECT  49.32 23.676 49.392 23.696 ;
     RECT  49.416 23.676 49.488 23.696 ;
     RECT  49.512 23.676 49.584 23.696 ;
     RECT  49.608 23.676 49.68 23.696 ;
     RECT  49.704 23.676 49.776 23.696 ;
     RECT  49.8 23.676 49.872 23.696 ;
     RECT  49.896 23.676 49.968 23.696 ;
     RECT  49.992 23.676 50.064 23.696 ;
     RECT  50.088 23.676 50.16 23.696 ;
     RECT  50.184 23.676 50.256 23.696 ;
     RECT  50.28 23.676 50.352 23.696 ;
     RECT  50.376 23.676 50.448 23.696 ;
     RECT  50.472 23.676 50.544 23.696 ;
     RECT  50.568 23.676 50.64 23.696 ;
     RECT  50.664 23.676 50.736 23.696 ;
     RECT  50.76 23.676 50.832 23.696 ;
     RECT  50.856 23.676 50.928 23.696 ;
     RECT  50.952 23.676 51.024 23.696 ;
     RECT  51.048 23.676 51.12 23.696 ;
     RECT  51.144 23.676 51.216 23.696 ;
     RECT  51.24 23.676 51.312 23.696 ;
     RECT  51.336 23.676 51.408 23.696 ;
     RECT  51.432 23.676 51.504 23.696 ;
     RECT  51.528 23.676 51.6 23.696 ;
     RECT  51.624 23.676 51.696 23.696 ;
     RECT  51.72 23.676 51.792 23.696 ;
     RECT  51.816 23.676 51.888 23.696 ;
     RECT  51.912 23.676 51.984 23.696 ;
     RECT  52.008 23.676 52.08 23.696 ;
     RECT  52.104 23.676 52.176 23.696 ;
     RECT  52.2 23.676 52.272 23.696 ;
     RECT  52.296 23.676 52.368 23.696 ;
     RECT  52.392 23.676 52.464 23.696 ;
     RECT  52.488 23.676 52.56 23.696 ;
     RECT  52.584 23.676 52.656 23.696 ;
     RECT  52.68 23.676 52.752 23.696 ;
     RECT  52.776 23.676 52.848 23.696 ;
     RECT  52.872 23.676 52.944 23.696 ;
     RECT  52.968 23.676 53.04 23.696 ;
     RECT  53.064 23.676 53.136 23.696 ;
     RECT  53.16 23.676 53.232 23.696 ;
     RECT  53.256 23.676 53.328 23.696 ;
     RECT  53.352 23.676 53.424 23.696 ;
     RECT  53.448 23.676 53.52 23.696 ;
     RECT  53.544 23.676 53.616 23.696 ;
     RECT  53.64 23.676 53.712 23.696 ;
     RECT  53.736 23.676 53.808 23.696 ;
     RECT  53.832 23.676 53.904 23.696 ;
     RECT  53.928 23.676 54 23.696 ;
     RECT  54.024 23.676 54.096 23.696 ;
     RECT  54.12 23.676 54.192 23.696 ;
     RECT  54.216 23.676 54.288 23.696 ;
     RECT  54.312 23.676 54.384 23.696 ;
     RECT  54.408 23.676 54.48 23.696 ;
     RECT  54.504 23.676 54.576 23.696 ;
     RECT  54.6 23.676 54.672 23.696 ;
     RECT  54.696 23.676 54.768 23.696 ;
     RECT  54.792 23.676 54.864 23.696 ;
     RECT  54.888 23.676 54.96 23.696 ;
     RECT  54.984 23.676 55.056 23.696 ;
     RECT  55.08 23.676 55.152 23.696 ;
     RECT  55.176 23.676 55.248 23.696 ;
     RECT  55.272 23.676 55.344 23.696 ;
     RECT  55.368 23.676 55.44 23.696 ;
     RECT  55.464 23.676 55.536 23.696 ;
     RECT  55.56 23.676 55.632 23.696 ;
     RECT  55.656 23.676 55.728 23.696 ;
     RECT  55.752 23.676 55.824 23.696 ;
     RECT  55.848 23.676 55.92 23.696 ;
     RECT  55.944 23.676 56.016 23.696 ;
     RECT  56.04 23.676 56.112 23.696 ;
     RECT  56.136 23.676 56.208 23.696 ;
     RECT  56.232 23.676 56.304 23.696 ;
     RECT  56.328 23.676 56.4 23.696 ;
     RECT  56.424 23.676 56.496 23.696 ;
     RECT  56.52 23.676 56.592 23.696 ;
     RECT  56.616 23.676 56.688 23.696 ;
     RECT  56.712 23.676 56.784 23.696 ;
     RECT  56.808 23.676 56.88 23.696 ;
     RECT  56.904 23.676 56.976 23.696 ;
     RECT  57 23.676 57.072 23.696 ;
     RECT  57.096 23.676 57.168 23.696 ;
     RECT  57.192 23.676 57.264 23.696 ;
     RECT  57.288 23.676 57.36 23.696 ;
     RECT  57.384 23.676 57.456 23.696 ;
     RECT  57.48 23.676 57.552 23.696 ;
     RECT  57.576 23.676 57.648 23.696 ;
     RECT  57.672 23.676 57.744 23.696 ;
     RECT  57.768 23.676 57.84 23.696 ;
     RECT  57.864 23.676 57.936 23.696 ;
     RECT  57.96 23.676 58.032 23.696 ;
     RECT  58.056 23.676 58.128 23.696 ;
     RECT  58.152 23.676 58.224 23.696 ;
     RECT  58.248 23.676 58.32 23.696 ;
     RECT  58.344 23.676 58.416 23.696 ;
     RECT  58.44 23.676 58.512 23.696 ;
     RECT  58.536 23.676 58.608 23.696 ;
     RECT  58.632 23.676 58.704 23.696 ;
     RECT  58.728 23.676 58.8 23.696 ;
     RECT  58.824 23.676 58.896 23.696 ;
     RECT  58.92 23.676 58.992 23.696 ;
     RECT  59.016 23.676 59.088 23.696 ;
     RECT  59.112 23.676 59.184 23.696 ;
     RECT  59.208 23.676 59.28 23.696 ;
     RECT  59.304 23.676 59.376 23.696 ;
     RECT  59.4 23.676 59.472 23.696 ;
     RECT  59.496 23.676 59.568 23.696 ;
     RECT  59.592 23.676 59.664 23.696 ;
     RECT  59.688 23.676 59.76 23.696 ;
     RECT  59.784 23.676 59.856 23.696 ;
     RECT  59.88 23.676 59.952 23.696 ;
     RECT  59.976 23.676 60.048 23.696 ;
     RECT  60.072 23.676 60.144 23.696 ;
     RECT  60.168 23.676 60.24 23.696 ;
     RECT  60.264 23.676 60.336 23.696 ;
     RECT  60.36 23.676 60.432 23.696 ;
     RECT  60.456 23.676 60.528 23.696 ;
     RECT  60.552 23.676 60.624 23.696 ;
     RECT  60.648 23.676 60.72 23.696 ;
     RECT  60.744 23.676 60.816 23.696 ;
     RECT  60.84 23.676 60.912 23.696 ;
     RECT  60.936 23.676 61.008 23.696 ;
     RECT  61.032 23.676 61.104 23.696 ;
     RECT  61.128 23.676 61.2 23.696 ;
     RECT  61.224 23.676 61.296 23.696 ;
     RECT  61.32 23.676 61.392 23.696 ;
     RECT  61.416 23.676 61.488 23.696 ;
     RECT  61.512 23.676 61.584 23.696 ;
     RECT  61.608 23.676 61.68 23.696 ;
     RECT  61.704 23.676 61.776 23.696 ;
     RECT  61.8 23.676 61.872 23.696 ;
     RECT  61.896 23.676 61.968 23.696 ;
     RECT  61.992 23.676 62.064 23.696 ;
     RECT  62.088 23.676 62.16 23.696 ;
     RECT  62.184 23.676 62.256 23.696 ;
     RECT  62.28 23.676 62.352 23.696 ;
     RECT  62.376 23.676 62.448 23.696 ;
     RECT  62.472 23.676 62.544 23.696 ;
     RECT  62.568 23.676 62.64 23.696 ;
     RECT  62.664 23.676 62.736 23.696 ;
     RECT  62.76 23.676 62.832 23.696 ;
     RECT  62.856 23.676 62.928 23.696 ;
     RECT  62.952 23.676 63.024 23.696 ;
     RECT  63.048 23.676 63.12 23.696 ;
     RECT  63.144 23.676 63.216 23.696 ;
     RECT  63.24 23.676 63.312 23.696 ;
     RECT  63.336 23.676 63.408 23.696 ;
     RECT  63.432 23.676 63.504 23.696 ;
     RECT  63.528 23.676 63.6 23.696 ;
     RECT  63.624 23.676 63.696 23.696 ;
     RECT  63.72 23.676 63.792 23.696 ;
     RECT  63.816 23.676 63.888 23.696 ;
     RECT  63.912 23.676 63.984 23.696 ;
     RECT  48.768 23.696 48.792 23.747 ;
     RECT  54.792 3.539 56.208 3.923 ;
     RECT  40.92 3.587 42.096 3.731 ;
     RECT  30.984 3.731 32.1 5.077 ;
     RECT  21.912 3.779 23.136 5.123 ;
     RECT  27.864 3.779 28.944 3.923 ;
     RECT  27.768 3.923 28.944 4.019 ;
     RECT  2.712 4.019 3.696 4.067 ;
     RECT  27.72 4.019 29.04 4.355 ;
     RECT  33.336 4.019 34.32 4.115 ;
     RECT  43.8 4.019 44.832 5.123 ;
     RECT  59.412 4.019 60.768 14.053 ;
     RECT  2.712 4.067 3.792 4.163 ;
     RECT  52.44 4.067 53.7 11.749 ;
     RECT  33.336 4.115 34.8 8.819 ;
     RECT  1.416 4.451 2.4 4.787 ;
     RECT  60.792 5.075 61.8 14.245 ;
     RECT  31.08 5.077 32.1 12.757 ;
     RECT  21.912 5.123 23.28 12.275 ;
     RECT  43.8 5.123 44.976 11.459 ;
     RECT  56.712 5.507 57.84 9.925 ;
     RECT  39.192 6.419 40.2 6.611 ;
     RECT  39.048 6.611 40.2 7.139 ;
     RECT  8.76 9.011 10.032 9.539 ;
     RECT  14.52 9.395 15.9 11.171 ;
     RECT  5.976 10.067 7.2 11.747 ;
     RECT  14.136 11.171 15.9 12.469 ;
     RECT  29.712 11.171 31.056 13.477 ;
     RECT  24.312 11.699 24.408 12.901 ;
     RECT  5.976 11.747 7.584 12.469 ;
     RECT  52.44 11.749 53.568 11.941 ;
     RECT  52.488 11.941 53.568 14.245 ;
     RECT  21.912 12.275 24 12.851 ;
     RECT  6.216 12.469 7.584 13.621 ;
     RECT  2.712 12.515 2.856 12.517 ;
     RECT  2.712 12.517 3.936 12.757 ;
     RECT  3.96 12.517 4.992 13.141 ;
     RECT  41.592 12.517 42.9 13.477 ;
     RECT  2.712 12.757 3.888 14.533 ;
     RECT  21.612 12.851 24 13.477 ;
     RECT  32.412 13.093 33.408 14.245 ;
     RECT  33.432 13.093 34.8 14.533 ;
     RECT  4.008 13.141 4.992 14.197 ;
     RECT  11.256 13.235 12.24 14.821 ;
     RECT  21.612 13.477 22.944 13.669 ;
     RECT  22.968 13.477 24 13.621 ;
     RECT  43.8 13.477 44.976 13.525 ;
     RECT  39.144 13.621 40.2 13.909 ;
     RECT  21.612 13.669 22.656 14.197 ;
     RECT  46.968 14.053 48.3 15.925 ;
     RECT  33.432 14.533 34.56 14.773 ;
     RECT  8.112 14.629 9.12 14.773 ;
     RECT  24.792 15.827 25.032 16.405 ;
     RECT  47.16 15.925 48.3 16.357 ;
     RECT  24.792 16.405 25.872 16.837 ;
     RECT  6.312 21.155 7.536 22.165 ;
  END
END hbfd_rly_624_SN_rr
END LIBRARY
